Omron Sysmac Studio project ECT 自定义指令功能 20240816 (Sysmac Studio 1.50.0.64013, StandardProject)
(* 指令扩充 *)

# Controller new_Controller_0: NX102-1100 version 1.47
Units and slaves: 节点1 : CIFX RE/ECS (E001)
Task PrimaryTask (priority 4, period or condition 4000): program0

TYPE 机器人状态反馈1 : UNION
    motionstate1 : BYTE;
    state1 : ARRAY[0..7] OF BOOL;
END_UNION END_TYPE
TYPE 机器人状态反馈2 : UNION
    motionstate2 : BYTE;
    state2 : ARRAY[0..7] OF BOOL;
END_UNION END_TYPE
TYPE 机器人状态反馈3 : UNION
    motionstate3 : BYTE;
END_UNION END_TYPE
TYPE 机器人状态反馈4 : UNION
    motionstate4 : BYTE;
END_UNION END_TYPE

VAR_GLOBAL
    M0 : BOOL;  (* published *)
    M1 : BOOL;  (* published *)
    M2 : BOOL;  (* published *)
    M3 : BOOL;  (* published *)
    RobotCMD : UINT;
    RobotCMDLength : BYTE;
    RobotCMDState : BYTE;
    Robot_Header : ARRAY[0..5] OF BYTE;
    Robot_CMDHeader : ARRAY[0..9] OF BYTE;
    Robot_CMDPayload : ARRAY[0..119] OF BYTE;
    Robot_CyclicData : ARRAY[0..118] OF BYTE;
    Robot_Fooder : BYTE;
    M100 : BOOL;  (* published *)
    M101 : BOOL;  (* published *)
    M102 : BOOL;  (* published *)
    M103 : BOOL;  (* published *)
    M200 : BOOL;  (* published *)
    M201 : BOOL;  (* published *)
    M202 : BOOL;  (* published *)
    M203 : BOOL;  (* published *)
    M300 : BOOL;  (* published *)
    M301 : BOOL;  (* published *)
    M302 : BOOL;  (* network output *)
    M303 : BOOL;  (* network output *)
    M304 : BOOL;  (* network output *)
    M305 : BOOL;  (* network output *)
    M306 : BOOL;  (* network output *)
    EnableState : BOOL;
    R218L : BYTE;  (* network input *)
    R205 : REAL;  (* network input *)
    R207 : REAL;  (* network input *)
    R209 : REAL;  (* network input *)
    R211 : REAL;  (* network input *)
    R213 : REAL;  (* network input *)
    R215 : REAL;  (* network input *)
    R252 : UINT;  (* network output *)
    R218 : UINT;  (* network output *)
    R160 : REAL;  (* network output *)
    R105L : BYTE;  (* network input *)
    R162 : REAL;  (* network output *)
    R164 : REAL;  (* network output *)
    R166 : REAL;  (* network output *)
    R168 : REAL;  (* network output *)
    R170 : REAL;  (* network output *)
    R152 : UINT;  (* network output *)
    R352 : UINT;  (* network output *)
    R325L : BYTE;  (* network input *)
    R317 : REAL;  (* network input *)
    R319 : REAL;  (* network input *)
    R305 : REAL;  (* network input *)
    R307 : REAL;  (* network input *)
    R309 : REAL;  (* network input *)
    R311 : REAL;  (* network input *)
    R312 : REAL;  (* network input *)
    R313 : REAL;  (* network input *)
    R315 : REAL;  (* network input *)
    R12 : UINT;  (* published *)
    M400 : BOOL;  (* published *)
    R425L : BYTE;  (* published *)
    R417 : REAL;  (* published *)
    R419 : REAL;  (* published *)
    R405 : REAL;  (* published *)
    R407 : REAL;  (* published *)
    R409 : REAL;  (* published *)
    R411 : REAL;  (* published *)
    R413 : REAL;  (* published *)
    R415 : REAL;  (* published *)
    M401 : BOOL;  (* published *)
    M402 : BOOL;  (* published *)
    M404 : BOOL;  (* published *)
    M405 : BOOL;  (* published *)
    M406 : BOOL;  (* published *)
    M403 : BOOL;  (* published *)
    R452 : UINT;  (* published *)
    M500 : BOOL;  (* published *)
    R525L : BYTE;  (* published *)
    R525H : BYTE;  (* published *)
    R517 : REAL;  (* published *)
    R519 : REAL;  (* published *)
    R505 : REAL;  (* published *)
    R507 : REAL;  (* published *)
    R509 : REAL;  (* published *)
    R511 : REAL;  (* published *)
    R513 : REAL;  (* published *)
    R515 : REAL;  (* published *)
    M501 : BOOL;  (* published *)
    M502 : BOOL;  (* published *)
    M503 : BOOL;  (* published *)
    M504 : BOOL;  (* published *)
    M505 : BOOL;  (* published *)
    M506 : BOOL;  (* published *)
    R552 : UINT;  (* published *)
    B0 : BOOL;  (* LINK; published *)
    PLC_Header : ARRAY[0..5] OF BYTE;
    PLC_CMDHeader : ARRAY[0..9] OF BYTE;
    PLC_CMDPayload : ARRAY[0..238] OF BYTE;
    TOOLDATA_X : REAL;  (* published *)
    TOOLDATA_Y : REAL;  (* published *)
    TOOLDATA_Z : REAL;  (* published *)
    TOOLDATA_RX : REAL;  (* published *)
    TOOLDATA_RY : REAL;  (* published *)
    TOOLDATA_RZ : REAL;  (* published *)
    ROBOT_J1 : REAL;  (* published *)
    ROBOT_J2 : REAL;  (* published *)
    ROBOT_J3 : REAL;  (* published *)
    ROBOT_J4 : REAL;  (* published *)
    ROBOT_J5 : REAL;  (* published *)
    ROBOT_J6 : REAL;  (* published *)
    ROBOT_TOOLNO : BYTE;  (* published *)
    ROBOT_FRAMENO : BYTE;  (* published *)
    B1 : BOOL;  (* 已使能; published *)
    B2 : BOOL;  (* 运动完成; published *)
    B3 : BOOL;  (* 自动模式; published *)
    B4 : BOOL;  (* 手动模式; published *)
    B5 : BOOL;  (* 本地模式; published *)
    B6 : BOOL;  (* 远程模式; published *)
    B7 : BOOL;  (* 停止; published *)
    B8 : BOOL;  (* 运行; published *)
    B9 : BOOL;  (* 暂停; published *)
    B10 : BOOL;  (* 拖动; published *)
    B11 : BOOL;  (* 机器人报错; published *)
    Joint_Move : BOOL;  (* published *)
    Cartesian_Move : BOOL;  (* published *)
    ECT_OUT : ARRAY[0..255] OF BYTE;  (* network output *)
    ECT_IN : ARRAY[0..255] OF BYTE;  (* network input *)
    RobotCMDErrorcode : BYTE;
    R218H : BYTE;  (* published *)
    R217L : BOOL;  (* published *)
    R217H : BOOL;  (* published *)
    R172L : BOOL;  (* published *)
    R172H : BOOL;  (* published *)
    R173L : BOOL;  (* published *)
    M600 : BOOL;  (* published *)
    Out0 : BYTE;  (* at ECAT://node#1/Outputs0_1 Byte Out (0)_2000_01; network output *)
    Out1 : BYTE;  (* at ECAT://node#1/Outputs0_1 Byte Out (1)_2000_02; network output *)
    Out2 : BYTE;  (* at ECAT://node#1/Outputs0_1 Byte Out (2)_2000_03; network output *)
    Out3 : BYTE;  (* at ECAT://node#1/Outputs0_1 Byte Out (3)_2000_04; network output *)
    Out4 : BYTE;  (* at ECAT://node#1/Outputs0_1 Byte Out (4)_2000_05; network output *)
    Out5 : BYTE;  (* at ECAT://node#1/Outputs0_1 Byte Out (5)_2000_06; network output *)
    Out6 : BYTE;  (* at ECAT://node#1/Outputs0_1 Byte Out (6)_2000_07; network output *)
    Out7 : BYTE;  (* at ECAT://node#1/Outputs0_1 Byte Out (7)_2000_08; network output *)
    Out8 : BYTE;  (* at ECAT://node#1/Outputs0_1 Byte Out (8)_2000_09; network output *)
    Out9 : BYTE;  (* at ECAT://node#1/Outputs0_1 Byte Out (9)_2000_0A; network output *)
    Out10 : BYTE;  (* at ECAT://node#1/Outputs0_1 Byte Out (10)_2000_0B; network output *)
    Out11 : BYTE;  (* at ECAT://node#1/Outputs0_1 Byte Out (11)_2000_0C; network output *)
    Out12 : BYTE;  (* at ECAT://node#1/Outputs0_1 Byte Out (12)_2000_0D; network output *)
    Out13 : BYTE;  (* at ECAT://node#1/Outputs0_1 Byte Out (13)_2000_0E; network output *)
    Out14 : BYTE;  (* at ECAT://node#1/Outputs0_1 Byte Out (14)_2000_0F; network output *)
    Out15 : BYTE;  (* at ECAT://node#1/Outputs0_1 Byte Out (15)_2000_10; network output *)
    Out16 : BYTE;  (* at ECAT://node#1/Outputs0_1 Byte Out (16)_2000_11; network output *)
    Out17 : BYTE;  (* at ECAT://node#1/Outputs0_1 Byte Out (17)_2000_12; network output *)
    Out18 : BYTE;  (* at ECAT://node#1/Outputs0_1 Byte Out (18)_2000_13; network output *)
    Out19 : BYTE;  (* at ECAT://node#1/Outputs0_1 Byte Out (19)_2000_14; network output *)
    Out20 : BYTE;  (* at ECAT://node#1/Outputs0_1 Byte Out (20)_2000_15; network output *)
    Out21 : BYTE;  (* at ECAT://node#1/Outputs0_1 Byte Out (21)_2000_16; network output *)
    Out22 : BYTE;  (* at ECAT://node#1/Outputs0_1 Byte Out (22)_2000_17; network output *)
    Out23 : BYTE;  (* at ECAT://node#1/Outputs0_1 Byte Out (23)_2000_18; network output *)
    Out24 : BYTE;  (* at ECAT://node#1/Outputs0_1 Byte Out (24)_2000_19; network output *)
    Out25 : BYTE;  (* at ECAT://node#1/Outputs0_1 Byte Out (25)_2000_1A; network output *)
    Out26 : BYTE;  (* at ECAT://node#1/Outputs0_1 Byte Out (26)_2000_1B; network output *)
    Out27 : BYTE;  (* at ECAT://node#1/Outputs0_1 Byte Out (27)_2000_1C; network output *)
    Out28 : BYTE;  (* at ECAT://node#1/Outputs0_1 Byte Out (28)_2000_1D; network output *)
    Out29 : BYTE;  (* at ECAT://node#1/Outputs0_1 Byte Out (29)_2000_1E; network output *)
    Out30 : BYTE;  (* at ECAT://node#1/Outputs0_1 Byte Out (30)_2000_1F; network output *)
    Out31 : BYTE;  (* at ECAT://node#1/Outputs0_1 Byte Out (31)_2000_20; network output *)
    Out32 : BYTE;  (* at ECAT://node#1/Outputs0_1 Byte Out (32)_2000_21; network output *)
    Out33 : BYTE;  (* at ECAT://node#1/Outputs0_1 Byte Out (33)_2000_22; network output *)
    Out34 : BYTE;  (* at ECAT://node#1/Outputs0_1 Byte Out (34)_2000_23; network output *)
    Out35 : BYTE;  (* at ECAT://node#1/Outputs0_1 Byte Out (35)_2000_24; network output *)
    Out36 : BYTE;  (* at ECAT://node#1/Outputs0_1 Byte Out (36)_2000_25; network output *)
    Out37 : BYTE;  (* at ECAT://node#1/Outputs0_1 Byte Out (37)_2000_26; network output *)
    Out38 : BYTE;  (* at ECAT://node#1/Outputs0_1 Byte Out (38)_2000_27; network output *)
    Out39 : BYTE;  (* at ECAT://node#1/Outputs0_1 Byte Out (39)_2000_28; network output *)
    Out40 : BYTE;  (* at ECAT://node#1/Outputs0_1 Byte Out (40)_2000_29; network output *)
    Out41 : BYTE;  (* at ECAT://node#1/Outputs0_1 Byte Out (41)_2000_2A; network output *)
    Out42 : BYTE;  (* at ECAT://node#1/Outputs0_1 Byte Out (42)_2000_2B; network output *)
    Out43 : BYTE;  (* at ECAT://node#1/Outputs0_1 Byte Out (43)_2000_2C; network output *)
    Out44 : BYTE;  (* at ECAT://node#1/Outputs0_1 Byte Out (44)_2000_2D; network output *)
    Out45 : BYTE;  (* at ECAT://node#1/Outputs0_1 Byte Out (45)_2000_2E; network output *)
    Out46 : BYTE;  (* at ECAT://node#1/Outputs0_1 Byte Out (46)_2000_2F; network output *)
    Out47 : BYTE;  (* at ECAT://node#1/Outputs0_1 Byte Out (47)_2000_30; network output *)
    Out48 : BYTE;  (* at ECAT://node#1/Outputs0_1 Byte Out (48)_2000_31; network output *)
    Out49 : BYTE;  (* at ECAT://node#1/Outputs0_1 Byte Out (49)_2000_32; network output *)
    Out50 : BYTE;  (* at ECAT://node#1/Outputs0_1 Byte Out (50)_2000_33; network output *)
    Out51 : BYTE;  (* at ECAT://node#1/Outputs0_1 Byte Out (51)_2000_34; network output *)
    Out52 : BYTE;  (* at ECAT://node#1/Outputs0_1 Byte Out (52)_2000_35; network output *)
    Out53 : BYTE;  (* at ECAT://node#1/Outputs0_1 Byte Out (53)_2000_36; network output *)
    Out54 : BYTE;  (* at ECAT://node#1/Outputs0_1 Byte Out (54)_2000_37; network output *)
    Out55 : BYTE;  (* at ECAT://node#1/Outputs0_1 Byte Out (55)_2000_38; network output *)
    Out56 : BYTE;  (* at ECAT://node#1/Outputs0_1 Byte Out (56)_2000_39; network output *)
    Out57 : BYTE;  (* at ECAT://node#1/Outputs0_1 Byte Out (57)_2000_3A; network output *)
    Out58 : BYTE;  (* at ECAT://node#1/Outputs0_1 Byte Out (58)_2000_3B; network output *)
    Out59 : BYTE;  (* at ECAT://node#1/Outputs0_1 Byte Out (59)_2000_3C; network output *)
    Out60 : BYTE;  (* at ECAT://node#1/Outputs0_1 Byte Out (60)_2000_3D; network output *)
    Out61 : BYTE;  (* at ECAT://node#1/Outputs0_1 Byte Out (61)_2000_3E; network output *)
    Out62 : BYTE;  (* at ECAT://node#1/Outputs0_1 Byte Out (62)_2000_3F; network output *)
    Out63 : BYTE;  (* at ECAT://node#1/Outputs0_1 Byte Out (63)_2000_40; network output *)
    Out64 : BYTE;  (* at ECAT://node#1/Outputs0_1 Byte Out (64)_2000_41; network output *)
    Out65 : BYTE;  (* at ECAT://node#1/Outputs0_1 Byte Out (65)_2000_42; network output *)
    Out66 : BYTE;  (* at ECAT://node#1/Outputs0_1 Byte Out (66)_2000_43; network output *)
    Out67 : BYTE;  (* at ECAT://node#1/Outputs0_1 Byte Out (67)_2000_44; network output *)
    Out68 : BYTE;  (* at ECAT://node#1/Outputs0_1 Byte Out (68)_2000_45; network output *)
    Out69 : BYTE;  (* at ECAT://node#1/Outputs0_1 Byte Out (69)_2000_46; network output *)
    Out70 : BYTE;  (* at ECAT://node#1/Outputs0_1 Byte Out (70)_2000_47; network output *)
    Out71 : BYTE;  (* at ECAT://node#1/Outputs0_1 Byte Out (71)_2000_48; network output *)
    Out72 : BYTE;  (* at ECAT://node#1/Outputs0_1 Byte Out (72)_2000_49; network output *)
    Out73 : BYTE;  (* at ECAT://node#1/Outputs0_1 Byte Out (73)_2000_4A; network output *)
    Out74 : BYTE;  (* at ECAT://node#1/Outputs0_1 Byte Out (74)_2000_4B; network output *)
    Out75 : BYTE;  (* at ECAT://node#1/Outputs0_1 Byte Out (75)_2000_4C; network output *)
    Out76 : BYTE;  (* at ECAT://node#1/Outputs0_1 Byte Out (76)_2000_4D; network output *)
    Out77 : BYTE;  (* at ECAT://node#1/Outputs0_1 Byte Out (77)_2000_4E; network output *)
    Out78 : BYTE;  (* at ECAT://node#1/Outputs0_1 Byte Out (78)_2000_4F; network output *)
    Out79 : BYTE;  (* at ECAT://node#1/Outputs0_1 Byte Out (79)_2000_50; network output *)
    Out80 : BYTE;  (* at ECAT://node#1/Outputs0_1 Byte Out (80)_2000_51; network output *)
    Out81 : BYTE;  (* at ECAT://node#1/Outputs0_1 Byte Out (81)_2000_52; network output *)
    Out82 : BYTE;  (* at ECAT://node#1/Outputs0_1 Byte Out (82)_2000_53; network output *)
    Out83 : BYTE;  (* at ECAT://node#1/Outputs0_1 Byte Out (83)_2000_54; network output *)
    Out84 : BYTE;  (* at ECAT://node#1/Outputs0_1 Byte Out (84)_2000_55; network output *)
    Out85 : BYTE;  (* at ECAT://node#1/Outputs0_1 Byte Out (85)_2000_56; network output *)
    Out86 : BYTE;  (* at ECAT://node#1/Outputs0_1 Byte Out (86)_2000_57; network output *)
    Out87 : BYTE;  (* at ECAT://node#1/Outputs0_1 Byte Out (87)_2000_58; network output *)
    Out88 : BYTE;  (* at ECAT://node#1/Outputs0_1 Byte Out (88)_2000_59; network output *)
    Out89 : BYTE;  (* at ECAT://node#1/Outputs0_1 Byte Out (89)_2000_5A; network output *)
    Out90 : BYTE;  (* at ECAT://node#1/Outputs0_1 Byte Out (90)_2000_5B; network output *)
    Out91 : BYTE;  (* at ECAT://node#1/Outputs0_1 Byte Out (91)_2000_5C; network output *)
    Out92 : BYTE;  (* at ECAT://node#1/Outputs0_1 Byte Out (92)_2000_5D; network output *)
    Out93 : BYTE;  (* at ECAT://node#1/Outputs0_1 Byte Out (93)_2000_5E; network output *)
    Out94 : BYTE;  (* at ECAT://node#1/Outputs0_1 Byte Out (94)_2000_5F; network output *)
    Out95 : BYTE;  (* at ECAT://node#1/Outputs0_1 Byte Out (95)_2000_60; network output *)
    Out96 : BYTE;  (* at ECAT://node#1/Outputs0_1 Byte Out (96)_2000_61; network output *)
    Out97 : BYTE;  (* at ECAT://node#1/Outputs0_1 Byte Out (97)_2000_62; network output *)
    Out98 : BYTE;  (* at ECAT://node#1/Outputs0_1 Byte Out (98)_2000_63; network output *)
    Out99 : BYTE;  (* at ECAT://node#1/Outputs0_1 Byte Out (99)_2000_64; network output *)
    Out100 : BYTE;  (* at ECAT://node#1/Outputs0_1 Byte Out (100)_2000_65; network output *)
    Out101 : BYTE;  (* at ECAT://node#1/Outputs0_1 Byte Out (101)_2000_66; network output *)
    Out102 : BYTE;  (* at ECAT://node#1/Outputs0_1 Byte Out (102)_2000_67; network output *)
    Out103 : BYTE;  (* at ECAT://node#1/Outputs0_1 Byte Out (103)_2000_68; network output *)
    Out104 : BYTE;  (* at ECAT://node#1/Outputs0_1 Byte Out (104)_2000_69; network output *)
    Out105 : BYTE;  (* at ECAT://node#1/Outputs0_1 Byte Out (105)_2000_6A; network output *)
    Out106 : BYTE;  (* at ECAT://node#1/Outputs0_1 Byte Out (106)_2000_6B; network output *)
    Out107 : BYTE;  (* at ECAT://node#1/Outputs0_1 Byte Out (107)_2000_6C; network output *)
    Out108 : BYTE;  (* at ECAT://node#1/Outputs0_1 Byte Out (108)_2000_6D; network output *)
    Out109 : BYTE;  (* at ECAT://node#1/Outputs0_1 Byte Out (109)_2000_6E; network output *)
    Out110 : BYTE;  (* at ECAT://node#1/Outputs0_1 Byte Out (110)_2000_6F; network output *)
    Out111 : BYTE;  (* at ECAT://node#1/Outputs0_1 Byte Out (111)_2000_70; network output *)
    Out112 : BYTE;  (* at ECAT://node#1/Outputs0_1 Byte Out (112)_2000_71; network output *)
    Out113 : BYTE;  (* at ECAT://node#1/Outputs0_1 Byte Out (113)_2000_72; network output *)
    Out114 : BYTE;  (* at ECAT://node#1/Outputs0_1 Byte Out (114)_2000_73; network output *)
    Out115 : BYTE;  (* at ECAT://node#1/Outputs0_1 Byte Out (115)_2000_74; network output *)
    Out116 : BYTE;  (* at ECAT://node#1/Outputs0_1 Byte Out (116)_2000_75; network output *)
    Out117 : BYTE;  (* at ECAT://node#1/Outputs0_1 Byte Out (117)_2000_76; network output *)
    Out118 : BYTE;  (* at ECAT://node#1/Outputs0_1 Byte Out (118)_2000_77; network output *)
    Out119 : BYTE;  (* at ECAT://node#1/Outputs0_1 Byte Out (119)_2000_78; network output *)
    Out120 : BYTE;  (* at ECAT://node#1/Outputs0_1 Byte Out (120)_2000_79; network output *)
    Out121 : BYTE;  (* at ECAT://node#1/Outputs0_1 Byte Out (121)_2000_7A; network output *)
    Out122 : BYTE;  (* at ECAT://node#1/Outputs0_1 Byte Out (122)_2000_7B; network output *)
    Out123 : BYTE;  (* at ECAT://node#1/Outputs0_1 Byte Out (123)_2000_7C; network output *)
    Out124 : BYTE;  (* at ECAT://node#1/Outputs0_1 Byte Out (124)_2000_7D; network output *)
    Out125 : BYTE;  (* at ECAT://node#1/Outputs0_1 Byte Out (125)_2000_7E; network output *)
    Out126 : BYTE;  (* at ECAT://node#1/Outputs0_1 Byte Out (126)_2000_7F; network output *)
    Out127 : BYTE;  (* at ECAT://node#1/Outputs0_1 Byte Out (127)_2000_80; network output *)
    Out128 : BYTE;  (* at ECAT://node#1/Outputs0_1 Byte Out (128)_2000_81; network output *)
    Out129 : BYTE;  (* at ECAT://node#1/Outputs0_1 Byte Out (129)_2000_82; network output *)
    Out130 : BYTE;  (* at ECAT://node#1/Outputs0_1 Byte Out (130)_2000_83; network output *)
    Out131 : BYTE;  (* at ECAT://node#1/Outputs0_1 Byte Out (131)_2000_84; network output *)
    Out132 : BYTE;  (* at ECAT://node#1/Outputs0_1 Byte Out (132)_2000_85; network output *)
    Out133 : BYTE;  (* at ECAT://node#1/Outputs0_1 Byte Out (133)_2000_86; network output *)
    Out134 : BYTE;  (* at ECAT://node#1/Outputs0_1 Byte Out (134)_2000_87; network output *)
    Out135 : BYTE;  (* at ECAT://node#1/Outputs0_1 Byte Out (135)_2000_88; network output *)
    Out136 : BYTE;  (* at ECAT://node#1/Outputs0_1 Byte Out (136)_2000_89; network output *)
    Out137 : BYTE;  (* at ECAT://node#1/Outputs0_1 Byte Out (137)_2000_8A; network output *)
    Out138 : BYTE;  (* at ECAT://node#1/Outputs0_1 Byte Out (138)_2000_8B; network output *)
    Out139 : BYTE;  (* at ECAT://node#1/Outputs0_1 Byte Out (139)_2000_8C; network output *)
    Out140 : BYTE;  (* at ECAT://node#1/Outputs0_1 Byte Out (140)_2000_8D; network output *)
    Out141 : BYTE;  (* at ECAT://node#1/Outputs0_1 Byte Out (141)_2000_8E; network output *)
    Out142 : BYTE;  (* at ECAT://node#1/Outputs0_1 Byte Out (142)_2000_8F; network output *)
    Out143 : BYTE;  (* at ECAT://node#1/Outputs0_1 Byte Out (143)_2000_90; network output *)
    Out144 : BYTE;  (* at ECAT://node#1/Outputs0_1 Byte Out (144)_2000_91; network output *)
    Out145 : BYTE;  (* at ECAT://node#1/Outputs0_1 Byte Out (145)_2000_92; network output *)
    Out146 : BYTE;  (* at ECAT://node#1/Outputs0_1 Byte Out (146)_2000_93; network output *)
    Out147 : BYTE;  (* at ECAT://node#1/Outputs0_1 Byte Out (147)_2000_94; network output *)
    Out148 : BYTE;  (* at ECAT://node#1/Outputs0_1 Byte Out (148)_2000_95; network output *)
    Out149 : BYTE;  (* at ECAT://node#1/Outputs0_1 Byte Out (149)_2000_96; network output *)
    Out150 : BYTE;  (* at ECAT://node#1/Outputs0_1 Byte Out (150)_2000_97; network output *)
    Out151 : BYTE;  (* at ECAT://node#1/Outputs0_1 Byte Out (151)_2000_98; network output *)
    Out152 : BYTE;  (* at ECAT://node#1/Outputs0_1 Byte Out (152)_2000_99; network output *)
    Out153 : BYTE;  (* at ECAT://node#1/Outputs0_1 Byte Out (153)_2000_9A; network output *)
    Out154 : BYTE;  (* at ECAT://node#1/Outputs0_1 Byte Out (154)_2000_9B; network output *)
    Out155 : BYTE;  (* at ECAT://node#1/Outputs0_1 Byte Out (155)_2000_9C; network output *)
    Out156 : BYTE;  (* at ECAT://node#1/Outputs0_1 Byte Out (156)_2000_9D; network output *)
    Out157 : BYTE;  (* at ECAT://node#1/Outputs0_1 Byte Out (157)_2000_9E; network output *)
    Out158 : BYTE;  (* at ECAT://node#1/Outputs0_1 Byte Out (158)_2000_9F; network output *)
    Out159 : BYTE;  (* at ECAT://node#1/Outputs0_1 Byte Out (159)_2000_A0; network output *)
    Out160 : BYTE;  (* at ECAT://node#1/Outputs0_1 Byte Out (160)_2000_A1; network output *)
    Out161 : BYTE;  (* at ECAT://node#1/Outputs0_1 Byte Out (161)_2000_A2; network output *)
    Out162 : BYTE;  (* at ECAT://node#1/Outputs0_1 Byte Out (162)_2000_A3; network output *)
    Out163 : BYTE;  (* at ECAT://node#1/Outputs0_1 Byte Out (163)_2000_A4; network output *)
    Out164 : BYTE;  (* at ECAT://node#1/Outputs0_1 Byte Out (164)_2000_A5; network output *)
    Out165 : BYTE;  (* at ECAT://node#1/Outputs0_1 Byte Out (165)_2000_A6; network output *)
    Out166 : BYTE;  (* at ECAT://node#1/Outputs0_1 Byte Out (166)_2000_A7; network output *)
    Out167 : BYTE;  (* at ECAT://node#1/Outputs0_1 Byte Out (167)_2000_A8; network output *)
    Out168 : BYTE;  (* at ECAT://node#1/Outputs0_1 Byte Out (168)_2000_A9; network output *)
    Out169 : BYTE;  (* at ECAT://node#1/Outputs0_1 Byte Out (169)_2000_AA; network output *)
    Out170 : BYTE;  (* at ECAT://node#1/Outputs0_1 Byte Out (170)_2000_AB; network output *)
    Out171 : BYTE;  (* at ECAT://node#1/Outputs0_1 Byte Out (171)_2000_AC; network output *)
    Out172 : BYTE;  (* at ECAT://node#1/Outputs0_1 Byte Out (172)_2000_AD; network output *)
    Out173 : BYTE;  (* at ECAT://node#1/Outputs0_1 Byte Out (173)_2000_AE; network output *)
    Out174 : BYTE;  (* at ECAT://node#1/Outputs0_1 Byte Out (174)_2000_AF; network output *)
    Out175 : BYTE;  (* at ECAT://node#1/Outputs0_1 Byte Out (175)_2000_B0; network output *)
    Out176 : BYTE;  (* at ECAT://node#1/Outputs0_1 Byte Out (176)_2000_B1; network output *)
    Out177 : BYTE;  (* at ECAT://node#1/Outputs0_1 Byte Out (177)_2000_B2; network output *)
    Out178 : BYTE;  (* at ECAT://node#1/Outputs0_1 Byte Out (178)_2000_B3; network output *)
    Out179 : BYTE;  (* at ECAT://node#1/Outputs0_1 Byte Out (179)_2000_B4; network output *)
    Out180 : BYTE;  (* at ECAT://node#1/Outputs0_1 Byte Out (180)_2000_B5; network output *)
    Out181 : BYTE;  (* at ECAT://node#1/Outputs0_1 Byte Out (181)_2000_B6; network output *)
    Out182 : BYTE;  (* at ECAT://node#1/Outputs0_1 Byte Out (182)_2000_B7; network output *)
    Out183 : BYTE;  (* at ECAT://node#1/Outputs0_1 Byte Out (183)_2000_B8; network output *)
    Out184 : BYTE;  (* at ECAT://node#1/Outputs0_1 Byte Out (184)_2000_B9; network output *)
    Out185 : BYTE;  (* at ECAT://node#1/Outputs0_1 Byte Out (185)_2000_BA; network output *)
    Out186 : BYTE;  (* at ECAT://node#1/Outputs0_1 Byte Out (186)_2000_BB; network output *)
    Out187 : BYTE;  (* at ECAT://node#1/Outputs0_1 Byte Out (187)_2000_BC; network output *)
    Out188 : BYTE;  (* at ECAT://node#1/Outputs0_1 Byte Out (188)_2000_BD; network output *)
    Out189 : BYTE;  (* at ECAT://node#1/Outputs0_1 Byte Out (189)_2000_BE; network output *)
    Out190 : BYTE;  (* at ECAT://node#1/Outputs0_1 Byte Out (190)_2000_BF; network output *)
    Out191 : BYTE;  (* at ECAT://node#1/Outputs0_1 Byte Out (191)_2000_C0; network output *)
    Out192 : BYTE;  (* at ECAT://node#1/Outputs0_1 Byte Out (192)_2000_C1; network output *)
    Out193 : BYTE;  (* at ECAT://node#1/Outputs0_1 Byte Out (193)_2000_C2; network output *)
    Out194 : BYTE;  (* at ECAT://node#1/Outputs0_1 Byte Out (194)_2000_C3; network output *)
    Out195 : BYTE;  (* at ECAT://node#1/Outputs0_1 Byte Out (195)_2000_C4; network output *)
    Out196 : BYTE;  (* at ECAT://node#1/Outputs0_1 Byte Out (196)_2000_C5; network output *)
    Out197 : BYTE;  (* at ECAT://node#1/Outputs0_1 Byte Out (197)_2000_C6; network output *)
    Out198 : BYTE;  (* at ECAT://node#1/Outputs0_1 Byte Out (198)_2000_C7; network output *)
    Out199 : BYTE;  (* at ECAT://node#1/Outputs0_1 Byte Out (199)_2000_C8; network output *)
    Out200 : BYTE;  (* at ECAT://node#1/Outputs1_1 Byte Out (200)_2001_01; network output *)
    Out201 : BYTE;  (* at ECAT://node#1/Outputs1_1 Byte Out (201)_2001_02; network output *)
    Out202 : BYTE;  (* at ECAT://node#1/Outputs1_1 Byte Out (202)_2001_03; network output *)
    Out203 : BYTE;  (* at ECAT://node#1/Outputs1_1 Byte Out (203)_2001_04; network output *)
    Out204 : BYTE;  (* at ECAT://node#1/Outputs1_1 Byte Out (204)_2001_05; network output *)
    Out205 : BYTE;  (* at ECAT://node#1/Outputs1_1 Byte Out (205)_2001_06; network output *)
    Out206 : BYTE;  (* at ECAT://node#1/Outputs1_1 Byte Out (206)_2001_07; network output *)
    Out207 : BYTE;  (* at ECAT://node#1/Outputs1_1 Byte Out (207)_2001_08; network output *)
    Out208 : BYTE;  (* at ECAT://node#1/Outputs1_1 Byte Out (208)_2001_09; network output *)
    Out209 : BYTE;  (* at ECAT://node#1/Outputs1_1 Byte Out (209)_2001_0A; network output *)
    Out210 : BYTE;  (* at ECAT://node#1/Outputs1_1 Byte Out (210)_2001_0B; network output *)
    Out211 : BYTE;  (* at ECAT://node#1/Outputs1_1 Byte Out (211)_2001_0C; network output *)
    Out212 : BYTE;  (* at ECAT://node#1/Outputs1_1 Byte Out (212)_2001_0D; network output *)
    Out213 : BYTE;  (* at ECAT://node#1/Outputs1_1 Byte Out (213)_2001_0E; network output *)
    Out214 : BYTE;  (* at ECAT://node#1/Outputs1_1 Byte Out (214)_2001_0F; network output *)
    Out215 : BYTE;  (* at ECAT://node#1/Outputs1_1 Byte Out (215)_2001_10; network output *)
    Out216 : BYTE;  (* at ECAT://node#1/Outputs1_1 Byte Out (216)_2001_11; network output *)
    Out217 : BYTE;  (* at ECAT://node#1/Outputs1_1 Byte Out (217)_2001_12; network output *)
    Out218 : BYTE;  (* at ECAT://node#1/Outputs1_1 Byte Out (218)_2001_13; network output *)
    Out219 : BYTE;  (* at ECAT://node#1/Outputs1_1 Byte Out (219)_2001_14; network output *)
    Out220 : BYTE;  (* at ECAT://node#1/Outputs1_1 Byte Out (220)_2001_15; network output *)
    Out221 : BYTE;  (* at ECAT://node#1/Outputs1_1 Byte Out (221)_2001_16; network output *)
    Out222 : BYTE;  (* at ECAT://node#1/Outputs1_1 Byte Out (222)_2001_17; network output *)
    Out223 : BYTE;  (* at ECAT://node#1/Outputs1_1 Byte Out (223)_2001_18; network output *)
    Out224 : BYTE;  (* at ECAT://node#1/Outputs1_1 Byte Out (224)_2001_19; network output *)
    Out225 : BYTE;  (* at ECAT://node#1/Outputs1_1 Byte Out (225)_2001_1A; network output *)
    Out226 : BYTE;  (* at ECAT://node#1/Outputs1_1 Byte Out (226)_2001_1B; network output *)
    Out227 : BYTE;  (* at ECAT://node#1/Outputs1_1 Byte Out (227)_2001_1C; network output *)
    Out228 : BYTE;  (* at ECAT://node#1/Outputs1_1 Byte Out (228)_2001_1D; network output *)
    Out229 : BYTE;  (* at ECAT://node#1/Outputs1_1 Byte Out (229)_2001_1E; network output *)
    Out230 : BYTE;  (* at ECAT://node#1/Outputs1_1 Byte Out (230)_2001_1F; network output *)
    Out231 : BYTE;  (* at ECAT://node#1/Outputs1_1 Byte Out (231)_2001_20; network output *)
    Out232 : BYTE;  (* at ECAT://node#1/Outputs1_1 Byte Out (232)_2001_21; network output *)
    Out233 : BYTE;  (* at ECAT://node#1/Outputs1_1 Byte Out (233)_2001_22; network output *)
    Out234 : BYTE;  (* at ECAT://node#1/Outputs1_1 Byte Out (234)_2001_23; network output *)
    Out235 : BYTE;  (* at ECAT://node#1/Outputs1_1 Byte Out (235)_2001_24; network output *)
    Out236 : BYTE;  (* at ECAT://node#1/Outputs1_1 Byte Out (236)_2001_25; network output *)
    Out237 : BYTE;  (* at ECAT://node#1/Outputs1_1 Byte Out (237)_2001_26; network output *)
    Out238 : BYTE;  (* at ECAT://node#1/Outputs1_1 Byte Out (238)_2001_27; network output *)
    Out239 : BYTE;  (* at ECAT://node#1/Outputs1_1 Byte Out (239)_2001_28; network output *)
    Out240 : BYTE;  (* at ECAT://node#1/Outputs1_1 Byte Out (240)_2001_29; network output *)
    Out241 : BYTE;  (* at ECAT://node#1/Outputs1_1 Byte Out (241)_2001_2A; network output *)
    Out242 : BYTE;  (* at ECAT://node#1/Outputs1_1 Byte Out (242)_2001_2B; network output *)
    Out243 : BYTE;  (* at ECAT://node#1/Outputs1_1 Byte Out (243)_2001_2C; network output *)
    Out244 : BYTE;  (* at ECAT://node#1/Outputs1_1 Byte Out (244)_2001_2D; network output *)
    Out245 : BYTE;  (* at ECAT://node#1/Outputs1_1 Byte Out (245)_2001_2E; network output *)
    Out246 : BYTE;  (* at ECAT://node#1/Outputs1_1 Byte Out (246)_2001_2F; network output *)
    Out247 : BYTE;  (* at ECAT://node#1/Outputs1_1 Byte Out (247)_2001_30; network output *)
    Out248 : BYTE;  (* at ECAT://node#1/Outputs1_1 Byte Out (248)_2001_31; network output *)
    Out249 : BYTE;  (* at ECAT://node#1/Outputs1_1 Byte Out (249)_2001_32; network output *)
    Out250 : BYTE;  (* at ECAT://node#1/Outputs1_1 Byte Out (250)_2001_33; network output *)
    Out251 : BYTE;  (* at ECAT://node#1/Outputs1_1 Byte Out (251)_2001_34; network output *)
    Out252 : BYTE;  (* at ECAT://node#1/Outputs1_1 Byte Out (252)_2001_35; network output *)
    Out253 : BYTE;  (* at ECAT://node#1/Outputs1_1 Byte Out (253)_2001_36; network output *)
    Out254 : BYTE;  (* at ECAT://node#1/Outputs1_1 Byte Out (254)_2001_37; network output *)
    Out255 : BYTE;  (* at ECAT://node#1/Outputs1_1 Byte Out (255)_2001_38; network output *)
    IN0 : BYTE;  (* at ECAT://node#1/Inputs0_1 Byte In (0)_3000_01; network input *)
    IN1 : BYTE;  (* at ECAT://node#1/Inputs0_1 Byte In (1)_3000_02; network input *)
    IN2 : BYTE;  (* at ECAT://node#1/Inputs0_1 Byte In (2)_3000_03; network input *)
    IN3 : BYTE;  (* at ECAT://node#1/Inputs0_1 Byte In (3)_3000_04; network input *)
    IN4 : BYTE;  (* at ECAT://node#1/Inputs0_1 Byte In (4)_3000_05; network input *)
    IN5 : BYTE;  (* at ECAT://node#1/Inputs0_1 Byte In (5)_3000_06; network input *)
    IN6 : BYTE;  (* at ECAT://node#1/Inputs0_1 Byte In (6)_3000_07; network input *)
    IN7 : BYTE;  (* at ECAT://node#1/Inputs0_1 Byte In (7)_3000_08; network input *)
    IN8 : BYTE;  (* at ECAT://node#1/Inputs0_1 Byte In (8)_3000_09; network input *)
    IN9 : BYTE;  (* at ECAT://node#1/Inputs0_1 Byte In (9)_3000_0A; network input *)
    IN10 : BYTE;  (* at ECAT://node#1/Inputs0_1 Byte In (10)_3000_0B; network input *)
    IN11 : BYTE;  (* at ECAT://node#1/Inputs0_1 Byte In (11)_3000_0C; network input *)
    IN12 : BYTE;  (* at ECAT://node#1/Inputs0_1 Byte In (12)_3000_0D; network input *)
    IN13 : BYTE;  (* at ECAT://node#1/Inputs0_1 Byte In (13)_3000_0E; network input *)
    IN14 : BYTE;  (* at ECAT://node#1/Inputs0_1 Byte In (14)_3000_0F; network input *)
    IN15 : BYTE;  (* at ECAT://node#1/Inputs0_1 Byte In (15)_3000_10; network input *)
    IN16 : BYTE;  (* at ECAT://node#1/Inputs0_1 Byte In (16)_3000_11; network input *)
    IN17 : BYTE;  (* at ECAT://node#1/Inputs0_1 Byte In (17)_3000_12; network input *)
    IN18 : BYTE;  (* at ECAT://node#1/Inputs0_1 Byte In (18)_3000_13; network input *)
    IN19 : BYTE;  (* at ECAT://node#1/Inputs0_1 Byte In (19)_3000_14; network input *)
    IN20 : BYTE;  (* at ECAT://node#1/Inputs0_1 Byte In (20)_3000_15; network input *)
    IN21 : BYTE;  (* at ECAT://node#1/Inputs0_1 Byte In (21)_3000_16; network input *)
    IN22 : BYTE;  (* at ECAT://node#1/Inputs0_1 Byte In (22)_3000_17; network input *)
    IN23 : BYTE;  (* at ECAT://node#1/Inputs0_1 Byte In (23)_3000_18; network input *)
    IN24 : BYTE;  (* at ECAT://node#1/Inputs0_1 Byte In (24)_3000_19; network input *)
    IN25 : BYTE;  (* at ECAT://node#1/Inputs0_1 Byte In (25)_3000_1A; network input *)
    IN26 : BYTE;  (* at ECAT://node#1/Inputs0_1 Byte In (26)_3000_1B; network input *)
    IN27 : BYTE;  (* at ECAT://node#1/Inputs0_1 Byte In (27)_3000_1C; network input *)
    IN28 : BYTE;  (* at ECAT://node#1/Inputs0_1 Byte In (28)_3000_1D; network input *)
    IN29 : BYTE;  (* at ECAT://node#1/Inputs0_1 Byte In (29)_3000_1E; network input *)
    IN30 : BYTE;  (* at ECAT://node#1/Inputs0_1 Byte In (30)_3000_1F; network input *)
    IN31 : BYTE;  (* at ECAT://node#1/Inputs0_1 Byte In (31)_3000_20; network input *)
    IN32 : BYTE;  (* at ECAT://node#1/Inputs0_1 Byte In (32)_3000_21; network input *)
    IN33 : BYTE;  (* at ECAT://node#1/Inputs0_1 Byte In (33)_3000_22; network input *)
    IN34 : BYTE;  (* at ECAT://node#1/Inputs0_1 Byte In (34)_3000_23; network input *)
    IN35 : BYTE;  (* at ECAT://node#1/Inputs0_1 Byte In (35)_3000_24; network input *)
    IN36 : BYTE;  (* at ECAT://node#1/Inputs0_1 Byte In (36)_3000_25; network input *)
    IN37 : BYTE;  (* at ECAT://node#1/Inputs0_1 Byte In (37)_3000_26; network input *)
    IN38 : BYTE;  (* at ECAT://node#1/Inputs0_1 Byte In (38)_3000_27; network input *)
    IN39 : BYTE;  (* at ECAT://node#1/Inputs0_1 Byte In (39)_3000_28; network input *)
    IN40 : BYTE;  (* at ECAT://node#1/Inputs0_1 Byte In (40)_3000_29; network input *)
    IN41 : BYTE;  (* at ECAT://node#1/Inputs0_1 Byte In (41)_3000_2A; network input *)
    IN42 : BYTE;  (* at ECAT://node#1/Inputs0_1 Byte In (42)_3000_2B; network input *)
    IN43 : BYTE;  (* at ECAT://node#1/Inputs0_1 Byte In (43)_3000_2C; network input *)
    IN44 : BYTE;  (* at ECAT://node#1/Inputs0_1 Byte In (44)_3000_2D; network input *)
    IN45 : BYTE;  (* at ECAT://node#1/Inputs0_1 Byte In (45)_3000_2E; network input *)
    IN46 : BYTE;  (* at ECAT://node#1/Inputs0_1 Byte In (46)_3000_2F; network input *)
    IN47 : BYTE;  (* at ECAT://node#1/Inputs0_1 Byte In (47)_3000_30; network input *)
    IN48 : BYTE;  (* at ECAT://node#1/Inputs0_1 Byte In (48)_3000_31; network input *)
    IN49 : BYTE;  (* at ECAT://node#1/Inputs0_1 Byte In (49)_3000_32; network input *)
    IN50 : BYTE;  (* at ECAT://node#1/Inputs0_1 Byte In (50)_3000_33; network input *)
    IN51 : BYTE;  (* at ECAT://node#1/Inputs0_1 Byte In (51)_3000_34; network input *)
    IN52 : BYTE;  (* at ECAT://node#1/Inputs0_1 Byte In (52)_3000_35; network input *)
    IN53 : BYTE;  (* at ECAT://node#1/Inputs0_1 Byte In (53)_3000_36; network input *)
    IN54 : BYTE;  (* at ECAT://node#1/Inputs0_1 Byte In (54)_3000_37; network input *)
    IN55 : BYTE;  (* at ECAT://node#1/Inputs0_1 Byte In (55)_3000_38; network input *)
    IN56 : BYTE;  (* at ECAT://node#1/Inputs0_1 Byte In (56)_3000_39; network input *)
    IN57 : BYTE;  (* at ECAT://node#1/Inputs0_1 Byte In (57)_3000_3A; network input *)
    IN58 : BYTE;  (* at ECAT://node#1/Inputs0_1 Byte In (58)_3000_3B; network input *)
    IN59 : BYTE;  (* at ECAT://node#1/Inputs0_1 Byte In (59)_3000_3C; network input *)
    IN60 : BYTE;  (* at ECAT://node#1/Inputs0_1 Byte In (60)_3000_3D; network input *)
    IN61 : BYTE;  (* at ECAT://node#1/Inputs0_1 Byte In (61)_3000_3E; network input *)
    IN62 : BYTE;  (* at ECAT://node#1/Inputs0_1 Byte In (62)_3000_3F; network input *)
    IN63 : BYTE;  (* at ECAT://node#1/Inputs0_1 Byte In (63)_3000_40; network input *)
    IN64 : BYTE;  (* at ECAT://node#1/Inputs0_1 Byte In (64)_3000_41; network input *)
    IN65 : BYTE;  (* at ECAT://node#1/Inputs0_1 Byte In (65)_3000_42; network input *)
    IN66 : BYTE;  (* at ECAT://node#1/Inputs0_1 Byte In (66)_3000_43; network input *)
    IN67 : BYTE;  (* at ECAT://node#1/Inputs0_1 Byte In (67)_3000_44; network input *)
    IN68 : BYTE;  (* at ECAT://node#1/Inputs0_1 Byte In (68)_3000_45; network input *)
    IN69 : BYTE;  (* at ECAT://node#1/Inputs0_1 Byte In (69)_3000_46; network input *)
    IN70 : BYTE;  (* at ECAT://node#1/Inputs0_1 Byte In (70)_3000_47; network input *)
    IN71 : BYTE;  (* at ECAT://node#1/Inputs0_1 Byte In (71)_3000_48; network input *)
    IN72 : BYTE;  (* at ECAT://node#1/Inputs0_1 Byte In (72)_3000_49; network input *)
    IN73 : BYTE;  (* at ECAT://node#1/Inputs0_1 Byte In (73)_3000_4A; network input *)
    IN74 : BYTE;  (* at ECAT://node#1/Inputs0_1 Byte In (74)_3000_4B; network input *)
    IN75 : BYTE;  (* at ECAT://node#1/Inputs0_1 Byte In (75)_3000_4C; network input *)
    IN76 : BYTE;  (* at ECAT://node#1/Inputs0_1 Byte In (76)_3000_4D; network input *)
    IN77 : BYTE;  (* at ECAT://node#1/Inputs0_1 Byte In (77)_3000_4E; network input *)
    IN78 : BYTE;  (* at ECAT://node#1/Inputs0_1 Byte In (78)_3000_4F; network input *)
    IN79 : BYTE;  (* at ECAT://node#1/Inputs0_1 Byte In (79)_3000_50; network input *)
    IN80 : BYTE;  (* at ECAT://node#1/Inputs0_1 Byte In (80)_3000_51; network input *)
    IN81 : BYTE;  (* at ECAT://node#1/Inputs0_1 Byte In (81)_3000_52; network input *)
    IN82 : BYTE;  (* at ECAT://node#1/Inputs0_1 Byte In (82)_3000_53; network input *)
    IN83 : BYTE;  (* at ECAT://node#1/Inputs0_1 Byte In (83)_3000_54; network input *)
    IN84 : BYTE;  (* at ECAT://node#1/Inputs0_1 Byte In (84)_3000_55; network input *)
    IN85 : BYTE;  (* at ECAT://node#1/Inputs0_1 Byte In (85)_3000_56; network input *)
    IN86 : BYTE;  (* at ECAT://node#1/Inputs0_1 Byte In (86)_3000_57; network input *)
    IN87 : BYTE;  (* at ECAT://node#1/Inputs0_1 Byte In (87)_3000_58; network input *)
    IN88 : BYTE;  (* at ECAT://node#1/Inputs0_1 Byte In (88)_3000_59; network input *)
    IN89 : BYTE;  (* at ECAT://node#1/Inputs0_1 Byte In (89)_3000_5A; network input *)
    IN90 : BYTE;  (* at ECAT://node#1/Inputs0_1 Byte In (90)_3000_5B; network input *)
    IN91 : BYTE;  (* at ECAT://node#1/Inputs0_1 Byte In (91)_3000_5C; network input *)
    IN92 : BYTE;  (* at ECAT://node#1/Inputs0_1 Byte In (92)_3000_5D; network input *)
    IN93 : BYTE;  (* at ECAT://node#1/Inputs0_1 Byte In (93)_3000_5E; network input *)
    IN94 : BYTE;  (* at ECAT://node#1/Inputs0_1 Byte In (94)_3000_5F; network input *)
    IN95 : BYTE;  (* at ECAT://node#1/Inputs0_1 Byte In (95)_3000_60; network input *)
    IN96 : BYTE;  (* at ECAT://node#1/Inputs0_1 Byte In (96)_3000_61; network input *)
    IN97 : BYTE;  (* at ECAT://node#1/Inputs0_1 Byte In (97)_3000_62; network input *)
    IN98 : BYTE;  (* at ECAT://node#1/Inputs0_1 Byte In (98)_3000_63; network input *)
    IN99 : BYTE;  (* at ECAT://node#1/Inputs0_1 Byte In (99)_3000_64; network input *)
    IN100 : BYTE;  (* at ECAT://node#1/Inputs0_1 Byte In (100)_3000_65; network input *)
    IN101 : BYTE;  (* at ECAT://node#1/Inputs0_1 Byte In (101)_3000_66; network input *)
    IN102 : BYTE;  (* at ECAT://node#1/Inputs0_1 Byte In (102)_3000_67; network input *)
    IN103 : BYTE;  (* at ECAT://node#1/Inputs0_1 Byte In (103)_3000_68; network input *)
    IN104 : BYTE;  (* at ECAT://node#1/Inputs0_1 Byte In (104)_3000_69; network input *)
    IN105 : BYTE;  (* at ECAT://node#1/Inputs0_1 Byte In (105)_3000_6A; network input *)
    IN106 : BYTE;  (* at ECAT://node#1/Inputs0_1 Byte In (106)_3000_6B; network input *)
    IN107 : BYTE;  (* at ECAT://node#1/Inputs0_1 Byte In (107)_3000_6C; network input *)
    IN108 : BYTE;  (* at ECAT://node#1/Inputs0_1 Byte In (108)_3000_6D; network input *)
    IN109 : BYTE;  (* at ECAT://node#1/Inputs0_1 Byte In (109)_3000_6E; network input *)
    IN110 : BYTE;  (* at ECAT://node#1/Inputs0_1 Byte In (110)_3000_6F; network input *)
    IN111 : BYTE;  (* at ECAT://node#1/Inputs0_1 Byte In (111)_3000_70; network input *)
    IN112 : BYTE;  (* at ECAT://node#1/Inputs0_1 Byte In (112)_3000_71; network input *)
    IN113 : BYTE;  (* at ECAT://node#1/Inputs0_1 Byte In (113)_3000_72; network input *)
    IN114 : BYTE;  (* at ECAT://node#1/Inputs0_1 Byte In (114)_3000_73; network input *)
    IN115 : BYTE;  (* at ECAT://node#1/Inputs0_1 Byte In (115)_3000_74; network input *)
    IN116 : BYTE;  (* at ECAT://node#1/Inputs0_1 Byte In (116)_3000_75; network input *)
    IN117 : BYTE;  (* at ECAT://node#1/Inputs0_1 Byte In (117)_3000_76; network input *)
    IN118 : BYTE;  (* at ECAT://node#1/Inputs0_1 Byte In (118)_3000_77; network input *)
    IN119 : BYTE;  (* at ECAT://node#1/Inputs0_1 Byte In (119)_3000_78; network input *)
    IN120 : BYTE;  (* at ECAT://node#1/Inputs0_1 Byte In (120)_3000_79; network input *)
    IN121 : BYTE;  (* at ECAT://node#1/Inputs0_1 Byte In (121)_3000_7A; network input *)
    IN122 : BYTE;  (* at ECAT://node#1/Inputs0_1 Byte In (122)_3000_7B; network input *)
    IN123 : BYTE;  (* at ECAT://node#1/Inputs0_1 Byte In (123)_3000_7C; network input *)
    IN124 : BYTE;  (* at ECAT://node#1/Inputs0_1 Byte In (124)_3000_7D; network input *)
    IN125 : BYTE;  (* at ECAT://node#1/Inputs0_1 Byte In (125)_3000_7E; network input *)
    IN126 : BYTE;  (* at ECAT://node#1/Inputs0_1 Byte In (126)_3000_7F; network input *)
    IN127 : BYTE;  (* at ECAT://node#1/Inputs0_1 Byte In (127)_3000_80; network input *)
    IN128 : BYTE;  (* at ECAT://node#1/Inputs0_1 Byte In (128)_3000_81; network input *)
    IN129 : BYTE;  (* at ECAT://node#1/Inputs0_1 Byte In (129)_3000_82; network input *)
    IN130 : BYTE;  (* at ECAT://node#1/Inputs0_1 Byte In (130)_3000_83; network input *)
    IN131 : BYTE;  (* at ECAT://node#1/Inputs0_1 Byte In (131)_3000_84; network input *)
    IN132 : BYTE;  (* at ECAT://node#1/Inputs0_1 Byte In (132)_3000_85; network input *)
    IN133 : BYTE;  (* at ECAT://node#1/Inputs0_1 Byte In (133)_3000_86; network input *)
    IN134 : BYTE;  (* at ECAT://node#1/Inputs0_1 Byte In (134)_3000_87; network input *)
    IN135 : BYTE;  (* at ECAT://node#1/Inputs0_1 Byte In (135)_3000_88; network input *)
    IN136 : BYTE;  (* at ECAT://node#1/Inputs0_1 Byte In (136)_3000_89; network input *)
    IN137 : BYTE;  (* at ECAT://node#1/Inputs0_1 Byte In (137)_3000_8A; network input *)
    IN138 : BYTE;  (* at ECAT://node#1/Inputs0_1 Byte In (138)_3000_8B; network input *)
    IN139 : BYTE;  (* at ECAT://node#1/Inputs0_1 Byte In (139)_3000_8C; network input *)
    IN140 : BYTE;  (* at ECAT://node#1/Inputs0_1 Byte In (140)_3000_8D; network input *)
    IN141 : BYTE;  (* at ECAT://node#1/Inputs0_1 Byte In (141)_3000_8E; network input *)
    IN142 : BYTE;  (* at ECAT://node#1/Inputs0_1 Byte In (142)_3000_8F; network input *)
    IN143 : BYTE;  (* at ECAT://node#1/Inputs0_1 Byte In (143)_3000_90; network input *)
    IN144 : BYTE;  (* at ECAT://node#1/Inputs0_1 Byte In (144)_3000_91; network input *)
    IN145 : BYTE;  (* at ECAT://node#1/Inputs0_1 Byte In (145)_3000_92; network input *)
    IN146 : BYTE;  (* at ECAT://node#1/Inputs0_1 Byte In (146)_3000_93; network input *)
    IN147 : BYTE;  (* at ECAT://node#1/Inputs0_1 Byte In (147)_3000_94; network input *)
    IN148 : BYTE;  (* at ECAT://node#1/Inputs0_1 Byte In (148)_3000_95; network input *)
    IN149 : BYTE;  (* at ECAT://node#1/Inputs0_1 Byte In (149)_3000_96; network input *)
    IN150 : BYTE;  (* at ECAT://node#1/Inputs0_1 Byte In (150)_3000_97; network input *)
    IN151 : BYTE;  (* at ECAT://node#1/Inputs0_1 Byte In (151)_3000_98; network input *)
    IN152 : BYTE;  (* at ECAT://node#1/Inputs0_1 Byte In (152)_3000_99; network input *)
    IN153 : BYTE;  (* at ECAT://node#1/Inputs0_1 Byte In (153)_3000_9A; network input *)
    IN154 : BYTE;  (* at ECAT://node#1/Inputs0_1 Byte In (154)_3000_9B; network input *)
    IN155 : BYTE;  (* at ECAT://node#1/Inputs0_1 Byte In (155)_3000_9C; network input *)
    IN156 : BYTE;  (* at ECAT://node#1/Inputs0_1 Byte In (156)_3000_9D; network input *)
    IN157 : BYTE;  (* at ECAT://node#1/Inputs0_1 Byte In (157)_3000_9E; network input *)
    IN158 : BYTE;  (* at ECAT://node#1/Inputs0_1 Byte In (158)_3000_9F; network input *)
    IN159 : BYTE;  (* at ECAT://node#1/Inputs0_1 Byte In (159)_3000_A0; network input *)
    IN160 : BYTE;  (* at ECAT://node#1/Inputs0_1 Byte In (160)_3000_A1; network input *)
    IN161 : BYTE;  (* at ECAT://node#1/Inputs0_1 Byte In (161)_3000_A2; network input *)
    IN162 : BYTE;  (* at ECAT://node#1/Inputs0_1 Byte In (162)_3000_A3; network input *)
    IN163 : BYTE;  (* at ECAT://node#1/Inputs0_1 Byte In (163)_3000_A4; network input *)
    IN164 : BYTE;  (* at ECAT://node#1/Inputs0_1 Byte In (164)_3000_A5; network input *)
    IN165 : BYTE;  (* at ECAT://node#1/Inputs0_1 Byte In (165)_3000_A6; network input *)
    IN166 : BYTE;  (* at ECAT://node#1/Inputs0_1 Byte In (166)_3000_A7; network input *)
    IN167 : BYTE;  (* at ECAT://node#1/Inputs0_1 Byte In (167)_3000_A8; network input *)
    IN168 : BYTE;  (* at ECAT://node#1/Inputs0_1 Byte In (168)_3000_A9; network input *)
    IN169 : BYTE;  (* at ECAT://node#1/Inputs0_1 Byte In (169)_3000_AA; network input *)
    IN170 : BYTE;  (* at ECAT://node#1/Inputs0_1 Byte In (170)_3000_AB; network input *)
    IN171 : BYTE;  (* at ECAT://node#1/Inputs0_1 Byte In (171)_3000_AC; network input *)
    IN172 : BYTE;  (* at ECAT://node#1/Inputs0_1 Byte In (172)_3000_AD; network input *)
    IN173 : BYTE;  (* at ECAT://node#1/Inputs0_1 Byte In (173)_3000_AE; network input *)
    IN174 : BYTE;  (* at ECAT://node#1/Inputs0_1 Byte In (174)_3000_AF; network input *)
    IN175 : BYTE;  (* at ECAT://node#1/Inputs0_1 Byte In (175)_3000_B0; network input *)
    IN176 : BYTE;  (* at ECAT://node#1/Inputs0_1 Byte In (176)_3000_B1; network input *)
    IN177 : BYTE;  (* at ECAT://node#1/Inputs0_1 Byte In (177)_3000_B2; network input *)
    IN178 : BYTE;  (* at ECAT://node#1/Inputs0_1 Byte In (178)_3000_B3; network input *)
    IN179 : BYTE;  (* at ECAT://node#1/Inputs0_1 Byte In (179)_3000_B4; network input *)
    IN180 : BYTE;  (* at ECAT://node#1/Inputs0_1 Byte In (180)_3000_B5; network input *)
    IN181 : BYTE;  (* at ECAT://node#1/Inputs0_1 Byte In (181)_3000_B6; network input *)
    IN182 : BYTE;  (* at ECAT://node#1/Inputs0_1 Byte In (182)_3000_B7; network input *)
    IN183 : BYTE;  (* at ECAT://node#1/Inputs0_1 Byte In (183)_3000_B8; network input *)
    IN184 : BYTE;  (* at ECAT://node#1/Inputs0_1 Byte In (184)_3000_B9; network input *)
    IN185 : BYTE;  (* at ECAT://node#1/Inputs0_1 Byte In (185)_3000_BA; network input *)
    IN186 : BYTE;  (* at ECAT://node#1/Inputs0_1 Byte In (186)_3000_BB; network input *)
    IN187 : BYTE;  (* at ECAT://node#1/Inputs0_1 Byte In (187)_3000_BC; network input *)
    IN188 : BYTE;  (* at ECAT://node#1/Inputs0_1 Byte In (188)_3000_BD; network input *)
    IN189 : BYTE;  (* at ECAT://node#1/Inputs0_1 Byte In (189)_3000_BE; network input *)
    IN190 : BYTE;  (* at ECAT://node#1/Inputs0_1 Byte In (190)_3000_BF; network input *)
    IN191 : BYTE;  (* at ECAT://node#1/Inputs0_1 Byte In (191)_3000_C0; network input *)
    IN192 : BYTE;  (* at ECAT://node#1/Inputs0_1 Byte In (192)_3000_C1; network input *)
    IN193 : BYTE;  (* at ECAT://node#1/Inputs0_1 Byte In (193)_3000_C2; network input *)
    IN194 : BYTE;  (* at ECAT://node#1/Inputs0_1 Byte In (194)_3000_C3; network input *)
    IN195 : BYTE;  (* at ECAT://node#1/Inputs0_1 Byte In (195)_3000_C4; network input *)
    IN196 : BYTE;  (* at ECAT://node#1/Inputs0_1 Byte In (196)_3000_C5; network input *)
    IN197 : BYTE;  (* at ECAT://node#1/Inputs0_1 Byte In (197)_3000_C6; network input *)
    IN198 : BYTE;  (* at ECAT://node#1/Inputs0_1 Byte In (198)_3000_C7; network input *)
    IN199 : BYTE;  (* at ECAT://node#1/Inputs0_1 Byte In (199)_3000_C8; network input *)
    IN200 : BYTE;  (* at ECAT://node#1/Inputs1_1 Byte In (200)_3001_01; network input *)
    IN201 : BYTE;  (* at ECAT://node#1/Inputs1_1 Byte In (201)_3001_02; network input *)
    IN202 : BYTE;  (* at ECAT://node#1/Inputs1_1 Byte In (202)_3001_03; network input *)
    IN203 : BYTE;  (* at ECAT://node#1/Inputs1_1 Byte In (203)_3001_04; network input *)
    IN204 : BYTE;  (* at ECAT://node#1/Inputs1_1 Byte In (204)_3001_05; network input *)
    IN205 : BYTE;  (* at ECAT://node#1/Inputs1_1 Byte In (205)_3001_06; network input *)
    IN206 : BYTE;  (* at ECAT://node#1/Inputs1_1 Byte In (206)_3001_07; network input *)
    IN207 : BYTE;  (* at ECAT://node#1/Inputs1_1 Byte In (207)_3001_08; network input *)
    IN208 : BYTE;  (* at ECAT://node#1/Inputs1_1 Byte In (208)_3001_09; network input *)
    IN209 : BYTE;  (* at ECAT://node#1/Inputs1_1 Byte In (209)_3001_0A; network input *)
    IN210 : BYTE;  (* at ECAT://node#1/Inputs1_1 Byte In (210)_3001_0B; network input *)
    IN211 : BYTE;  (* at ECAT://node#1/Inputs1_1 Byte In (211)_3001_0C; network input *)
    IN212 : BYTE;  (* at ECAT://node#1/Inputs1_1 Byte In (212)_3001_0D; network input *)
    IN213 : BYTE;  (* at ECAT://node#1/Inputs1_1 Byte In (213)_3001_0E; network input *)
    IN214 : BYTE;  (* at ECAT://node#1/Inputs1_1 Byte In (214)_3001_0F; network input *)
    IN215 : BYTE;  (* at ECAT://node#1/Inputs1_1 Byte In (215)_3001_10; network input *)
    IN216 : BYTE;  (* at ECAT://node#1/Inputs1_1 Byte In (216)_3001_11; network input *)
    IN217 : BYTE;  (* at ECAT://node#1/Inputs1_1 Byte In (217)_3001_12; network input *)
    IN218 : BYTE;  (* at ECAT://node#1/Inputs1_1 Byte In (218)_3001_13; network input *)
    IN219 : BYTE;  (* at ECAT://node#1/Inputs1_1 Byte In (219)_3001_14; network input *)
    IN220 : BYTE;  (* at ECAT://node#1/Inputs1_1 Byte In (220)_3001_15; network input *)
    IN221 : BYTE;  (* at ECAT://node#1/Inputs1_1 Byte In (221)_3001_16; network input *)
    IN222 : BYTE;  (* at ECAT://node#1/Inputs1_1 Byte In (222)_3001_17; network input *)
    IN223 : BYTE;  (* at ECAT://node#1/Inputs1_1 Byte In (223)_3001_18; network input *)
    IN224 : BYTE;  (* at ECAT://node#1/Inputs1_1 Byte In (224)_3001_19; network input *)
    IN225 : BYTE;  (* at ECAT://node#1/Inputs1_1 Byte In (225)_3001_1A; network input *)
    IN226 : BYTE;  (* at ECAT://node#1/Inputs1_1 Byte In (226)_3001_1B; network input *)
    IN227 : BYTE;  (* at ECAT://node#1/Inputs1_1 Byte In (227)_3001_1C; network input *)
    IN228 : BYTE;  (* at ECAT://node#1/Inputs1_1 Byte In (228)_3001_1D; network input *)
    IN229 : BYTE;  (* at ECAT://node#1/Inputs1_1 Byte In (229)_3001_1E; network input *)
    IN230 : BYTE;  (* at ECAT://node#1/Inputs1_1 Byte In (230)_3001_1F; network input *)
    IN231 : BYTE;  (* at ECAT://node#1/Inputs1_1 Byte In (231)_3001_20; network input *)
    IN232 : BYTE;  (* at ECAT://node#1/Inputs1_1 Byte In (232)_3001_21; network input *)
    IN233 : BYTE;  (* at ECAT://node#1/Inputs1_1 Byte In (233)_3001_22; network input *)
    IN234 : BYTE;  (* at ECAT://node#1/Inputs1_1 Byte In (234)_3001_23; network input *)
    IN235 : BYTE;  (* at ECAT://node#1/Inputs1_1 Byte In (235)_3001_24; network input *)
    IN236 : BYTE;  (* at ECAT://node#1/Inputs1_1 Byte In (236)_3001_25; network input *)
    IN237 : BYTE;  (* at ECAT://node#1/Inputs1_1 Byte In (237)_3001_26; network input *)
    IN238 : BYTE;  (* at ECAT://node#1/Inputs1_1 Byte In (238)_3001_27; network input *)
    IN239 : BYTE;  (* at ECAT://node#1/Inputs1_1 Byte In (239)_3001_28; network input *)
    IN240 : BYTE;  (* at ECAT://node#1/Inputs1_1 Byte In (240)_3001_29; network input *)
    IN241 : BYTE;  (* at ECAT://node#1/Inputs1_1 Byte In (241)_3001_2A; network input *)
    IN242 : BYTE;  (* at ECAT://node#1/Inputs1_1 Byte In (242)_3001_2B; network input *)
    IN243 : BYTE;  (* at ECAT://node#1/Inputs1_1 Byte In (243)_3001_2C; network input *)
    IN244 : BYTE;  (* at ECAT://node#1/Inputs1_1 Byte In (244)_3001_2D; network input *)
    IN245 : BYTE;  (* at ECAT://node#1/Inputs1_1 Byte In (245)_3001_2E; network input *)
    IN246 : BYTE;  (* at ECAT://node#1/Inputs1_1 Byte In (246)_3001_2F; network input *)
    IN247 : BYTE;  (* at ECAT://node#1/Inputs1_1 Byte In (247)_3001_30; network input *)
    IN248 : BYTE;  (* at ECAT://node#1/Inputs1_1 Byte In (248)_3001_31; network input *)
    IN249 : BYTE;  (* at ECAT://node#1/Inputs1_1 Byte In (249)_3001_32; network input *)
    IN250 : BYTE;  (* at ECAT://node#1/Inputs1_1 Byte In (250)_3001_33; network input *)
    IN251 : BYTE;  (* at ECAT://node#1/Inputs1_1 Byte In (251)_3001_34; network input *)
    IN252 : BYTE;  (* at ECAT://node#1/Inputs1_1 Byte In (252)_3001_35; network input *)
    IN253 : BYTE;  (* at ECAT://node#1/Inputs1_1 Byte In (253)_3001_36; network input *)
    IN254 : BYTE;  (* at ECAT://node#1/Inputs1_1 Byte In (254)_3001_37; network input *)
    IN255 : BYTE;  (* at ECAT://node#1/Inputs1_1 Byte In (255)_3001_38; network input *)
    R652 : UINT;  (* published *)
    M601 : BOOL;  (* published *)
    M602 : BOOL;  (* published *)
    M604 : BOOL;  (* published *)
    M603 : BOOL;  (* published *)
    M700 : BOOL;  (* published *)
    M800 : BOOL;  (* published *)
    M900 : BOOL;  (* published *)
    M1000 : BOOL;  (* published *)
    M1100 : BOOL;  (* published *)
    M1200 : BOOL;  (* published *)
    M1300 : BOOL;  (* published *)
    M1400 : BOOL;  (* published *)
    M1500 : BOOL;  (* published *)
    M1600 : BOOL;  (* published *)
    M1700 : BOOL;  (* published *)
    M1800 : BOOL;  (* published *)
    M1900 : BOOL;  (* published *)
    M2000 : BOOL;  (* published *)
    M2100 : BOOL;  (* published *)
    M2200 : BOOL;  (* published *)
    M2300 : BOOL;  (* published *)
    M2401 : BOOL;  (* published *)
    M2402 : BOOL;  (* published *)
    M2403 : BOOL;  (* published *)
    M2404 : BOOL;  (* published *)
    M2405 : BOOL;  (* published *)
    M2406 : BOOL;  (* published *)
    M2407 : BOOL;  (* published *)
    M2408 : BOOL;  (* published *)
    M2400 : BOOL;  (* published *)
    R652_Copy : UINT;  (* published *)
    M701 : BOOL;  (* published *)
    M702 : BOOL;  (* published *)
    M703 : BOOL;  (* published *)
    M704 : BOOL;  (* published *)
    M705 : BOOL;  (* published *)
    R752 : UINT;  (* published *)
    R805L : BYTE;  (* published *)
    R805H : BYTE;  (* published *)
    M801 : BOOL;  (* published *)
    M802 : BOOL;  (* published *)
    M804 : BOOL;  (* published *)
    M803 : BOOL;  (* published *)
    M805 : BOOL;  (* published *)
    M806 : BOOL;  (* published *)
    M807 : BOOL;  (* published *)
    M808 : BOOL;  (* published *)
    R852 : UINT;  (* published *)
    R905 : UINT;  (* published *)
    M901 : BOOL;  (* published *)
    M902 : BOOL;  (* published *)
    M904 : BOOL;  (* published *)
    M903 : BOOL;  (* published *)
    R952 : UINT;  (* published *)
    M1001 : BOOL;  (* published *)
    M1002 : BOOL;  (* published *)
    M1004 : BOOL;  (* published *)
    M1003 : BOOL;  (* published *)
    R1052 : UINT;  (* published *)
    M1101 : BOOL;  (* published *)
    M1102 : BOOL;  (* published *)
    M1104 : BOOL;  (* published *)
    M1105 : BOOL;  (* published *)
    M1103 : BOOL;  (* published *)
    R1152 : UINT;  (* published *)
    R1205 : REAL;  (* published *)
    R1207 : REAL;  (* published *)
    R1209 : REAL;  (* published *)
    R1211 : REAL;  (* published *)
    R1213 : REAL;  (* published *)
    R1215 : REAL;  (* published *)
    M1201 : BOOL;  (* published *)
    M1202 : BOOL;  (* published *)
    M1204 : BOOL;  (* published *)
    M1203 : BOOL;  (* published *)
    R1252 : UINT;  (* published *)
    R1305 : REAL;  (* published *)
    R1307 : REAL;  (* published *)
    R1309 : REAL;  (* published *)
    R1311 : REAL;  (* published *)
    R1313 : REAL;  (* published *)
    R1315 : REAL;  (* published *)
    R1317 : DINT;  (* published *)
    R1319L : BYTE;  (* published *)
    M1301 : BOOL;  (* published *)
    M1302 : BOOL;  (* published *)
    M1304 : BOOL;  (* published *)
    M1303 : BOOL;  (* published *)
    R1352 : UINT;  (* published *)
    R1417L : BYTE;  (* published *)
    R1405 : REAL;  (* published *)
    R1407 : REAL;  (* published *)
    R1409 : REAL;  (* published *)
    R1411 : REAL;  (* published *)
    R1413 : REAL;  (* published *)
    R1415 : REAL;  (* published *)
    R1417H : BYTE;  (* published *)
    M1401 : BOOL;  (* published *)
    M1402 : BOOL;  (* published *)
    M1403 : BOOL;  (* published *)
    M1404 : BOOL;  (* published *)
    M1405 : BOOL;  (* published *)
    M1406 : BOOL;  (* published *)
    R1452 : UINT;  (* published *)
    M1501 : BOOL;  (* published *)
    M1502 : BOOL;  (* published *)
    M1504 : BOOL;  (* published *)
    M1503 : BOOL;  (* published *)
    R1552 : UINT;  (* published *)
    R1565 : REAL;  (* published *)
    R1505L : BYTE;  (* published *)
    R1567L : BYTE;  (* published *)
    R1555 : REAL;  (* published *)
    R1557 : REAL;  (* published *)
    R1559 : REAL;  (* published *)
    R1561 : REAL;  (* published *)
    R1563 : REAL;  (* published *)
    M1601 : BOOL;  (* published *)
    M1602 : BOOL;  (* published *)
    M1604 : BOOL;  (* published *)
    M1605 : BOOL;  (* published *)
    M1606 : BOOL;  (* published *)
    M1603 : BOOL;  (* published *)
    R1613L : BYTE;  (* published *)
    R1652 : UINT;  (* published *)
    R1705L : BYTE;  (* published *)
    M1701 : BOOL;  (* published *)
    M1702 : BOOL;  (* published *)
    M1704 : BOOL;  (* published *)
    M1703 : BOOL;  (* published *)
    R1752 : UINT;  (* published *)
    R1763L : BYTE;  (* published *)
    R1755 : REAL;  (* published *)
    R1757 : REAL;  (* published *)
    R1759 : REAL;  (* published *)
    R1761 : REAL;  (* published *)
    M1801 : BOOL;  (* published *)
    M1802 : BOOL;  (* published *)
    M1804 : BOOL;  (* published *)
    M1803 : BOOL;  (* published *)
    R1852 : UINT;  (* published *)
    R1805 : REAL;  (* published *)
    R1807 : REAL;  (* published *)
    M1901 : BOOL;  (* published *)
    M1902 : BOOL;  (* published *)
    M1903 : BOOL;  (* published *)
    R1952 : UINT;  (* published *)
    R1955 : REAL;  (* published *)
    R1957 : REAL;  (* published *)
    R2005 : REAL;  (* published *)
    R2007 : REAL;  (* published *)
    M2001 : BOOL;  (* published *)
    M2002 : BOOL;  (* published *)
    M2004 : BOOL;  (* published *)
    M2003 : BOOL;  (* published *)
    R2052 : UINT;  (* published *)
    M2101 : BOOL;  (* published *)
    M2102 : BOOL;  (* published *)
    M2104 : BOOL;  (* published *)
    M2103 : BOOL;  (* published *)
    R2152 : UINT;  (* published *)
    R2155 : REAL;  (* published *)
    R2157 : REAL;  (* published *)
END_VAR
VAR_GLOBAL RETAIN
    R2205 : REAL;  (* published *)
    R2207 : REAL;  (* published *)
    R2209 : REAL;  (* published *)
    R2211 : REAL;  (* published *)
    R2213 : REAL;  (* published *)
    R2215 : REAL;  (* published *)
    R2217 : REAL;  (* published *)
    R2219 : REAL;  (* published *)
    R2221 : REAL;  (* published *)
    R2223 : REAL;  (* published *)
    R2225 : REAL;  (* published *)
    R2227 : REAL;  (* published *)
END_VAR
VAR_GLOBAL
    M2201 : BOOL;  (* published *)
    M2202 : BOOL;  (* published *)
    M2204 : BOOL;  (* published *)
    M2203 : BOOL;  (* published *)
    R2257 : UINT;  (* published *)
    M2301 : BOOL;  (* published *)
    M2302 : BOOL;  (* published *)
    M2304 : BOOL;  (* published *)
    M2303 : BOOL;  (* published *)
    R2357 : REAL;  (* published *)
    R2355 : REAL;  (* published *)
    R2359 : REAL;  (* published *)
    R2361 : REAL;  (* published *)
    R2363 : REAL;  (* published *)
    R2365 : REAL;  (* published *)
    R2367 : REAL;  (* published *)
    R2369 : REAL;  (* published *)
    R2371 : REAL;  (* published *)
    R2373 : REAL;  (* published *)
    R2375 : REAL;  (* published *)
    R2377 : REAL;  (* published *)
    R2457 : UINT;  (* published *)
    R2405 : REAL;  (* published *)
    R2407 : REAL;  (* published *)
    R2409 : REAL;  (* published *)
    R2411L : BYTE;  (* published *)
    R2411H : BYTE;  (* published *)
    R2412L : BYTE;  (* published *)
    R1605 : REAL;  (* published *)
    R1607 : REAL;  (* published *)
    R1609 : REAL;  (* published *)
    R1611 : REAL;  (* published *)
    R855 : REAL;  (* published *)
    R857 : REAL;  (* published *)
    R859 : REAL;  (* published *)
    R861 : REAL;  (* published *)
    R863 : REAL;  (* published *)
    R865 : REAL;  (* published *)
    R867 : REAL;  (* published *)
    R869 : REAL;  (* published *)
    R871 : REAL;  (* published *)
    R873 : REAL;  (* published *)
    R875 : REAL;  (* published *)
    R877 : REAL;  (* published *)
    R879L : BYTE;  (* published *)
    R879H : BYTE;  (* published *)
    R880L : BYTE;  (* published *)
    R880H : BYTE;  (* published *)
    R881L : BYTE;  (* published *)
    R881H : BYTE;  (* published *)
    R882L : BYTE;  (* published *)
    JointIN : ARRAY[0..5] OF REAL;  (* published *)
    CartestionReturn : ARRAY[0..5] OF REAL;  (* published *)
    CartestionIN : ARRAY[0..5] OF REAL;  (* published *)
    JointReturn : ARRAY[0..5] OF REAL;  (* published *)
END_VAR

PROGRAM program0
VAR
    WriteTool : RC_WriteToolData;
    MCPower : RC_EnableRobot;
    ReadTool : RC_ReadToolData;
    MoveA : RC_MoveAxesAbsolute;
    ReadActPosition : RC_ReadActualPosition;
    W1 : INT;
    Lifesign : ARRAY[0..1] OF BYTE;
    TooNoIN : BYTE;
    ToolData_IN : ARRAY[0..5] OF REAL;
    TooNo_IN : BYTE;
    MoveLine : RC_MoveLinearAbsolute;
    MoveDirect : RC_MoveDirectAbsolute;
    ROBOT_STATE1 : 机器人状态反馈1;
    ROBOT_STATE2 : 机器人状态反馈2;
    ROBOT_STATE3 : 机器人状态反馈3;
    ROBOT_STATE4 : 机器人状态反馈4;
    STEP1 : UINT;
    START : BOOL;
    关节初始位置 : ARRAY[0..5] OF REAL;
    笛卡尔初始位置 : ARRAY[0..5] OF REAL;
    JOint_in : ARRAY[0..5] OF REAL;
    Cartesian_in : ARRAY[0..5] OF REAL;
    调试 : BOOL;
    调试1 : BOOL;
    调试2 : BOOL;
    调试3 : BOOL;
    自动运行 : BOOL;
    STEP2 : UINT;
    START1 : BOOL;
    ROBOT_MotionCount : UDINT;
    Count_Buffer : UDINT;
    count_Done : BOOL;
    GroupReset : RC_GroupReset;
    GroupStop : RC_GroupStop;
    ChangeSpeedOverride : RC_ChangeSpeedOverride;
    GroupContinue : RC_GroupContinue;
    GroupInterrupt : RC_GroupInterrupt;
    WriteFrameData : RC_WriteFrameData;
    ReadFrameData : RC_ReadFrameData;
    WriteLoadData : RC_WriteLoadData;
    ReadLoadData : RC_ReadLoadData;
    WriteRobotRerenceDynamics : RC_WriteRobotReferenceDynamics;
    ReadRobotRerfrenceDynamics : RC_ReadRobotReferenceDynamics;
    WriteRobotLimits : RC_WriteRobotSwLimits;
    ReadRobotLimits : RC_ReadRobotSwLimits;
    WriteRobotDefaultDynamic : RC_WriteRobotDefaultDynamic;
    ReadRobotDefaultDynamic : RC_ReadRobotDefaultDynamic;
    CartesionFromJoint : RC_CartesionFromJoint;
    JointFromCartesion : RC_JointFromCartesion;
    ECTDataTransion : RC_ECTDataTransion;
    M1904 : BOOL;
    GroupJog : RC_GroupJog;
    ABC : _sTimer;
    DFG : _sTimer;
    EDF : _sTimer;
    done : BOOL;
    done1 : BOOL;
    done2 : BOOL;
    test1 : BOOL;
    test2 : BOOL;
    test3 : BOOL;
    test4 : BOOL;
    JKL : _sTimer;
    done3 : BOOL;
    ACB : _sTimer;
    DGF : _sTimer;
    EFD : _sTimer;
    JLK : _sTimer;
    ZXC : _sTimer;
    done4 : BOOL;
    ZCX : _sTimer;
    done5 : BOOL;
    CXZ : _sTimer;
    done6 : BOOL;
    done7 : BOOL;
    XCZ : _sTimer;
    done8 : BOOL;
    CZX : _sTimer;
    done9 : BOOL;
    XCV : _sTimer;
    done10 : BOOL;
END_VAR
VAR_EXTERNAL
    M0 : BOOL;
    M1 : BOOL;
    M2 : BOOL;
    M3 : BOOL;
    M100 : BOOL;
    M101 : BOOL;
    M201 : BOOL;
    M202 : BOOL;
    M203 : BOOL;
    R218L : BYTE;
    R205 : REAL;
    R207 : REAL;
    R209 : REAL;
    R211 : REAL;
    R213 : REAL;
    R215 : REAL;
    R252 : UINT;
    R218 : UINT;
    M102 : BOOL;
    M103 : BOOL;
    R160 : REAL;
    R162 : REAL;
    R164 : REAL;
    R166 : REAL;
    R168 : REAL;
    R170 : REAL;
    R152 : UINT;
    M200 : BOOL;
    R105L : BYTE;
    M300 : BOOL;
    M301 : BOOL;
    M302 : BOOL;
    M303 : BOOL;
    M304 : BOOL;
    M305 : BOOL;
    M306 : BOOL;
    R352 : UINT;
    R317 : REAL;
    R319 : REAL;
    R305 : REAL;
    R307 : REAL;
    R309 : REAL;
    R311 : REAL;
    R312 : REAL;
    R313 : REAL;
    R315 : REAL;
    R325L : BYTE;
    R12 : UINT;
    R425L : BYTE;
    R417 : REAL;
    R419 : REAL;
    R405 : REAL;
    R407 : REAL;
    R409 : REAL;
    R411 : REAL;
    R413 : REAL;
    R415 : REAL;
    M401 : BOOL;
    M402 : BOOL;
    M404 : BOOL;
    M405 : BOOL;
    M406 : BOOL;
    M403 : BOOL;
    R452 : UINT;
    M500 : BOOL;
    M400 : BOOL;
    R525L : BYTE;
    R525H : BYTE;
    R517 : REAL;
    R519 : REAL;
    R505 : REAL;
    R507 : REAL;
    R509 : REAL;
    R511 : REAL;
    R513 : REAL;
    R515 : REAL;
    M501 : BOOL;
    M502 : BOOL;
    M503 : BOOL;
    M504 : BOOL;
    M505 : BOOL;
    M506 : BOOL;
    R552 : UINT;
    Robot_Header : ARRAY[0..5] OF BYTE;
    B0 : BOOL;
    Robot_CMDHeader : ARRAY[0..9] OF BYTE;
    Robot_CMDPayload : ARRAY[0..119] OF BYTE;
    Robot_CyclicData : ARRAY[0..118] OF BYTE;
    ROBOT_J1 : REAL;
    ROBOT_J2 : REAL;
    ROBOT_J3 : REAL;
    ROBOT_J4 : REAL;
    ROBOT_J5 : REAL;
    ROBOT_J6 : REAL;
    TOOLDATA_X : REAL;
    TOOLDATA_Y : REAL;
    TOOLDATA_Z : REAL;
    TOOLDATA_RZ : REAL;
    TOOLDATA_RY : REAL;
    TOOLDATA_RX : REAL;
    ROBOT_TOOLNO : BYTE;
    ROBOT_FRAMENO : BYTE;
    B1 : BOOL;
    B3 : BOOL;
    B4 : BOOL;
    B5 : BOOL;
    B6 : BOOL;
    B2 : BOOL;
    B7 : BOOL;
    B8 : BOOL;
    B9 : BOOL;
    B10 : BOOL;
    B11 : BOOL;
    Joint_Move : BOOL;
    Cartesian_Move : BOOL;
    ECT_OUT : ARRAY[0..255] OF BYTE;
    ECT_IN : ARRAY[0..255] OF BYTE;
    RobotCMD : UINT;
    RobotCMDLength : BYTE;
    RobotCMDState : BYTE;
    RobotCMDErrorcode : BYTE;
    R217L : BOOL;
    R217H : BOOL;
    R172L : BOOL;
    R172H : BOOL;
    R173L : BOOL;
    M600 : BOOL;
    Out0 : BYTE;
    Out1 : BYTE;
    IN6 : BYTE;
    Out255 : BYTE;
    R652 : UINT;
    M601 : BOOL;
    M602 : BOOL;
    M604 : BOOL;
    M603 : BOOL;
    M701 : BOOL;
    M702 : BOOL;
    M704 : BOOL;
    M705 : BOOL;
    M703 : BOOL;
    R752 : UINT;
    M700 : BOOL;
    M800 : BOOL;
    M801 : BOOL;
    M802 : BOOL;
    M803 : BOOL;
    M804 : BOOL;
    M805 : BOOL;
    M806 : BOOL;
    M807 : BOOL;
    M808 : BOOL;
    R852 : UINT;
    R805L : BYTE;
    R805H : BYTE;
    M900 : BOOL;
    M901 : BOOL;
    M902 : BOOL;
    M904 : BOOL;
    M903 : BOOL;
    R952 : UINT;
    R905 : UINT;
    M1000 : BOOL;
    M1001 : BOOL;
    M1002 : BOOL;
    M1004 : BOOL;
    M1003 : BOOL;
    R1052 : UINT;
    M1100 : BOOL;
    M1101 : BOOL;
    M1102 : BOOL;
    M1104 : BOOL;
    M1105 : BOOL;
    M1103 : BOOL;
    R1152 : UINT;
    M1201 : BOOL;
    M1202 : BOOL;
    M1204 : BOOL;
    M1203 : BOOL;
    R1252 : UINT;
    M1200 : BOOL;
    M1300 : BOOL;
    M1301 : BOOL;
    M1302 : BOOL;
    M1304 : BOOL;
    M1303 : BOOL;
    R1352 : UINT;
    M1400 : BOOL;
    R1417L : BYTE;
    R1405 : REAL;
    R1407 : REAL;
    R1409 : REAL;
    R1411 : REAL;
    R1413 : REAL;
    R1415 : REAL;
    M1401 : BOOL;
    M1402 : BOOL;
    M1404 : BOOL;
    M1405 : BOOL;
    M1406 : BOOL;
    M1403 : BOOL;
    R1452 : UINT;
    M1500 : BOOL;
    M1501 : BOOL;
    M1502 : BOOL;
    M1504 : BOOL;
    M1503 : BOOL;
    R1552 : UINT;
    R1555 : REAL;
    R1557 : REAL;
    R1559 : REAL;
    R1561 : REAL;
    R1563 : REAL;
    R1565 : REAL;
    R1505L : BYTE;
    M1600 : BOOL;
    M1601 : BOOL;
    M1602 : BOOL;
    M1604 : BOOL;
    M1605 : BOOL;
    M1606 : BOOL;
    M1603 : BOOL;
    R1652 : UINT;
    R1613L : BYTE;
    R1605 : REAL;
    R1607 : REAL;
    R1609 : REAL;
    R1611 : REAL;
    M1700 : BOOL;
    R1705L : BYTE;
    M1701 : BOOL;
    M1702 : BOOL;
    M1704 : BOOL;
    M1703 : BOOL;
    R1752 : UINT;
    R1763L : BYTE;
    R1755 : REAL;
    R1757 : REAL;
    R1759 : REAL;
    R1761 : REAL;
    M1800 : BOOL;
    R1805 : REAL;
    R1807 : REAL;
    M1801 : BOOL;
    M1802 : BOOL;
    M1804 : BOOL;
    M1803 : BOOL;
    R1852 : UINT;
    M1900 : BOOL;
    M1901 : BOOL;
    M1902 : BOOL;
    M1903 : BOOL;
    R1952 : UINT;
    M2000 : BOOL;
    R2005 : REAL;
    R2007 : REAL;
    M2001 : BOOL;
    M2002 : BOOL;
    M2004 : BOOL;
    M2003 : BOOL;
    R2052 : UINT;
    M2100 : BOOL;
    M2101 : BOOL;
    M2102 : BOOL;
    M2104 : BOOL;
    M2103 : BOOL;
    R2152 : UINT;
    R2155 : REAL;
    R2157 : REAL;
    M2200 : BOOL;
    R2205 : REAL;
    R2207 : REAL;
    R2209 : REAL;
    R2211 : REAL;
    R2213 : REAL;
    R2215 : REAL;
    R2217 : REAL;
    R2219 : REAL;
    R2221 : REAL;
    R2223 : REAL;
    R2225 : REAL;
    R2227 : REAL;
    M2201 : BOOL;
    M2202 : BOOL;
    M2204 : BOOL;
    M2203 : BOOL;
    R2257 : UINT;
    M2300 : BOOL;
    M2301 : BOOL;
    M2302 : BOOL;
    M2304 : BOOL;
    M2303 : BOOL;
    R2357 : REAL;
    R2405 : REAL;
    R2407 : REAL;
    R2409 : REAL;
    R2411L : BYTE;
    R2411H : BYTE;
    R2412L : BYTE;
    M2400 : BOOL;
    M2401 : BOOL;
    M2402 : BOOL;
    M2404 : BOOL;
    M2405 : BOOL;
    M2406 : BOOL;
    M2407 : BOOL;
    M2408 : BOOL;
    M2403 : BOOL;
    R2457 : UINT;
    R2355 : REAL;
    R2359 : REAL;
    R2361 : REAL;
    R2363 : REAL;
    R2365 : REAL;
    R2367 : REAL;
    R2369 : REAL;
    R2371 : REAL;
    R2373 : REAL;
    R2375 : REAL;
    R2377 : REAL;
END_VAR
VAR
    _e1 : R_TRIG;
    _e2 : F_TRIG;
    _e3 : R_TRIG;
    _e4 : R_TRIG;
    _e5 : R_TRIG;
    _e6 : R_TRIG;
    _e7 : R_TRIG;
    _e8 : R_TRIG;
    _e9 : R_TRIG;
    _e10 : R_TRIG;
    _e11 : R_TRIG;
    _e12 : R_TRIG;
    _e13 : R_TRIG;
    _e14 : R_TRIG;
    _e15 : R_TRIG;
    _e16 : R_TRIG;
    _e17 : R_TRIG;
    _e18 : R_TRIG;
    _e19 : R_TRIG;
    _e20 : R_TRIG;
    _e21 : R_TRIG;
    _e22 : R_TRIG;
    _e23 : R_TRIG;
    _e24 : R_TRIG;
    _e25 : R_TRIG;
    _e26 : R_TRIG;
    _e27 : R_TRIG;
    _e28 : F_TRIG;
END_VAR

(* Section Main: ladder, written here as Structured Text *)

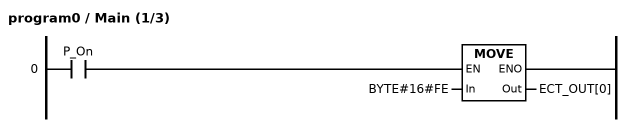
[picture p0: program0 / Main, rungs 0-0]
(* Rung 0 *)
IF P_On THEN ECT_OUT[0] := BYTE#16#FE; END_IF;

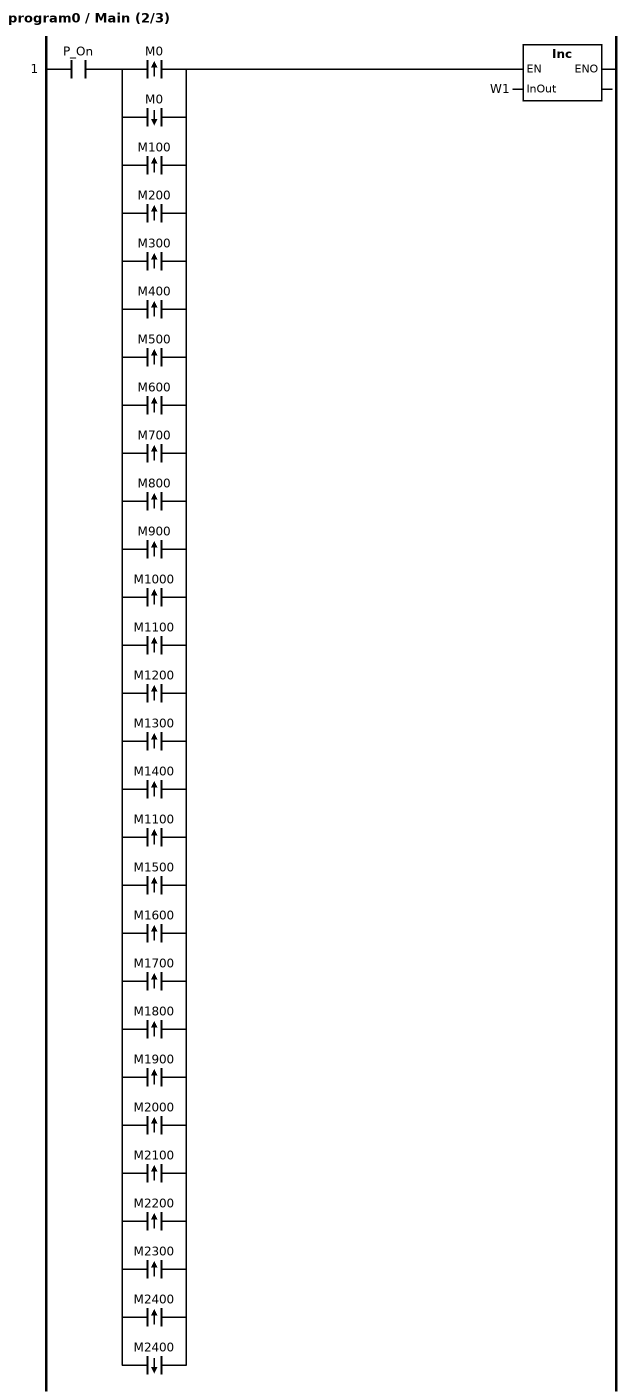
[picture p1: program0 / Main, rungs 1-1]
(* Rung 1 *)
_e1(CLK := M0);
_e2(CLK := M0);
_e3(CLK := M100);
_e4(CLK := M200);
_e5(CLK := M300);
_e6(CLK := M400);
_e7(CLK := M500);
_e8(CLK := M600);
_e9(CLK := M700);
_e10(CLK := M800);
_e11(CLK := M900);
_e12(CLK := M1000);
_e13(CLK := M1100);
_e14(CLK := M1200);
_e15(CLK := M1300);
_e16(CLK := M1400);
_e17(CLK := M1100);
_e18(CLK := M1500);
_e19(CLK := M1600);
_e20(CLK := M1700);
_e21(CLK := M1800);
_e22(CLK := M1900);
_e23(CLK := M2000);
_e24(CLK := M2100);
_e25(CLK := M2200);
_e26(CLK := M2300);
_e27(CLK := M2400);
_e28(CLK := M2400);
IF P_On AND (_e1.Q OR _e2.Q OR _e3.Q OR _e4.Q OR _e5.Q OR _e6.Q OR _e7.Q OR _e8.Q OR _e9.Q OR _e10.Q OR _e11.Q OR _e12.Q OR _e13.Q OR _e14.Q OR _e15.Q OR _e16.Q OR _e17.Q OR _e18.Q OR _e19.Q OR _e20.Q OR _e21.Q OR _e22.Q OR _e23.Q OR _e24.Q OR _e25.Q OR _e26.Q OR _e27.Q OR _e28.Q) THEN
    Inc(InOut := W1);
END_IF;

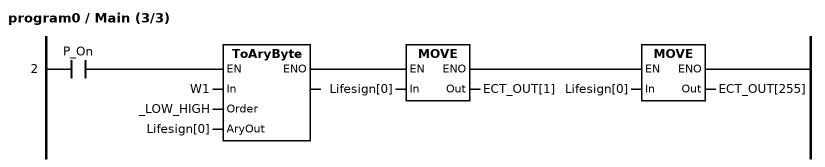
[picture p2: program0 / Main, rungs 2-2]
(* Rung 2 *)
IF P_On THEN
    ToAryByte(In := W1, Order := _LOW_HIGH, AryOut := Lifesign[0]);
    ECT_OUT[1] := Lifesign[0];
    ECT_OUT[255] := Lifesign[0];
END_IF;

(* Section Main1: ladder, written here as Structured Text *)

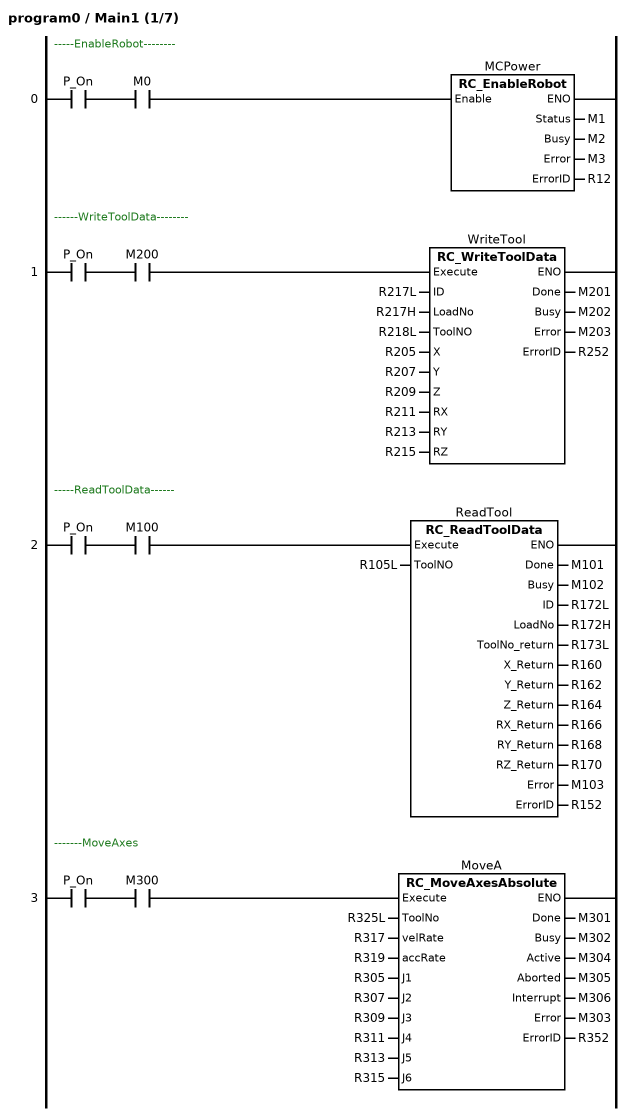
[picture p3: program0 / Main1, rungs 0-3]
(* Rung 0: -----EnableRobot-------- *)
MCPower(Enable := P_On AND M0, Status => M1, Busy => M2, Error => M3, ErrorID => R12);
(* Rung 1: ------WriteToolData-------- *)
WriteTool(Execute := P_On AND M200, ID := R217L, LoadNo := R217H, ToolNO := R218L, X := R205, Y := R207, Z := R209, RX := R211, RY := R213, RZ := R215, Done => M201, Busy => M202, Error => M203, ErrorID => R252);
(* Rung 2: -----ReadToolData------ *)
ReadTool(Execute := P_On AND M100, ToolNO := R105L, Done => M101, Busy => M102, ID => R172L, LoadNo => R172H, ToolNo_return => R173L, X_Return => R160, Y_Return => R162, Z_Return => R164, RX_Return => R166, RY_Return => R168, RZ_Return => R170, Error => M103, ErrorID => R152);
(* Rung 3: -------MoveAxes *)
MoveA(Execute := P_On AND M300, ToolNo := R325L, velRate := R317, accRate := R319, J1 := R305, J2 := R307, J3 := R309, J4 := R311, J5 := R313, J6 := R315, Done => M301, Busy => M302, Active => M304, Aborted => M305, Interrupt => M306, Error => M303, ErrorID => R352);

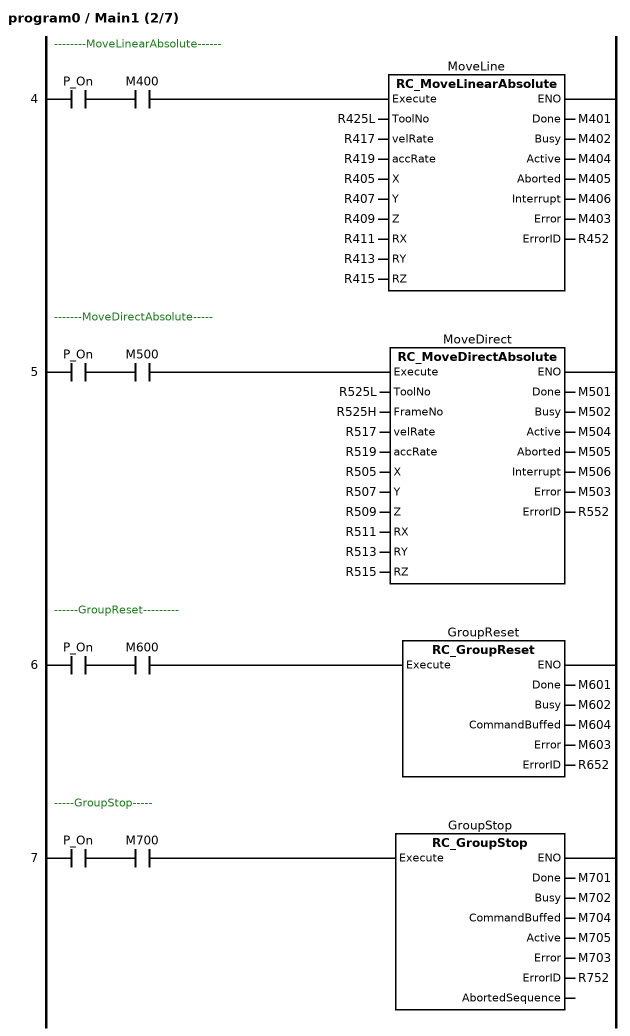
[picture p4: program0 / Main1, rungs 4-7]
(* Rung 4: --------MoveLinearAbsolute------ *)
MoveLine(Execute := P_On AND M400, ToolNo := R425L, velRate := R417, accRate := R419, X := R405, Y := R407, Z := R409, RX := R411, RY := R413, RZ := R415, Done => M401, Busy => M402, Active => M404, Aborted => M405, Interrupt => M406, Error => M403, ErrorID => R452);
(* Rung 5: -------MoveDirectAbsolute----- *)
MoveDirect(Execute := P_On AND M500, ToolNo := R525L, FrameNo := R525H, velRate := R517, accRate := R519, X := R505, Y := R507, Z := R509, RX := R511, RY := R513, RZ := R515, Done => M501, Busy => M502, Active => M504, Aborted => M505, Interrupt => M506, Error => M503, ErrorID => R552);
(* Rung 6: ------GroupReset--------- *)
GroupReset(Execute := P_On AND M600, Done => M601, Busy => M602, CommandBuffed => M604, Error => M603, ErrorID => R652);
(* Rung 7: -----GroupStop----- *)
GroupStop(Execute := P_On AND M700, Done => M701, Busy => M702, CommandBuffed => M704, Active => M705, Error => M703, ErrorID => R752);

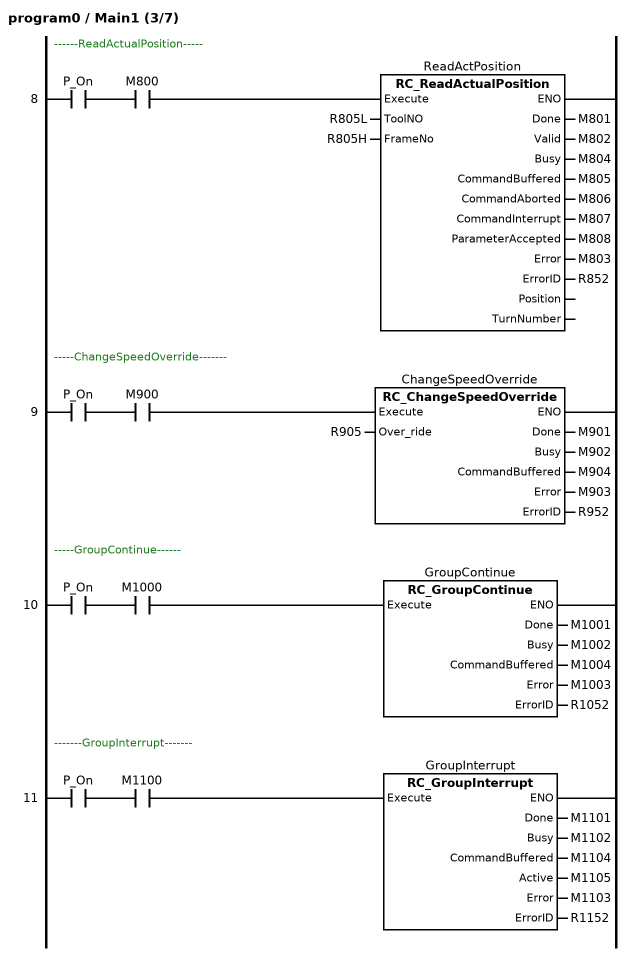
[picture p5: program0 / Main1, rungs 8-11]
(* Rung 8: ------ReadActualPosition----- *)
ReadActPosition(Execute := P_On AND M800, ToolNO := R805L, FrameNo := R805H, Done => M801, Valid => M802, Busy => M804, CommandBuffered => M805, CommandAborted => M806, CommandInterrupt => M807, ParameterAccepted => M808, Error => M803, ErrorID => R852);
(* Rung 9: -----ChangeSpeedOverride------- *)
ChangeSpeedOverride(Execute := P_On AND M900, Over_ride := R905, Done => M901, Busy => M902, CommandBuffered => M904, Error => M903, ErrorID => R952);
(* Rung 10: -----GroupContinue------ *)
GroupContinue(Execute := P_On AND M1000, Done => M1001, Busy => M1002, CommandBuffered => M1004, Error => M1003, ErrorID => R1052);
(* Rung 11: -------GroupInterrupt------- *)
GroupInterrupt(Execute := P_On AND M1100, Done => M1101, Busy => M1102, CommandBuffered => M1104, Active => M1105, Error => M1103, ErrorID => R1152);

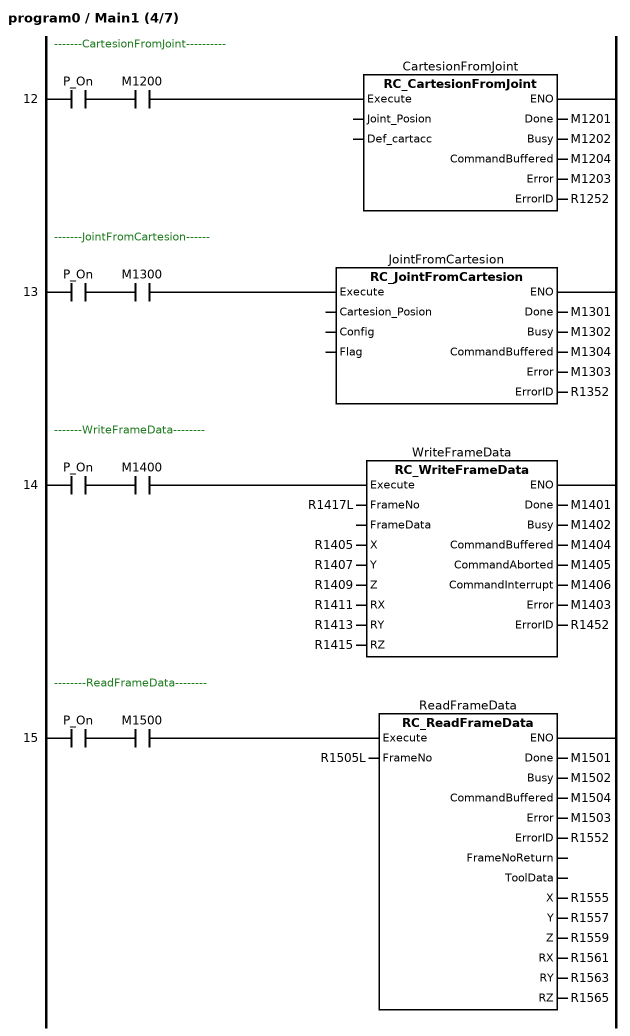
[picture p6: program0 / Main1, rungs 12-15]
(* Rung 12: -------CartesionFromJoint---------- *)
CartesionFromJoint(Execute := P_On AND M1200, Done => M1201, Busy => M1202, CommandBuffered => M1204, Error => M1203, ErrorID => R1252);
(* Rung 13: -------JointFromCartesion------ *)
JointFromCartesion(Execute := P_On AND M1300, Done => M1301, Busy => M1302, CommandBuffered => M1304, Error => M1303, ErrorID => R1352);
(* Rung 14: -------WriteFrameData-------- *)
WriteFrameData(Execute := P_On AND M1400, FrameNo := R1417L, X := R1405, Y := R1407, Z := R1409, RX := R1411, RY := R1413, RZ := R1415, Done => M1401, Busy => M1402, CommandBuffered => M1404, CommandAborted => M1405, CommandInterrupt => M1406, Error => M1403, ErrorID => R1452);
(* Rung 15: --------ReadFrameData-------- *)
ReadFrameData(Execute := P_On AND M1500, FrameNo := R1505L, Done => M1501, Busy => M1502, CommandBuffered => M1504, Error => M1503, ErrorID => R1552, X => R1555, Y => R1557, Z => R1559, RX => R1561, RY => R1563, RZ => R1565);

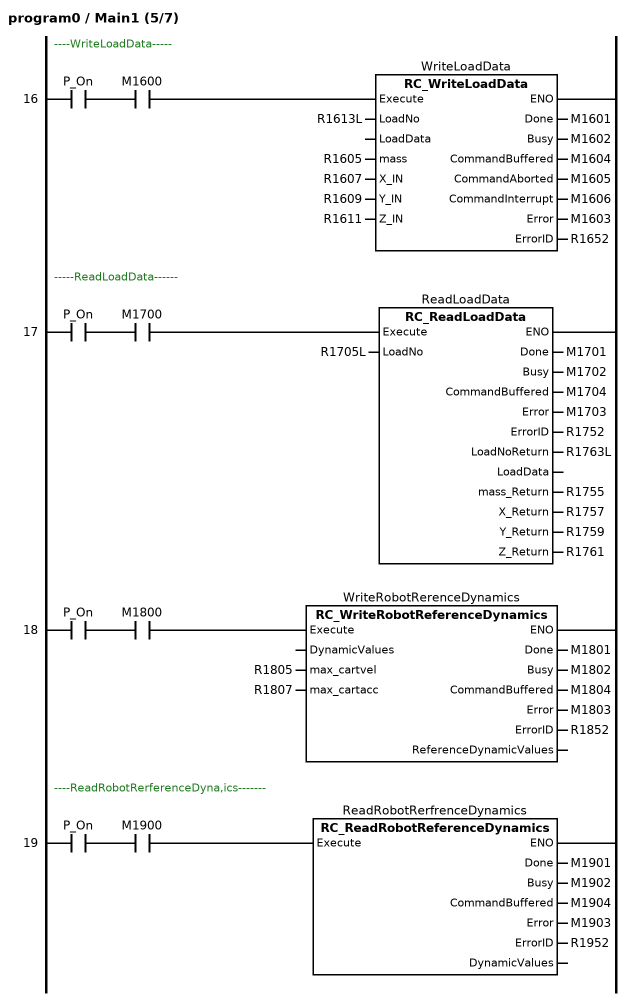
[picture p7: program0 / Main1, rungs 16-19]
(* Rung 16: ----WriteLoadData----- *)
WriteLoadData(Execute := P_On AND M1600, LoadNo := R1613L, mass := R1605, X_IN := R1607, Y_IN := R1609, Z_IN := R1611, Done => M1601, Busy => M1602, CommandBuffered => M1604, CommandAborted => M1605, CommandInterrupt => M1606, Error => M1603, ErrorID => R1652);
(* Rung 17: -----ReadLoadData------ *)
ReadLoadData(Execute := P_On AND M1700, LoadNo := R1705L, Done => M1701, Busy => M1702, CommandBuffered => M1704, Error => M1703, ErrorID => R1752, LoadNoReturn => R1763L, mass_Return => R1755, X_Return => R1757, Y_Return => R1759, Z_Return => R1761);
(* Rung 18 *)
WriteRobotRerenceDynamics(Execute := P_On AND M1800, max_cartvel := R1805, max_cartacc := R1807, Done => M1801, Busy => M1802, CommandBuffered => M1804, Error => M1803, ErrorID => R1852);
(* Rung 19: ----ReadRobotRerferenceDyna,ics------- *)
ReadRobotRerfrenceDynamics(Execute := P_On AND M1900, Done => M1901, Busy => M1902, CommandBuffered => M1904, Error => M1903, ErrorID => R1952);

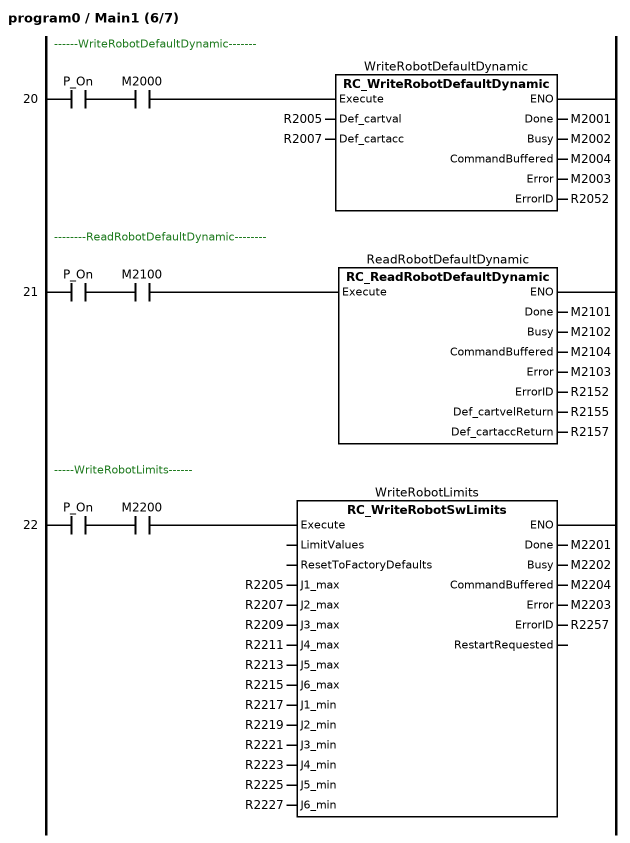
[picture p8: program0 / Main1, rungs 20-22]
(* Rung 20: ------WriteRobotDefaultDynamic------- *)
WriteRobotDefaultDynamic(Execute := P_On AND M2000, Def_cartval := R2005, Def_cartacc := R2007, Done => M2001, Busy => M2002, CommandBuffered => M2004, Error => M2003, ErrorID => R2052);
(* Rung 21: --------ReadRobotDefaultDynamic-------- *)
ReadRobotDefaultDynamic(Execute := P_On AND M2100, Done => M2101, Busy => M2102, CommandBuffered => M2104, Error => M2103, ErrorID => R2152, Def_cartvelReturn => R2155, Def_cartaccReturn => R2157);
(* Rung 22: -----WriteRobotLimits------ *)
WriteRobotLimits(Execute := P_On AND M2200, J1_max := R2205, J2_max := R2207, J3_max := R2209, J4_max := R2211, J5_max := R2213, J6_max := R2215, J1_min := R2217, J2_min := R2219, J3_min := R2221, J4_min := R2223, J5_min := R2225, J6_min := R2227, Done => M2201, Busy => M2202, CommandBuffered => M2204, Error => M2203, ErrorID => R2257);

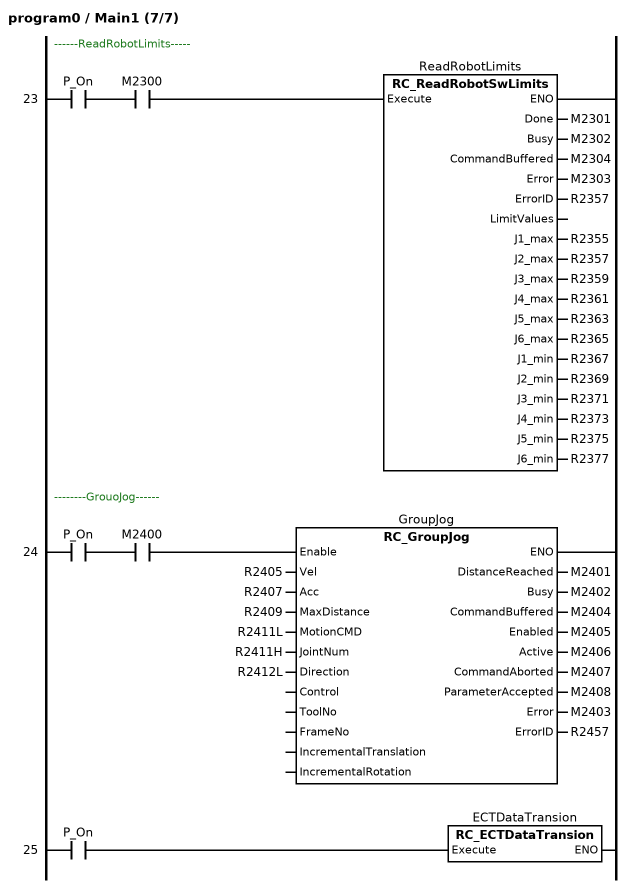
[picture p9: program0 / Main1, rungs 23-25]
(* Rung 23: ------ReadRobotLimits----- *)
ReadRobotLimits(Execute := P_On AND M2300, Done => M2301, Busy => M2302, CommandBuffered => M2304, Error => M2303, ErrorID => R2357, J1_max => R2355, J2_max => R2357, J3_max => R2359, J4_max => R2361, J5_max => R2363, J6_max => R2365, J1_min => R2367, J2_min => R2369, J3_min => R2371, J4_min => R2373, J5_min => R2375, J6_min => R2377);
(* Rung 24: --------GrouoJog------ *)
GroupJog(Enable := P_On AND M2400, Vel := R2405, Acc := R2407, MaxDistance := R2409, MotionCMD := R2411L, JointNum := R2411H, Direction := R2412L, DistanceReached => M2401, Busy => M2402, CommandBuffered => M2404, Enabled => M2405, Active => M2406, CommandAborted => M2407, ParameterAccepted => M2408, Error => M2403, ErrorID => R2457);
(* Rung 25 *)
ECTDataTransion(Execute := P_On);

(* Section cyclicdata: ladder, written here as Structured Text *)

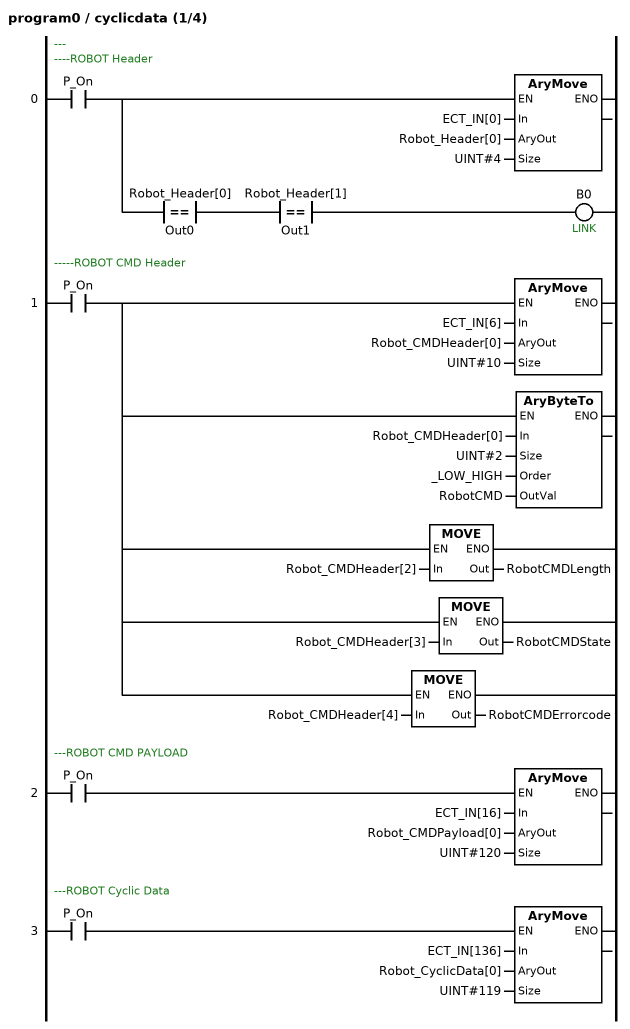
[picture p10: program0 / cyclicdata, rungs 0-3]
(* Rung 0: --- / ----ROBOT Header *)
IF P_On THEN AryMove(In := ECT_IN[0], AryOut := Robot_Header[0], Size := UINT#4); END_IF;
B0 := P_On AND (Robot_Header[0] = Out0) AND (Robot_Header[1] = Out1);
(* Rung 1: -----ROBOT CMD Header *)
IF P_On THEN
    AryMove(In := ECT_IN[6], AryOut := Robot_CMDHeader[0], Size := UINT#10);
    AryByteTo(In := Robot_CMDHeader[0], Size := UINT#2, Order := _LOW_HIGH, OutVal := RobotCMD);
    RobotCMDLength := Robot_CMDHeader[2];
    RobotCMDState := Robot_CMDHeader[3];
    RobotCMDErrorcode := Robot_CMDHeader[4];
END_IF;
(* Rung 2: ---ROBOT CMD PAYLOAD *)
IF P_On THEN AryMove(In := ECT_IN[16], AryOut := Robot_CMDPayload[0], Size := UINT#120); END_IF;
(* Rung 3: ---ROBOT Cyclic Data *)
IF P_On THEN AryMove(In := ECT_IN[136], AryOut := Robot_CyclicData[0], Size := UINT#119); END_IF;

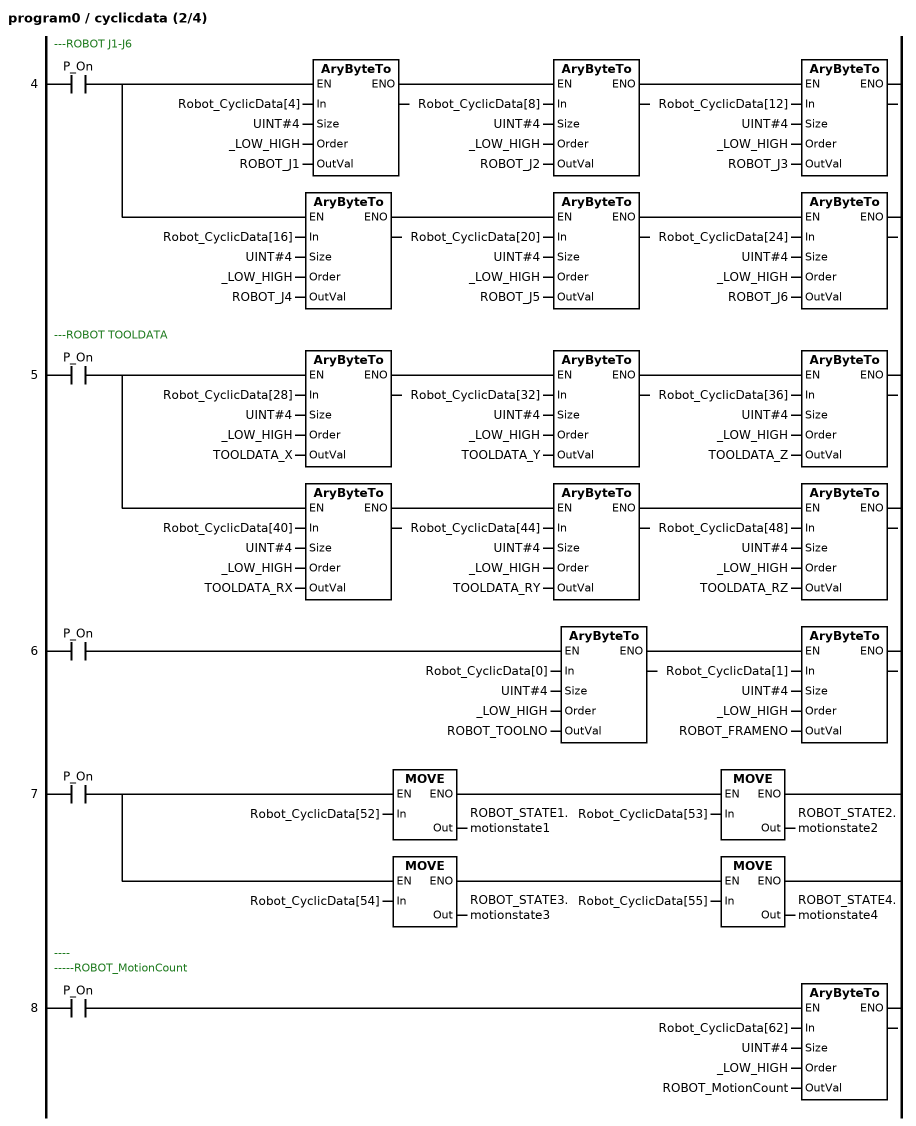
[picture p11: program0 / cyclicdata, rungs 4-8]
(* Rung 4: ---ROBOT J1-J6 *)
IF P_On THEN
    AryByteTo(In := Robot_CyclicData[4], Size := UINT#4, Order := _LOW_HIGH, OutVal := ROBOT_J1);
    AryByteTo(In := Robot_CyclicData[8], Size := UINT#4, Order := _LOW_HIGH, OutVal := ROBOT_J2);
    AryByteTo(In := Robot_CyclicData[12], Size := UINT#4, Order := _LOW_HIGH, OutVal := ROBOT_J3);
    AryByteTo(In := Robot_CyclicData[16], Size := UINT#4, Order := _LOW_HIGH, OutVal := ROBOT_J4);
    AryByteTo(In := Robot_CyclicData[20], Size := UINT#4, Order := _LOW_HIGH, OutVal := ROBOT_J5);
    AryByteTo(In := Robot_CyclicData[24], Size := UINT#4, Order := _LOW_HIGH, OutVal := ROBOT_J6);
END_IF;
(* Rung 5: ---ROBOT TOOLDATA *)
IF P_On THEN
    AryByteTo(In := Robot_CyclicData[28], Size := UINT#4, Order := _LOW_HIGH, OutVal := TOOLDATA_X);
    AryByteTo(In := Robot_CyclicData[32], Size := UINT#4, Order := _LOW_HIGH, OutVal := TOOLDATA_Y);
    AryByteTo(In := Robot_CyclicData[36], Size := UINT#4, Order := _LOW_HIGH, OutVal := TOOLDATA_Z);
    AryByteTo(In := Robot_CyclicData[40], Size := UINT#4, Order := _LOW_HIGH, OutVal := TOOLDATA_RX);
    AryByteTo(In := Robot_CyclicData[44], Size := UINT#4, Order := _LOW_HIGH, OutVal := TOOLDATA_RY);
    AryByteTo(In := Robot_CyclicData[48], Size := UINT#4, Order := _LOW_HIGH, OutVal := TOOLDATA_RZ);
END_IF;
(* Rung 6 *)
IF P_On THEN
    AryByteTo(In := Robot_CyclicData[0], Size := UINT#4, Order := _LOW_HIGH, OutVal := ROBOT_TOOLNO);
    AryByteTo(In := Robot_CyclicData[1], Size := UINT#4, Order := _LOW_HIGH, OutVal := ROBOT_FRAMENO);
END_IF;
(* Rung 7 *)
IF P_On THEN
    ROBOT_STATE1.motionstate1 := Robot_CyclicData[52];
    ROBOT_STATE2.motionstate2 := Robot_CyclicData[53];
    ROBOT_STATE3.motionstate3 := Robot_CyclicData[54];
    ROBOT_STATE4.motionstate4 := Robot_CyclicData[55];
END_IF;
(* Rung 8: ---- / -----ROBOT_MotionCount *)
IF P_On THEN
    AryByteTo(In := Robot_CyclicData[62], Size := UINT#4, Order := _LOW_HIGH, OutVal := ROBOT_MotionCount);
END_IF;

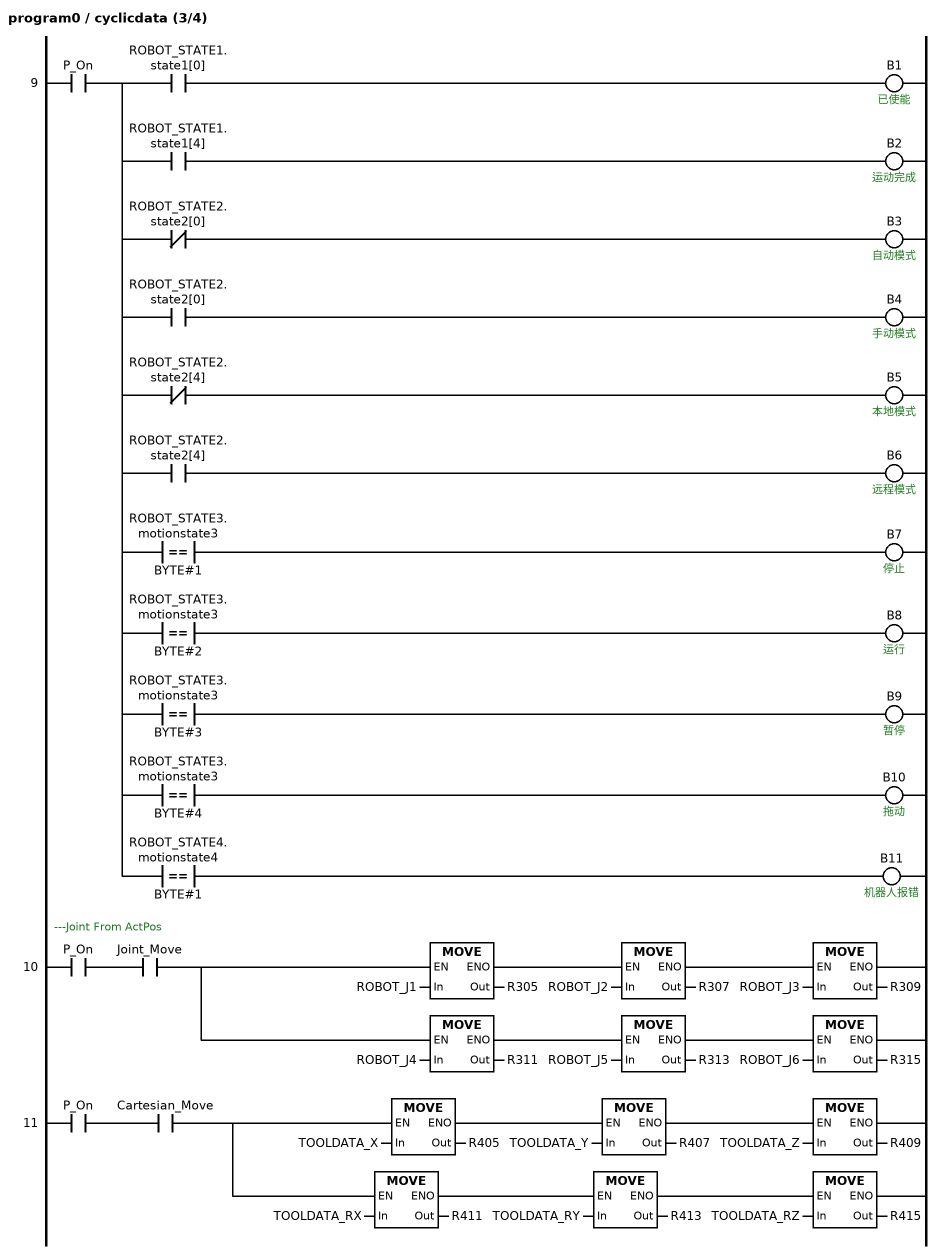
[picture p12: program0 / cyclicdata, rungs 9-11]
(* Rung 9 *)
B1 := P_On AND ROBOT_STATE1.state1[0];
B2 := P_On AND ROBOT_STATE1.state1[4];
B3 := P_On AND NOT ROBOT_STATE2.state2[0];
B4 := P_On AND ROBOT_STATE2.state2[0];
B5 := P_On AND NOT ROBOT_STATE2.state2[4];
B6 := P_On AND ROBOT_STATE2.state2[4];
B7 := P_On AND (ROBOT_STATE3.motionstate3 = BYTE#1);
B8 := P_On AND (ROBOT_STATE3.motionstate3 = BYTE#2);
B9 := P_On AND (ROBOT_STATE3.motionstate3 = BYTE#3);
B10 := P_On AND (ROBOT_STATE3.motionstate3 = BYTE#4);
B11 := P_On AND (ROBOT_STATE4.motionstate4 = BYTE#1);
(* Rung 10: ---Joint From ActPos *)
IF P_On AND Joint_Move THEN
    R305 := ROBOT_J1;
    R307 := ROBOT_J2;
    R309 := ROBOT_J3;
    R311 := ROBOT_J4;
    R313 := ROBOT_J5;
    R315 := ROBOT_J6;
END_IF;
(* Rung 11 *)
IF P_On AND Cartesian_Move THEN
    R405 := TOOLDATA_X;
    R407 := TOOLDATA_Y;
    R409 := TOOLDATA_Z;
    R411 := TOOLDATA_RX;
    R413 := TOOLDATA_RY;
    R415 := TOOLDATA_RZ;
END_IF;

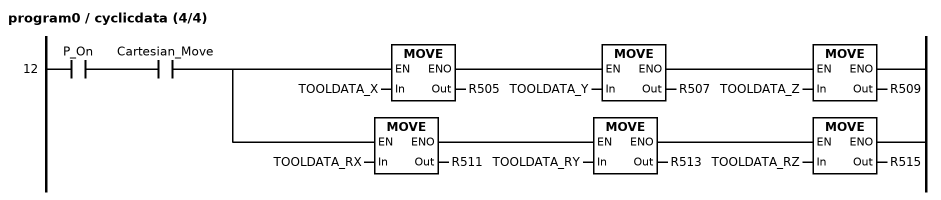
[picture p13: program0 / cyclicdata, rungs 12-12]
(* Rung 12 *)
IF P_On AND Cartesian_Move THEN
    R505 := TOOLDATA_X;
    R507 := TOOLDATA_Y;
    R509 := TOOLDATA_Z;
    R511 := TOOLDATA_RX;
    R513 := TOOLDATA_RY;
    R515 := TOOLDATA_RZ;
END_IF;

(* Section Section0: ladder, written here as Structured Text *)

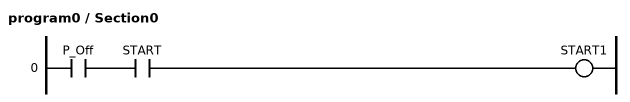
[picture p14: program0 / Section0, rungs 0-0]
(* Rung 0 *)
START1 := P_Off AND START;
END_PROGRAM

FUNCTION_BLOCK RC_EnableRobot
VAR
    CMDLength : BYTE;
    CMDPayLoad : BYTE;
    CMD : UINT;
END_VAR
VAR_INPUT
    Enable : BOOL;
END_VAR
VAR_OUTPUT
    Status : BOOL;
    Busy : BOOL;
    Error : BOOL;
    ErrorID : UINT;
END_VAR
VAR_EXTERNAL
    RobotCMD : UINT;
    RobotCMDLength : BYTE;
    RobotCMDState : BYTE;
    M1 : BOOL;
    M2 : BOOL;
    EnableState : BOOL;
    Robot_CMDHeader : ARRAY[0..9] OF BYTE;
    Robot_Header : ARRAY[0..5] OF BYTE;
    M0 : BOOL;
    Robot_CMDPayload : ARRAY[0..119] OF BYTE;
    PLC_CMDHeader : ARRAY[0..9] OF BYTE;
    PLC_Header : ARRAY[0..5] OF BYTE;
    PLC_CMDPayload : ARRAY[0..238] OF BYTE;
    Robot_CyclicData : ARRAY[0..118] OF BYTE;
    ECT_OUT : ARRAY[0..255] OF BYTE;
    B1 : BOOL;
END_VAR
VAR
    _e1 : R_TRIG;
    _e2 : F_TRIG;
    _e3 : R_TRIG;
    _e4 : F_TRIG;
    _e5 : R_TRIG;
    _e6 : F_TRIG;
    _e7 : R_TRIG;
END_VAR
(* ladder, written here as Structured Text *)

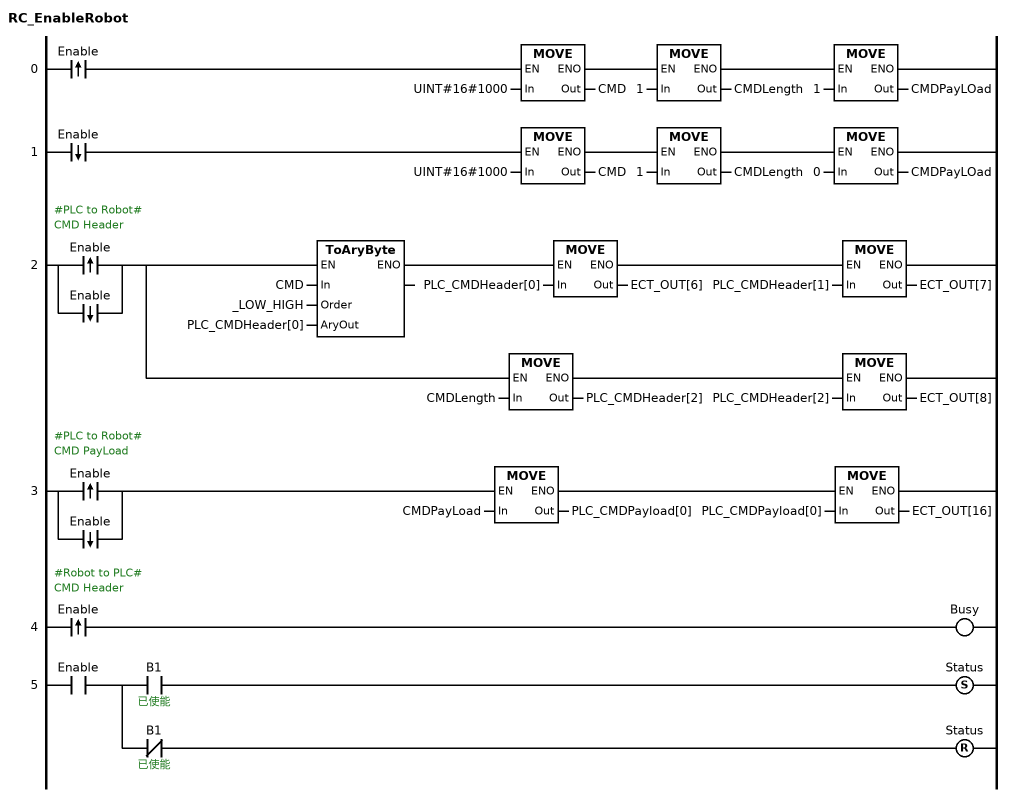
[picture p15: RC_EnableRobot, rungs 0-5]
(* Rung 0 *)
_e1(CLK := Enable);
IF _e1.Q THEN
    CMD := UINT#16#1000;
    CMDLength := 1;
    CMDPayLOad := 1;
END_IF;
(* Rung 1 *)
_e2(CLK := Enable);
IF _e2.Q THEN
    CMD := UINT#16#1000;
    CMDLength := 1;
    CMDPayLOad := 0;
END_IF;
(* Rung 2: #PLC to Robot# / CMD Header *)
_e3(CLK := Enable);
_e4(CLK := Enable);
IF _e3.Q OR _e4.Q THEN
    ToAryByte(In := CMD, Order := _LOW_HIGH, AryOut := PLC_CMDHeader[0]);
    ECT_OUT[6] := PLC_CMDHeader[0];
    ECT_OUT[7] := PLC_CMDHeader[1];
    PLC_CMDHeader[2] := CMDLength;
    ECT_OUT[8] := PLC_CMDHeader[2];
END_IF;
(* Rung 3: #PLC to Robot# / CMD PayLoad *)
_e5(CLK := Enable);
_e6(CLK := Enable);
IF _e5.Q OR _e6.Q THEN
    PLC_CMDPayload[0] := CMDPayLoad;
    ECT_OUT[16] := PLC_CMDPayload[0];
END_IF;
(* Rung 4: #Robot to PLC# / CMD Header *)
_e7(CLK := Enable);
Busy := _e7.Q;
(* Rung 5 *)
IF Enable AND B1 THEN Status := TRUE; END_IF;
IF Enable AND NOT B1 THEN Status := FALSE; END_IF;
END_FUNCTION_BLOCK

FUNCTION_BLOCK RC_WriteToolData
VAR
    CMD : UINT;
    CMDLength : BYTE;
END_VAR
VAR_INPUT
    Execute : BOOL;
    ID : BOOL;
    LoadNo : BOOL;
    ToolNO : BYTE;
    X : REAL;
    Y : REAL;
    Z : REAL;
    RX : REAL;
    RY : REAL;
    RZ : REAL;
END_VAR
VAR_OUTPUT
    Done : BOOL;
    Busy : BOOL;
    Error : BOOL;
    ErrorID : UINT;
END_VAR
VAR_EXTERNAL
    M200 : BOOL;
    Robot_CMDPayload : ARRAY[0..119] OF BYTE;
    RobotCMD : UINT;
    RobotCMDLength : BYTE;
    RobotCMDState : BYTE;
    R205 : REAL;
    R207 : REAL;
    R209 : REAL;
    R211 : REAL;
    R213 : REAL;
    R215 : REAL;
    PLC_CMDHeader : ARRAY[0..9] OF BYTE;
    PLC_Header : ARRAY[0..5] OF BYTE;
    PLC_CMDPayload : ARRAY[0..238] OF BYTE;
    ECT_OUT : ARRAY[0..255] OF BYTE;
END_VAR
VAR
    _e1 : R_TRIG;
END_VAR
(* ladder, written here as Structured Text *)

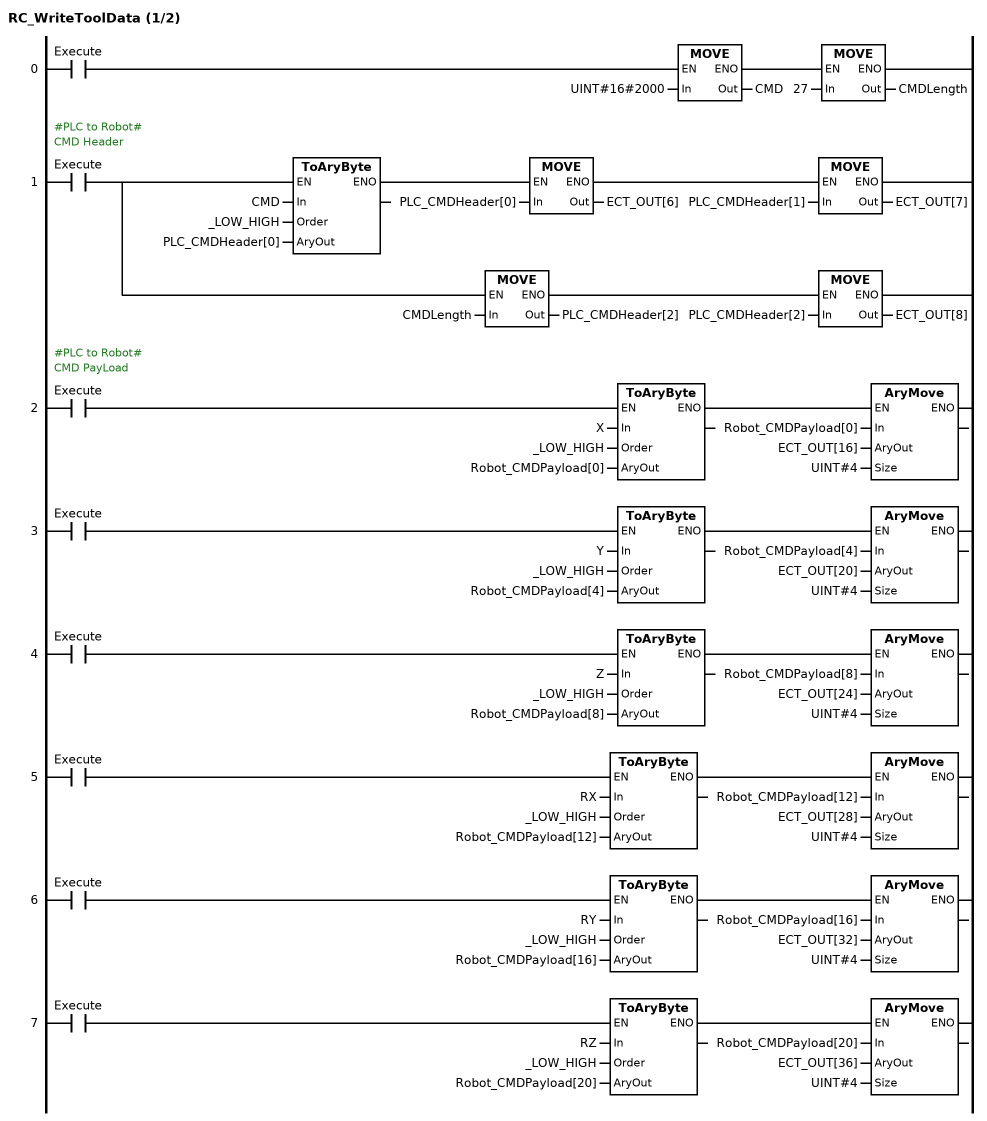
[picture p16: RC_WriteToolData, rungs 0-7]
(* Rung 0 *)
IF Execute THEN
    CMD := UINT#16#2000;
    CMDLength := 27;
END_IF;
(* Rung 1: #PLC to Robot# / CMD Header *)
IF Execute THEN
    ToAryByte(In := CMD, Order := _LOW_HIGH, AryOut := PLC_CMDHeader[0]);
    ECT_OUT[6] := PLC_CMDHeader[0];
    ECT_OUT[7] := PLC_CMDHeader[1];
    PLC_CMDHeader[2] := CMDLength;
    ECT_OUT[8] := PLC_CMDHeader[2];
END_IF;
(* Rung 2: #PLC to Robot# / CMD PayLoad *)
IF Execute THEN
    ToAryByte(In := X, Order := _LOW_HIGH, AryOut := Robot_CMDPayload[0]);
    AryMove(In := Robot_CMDPayload[0], AryOut := ECT_OUT[16], Size := UINT#4);
END_IF;
(* Rung 3 *)
IF Execute THEN
    ToAryByte(In := Y, Order := _LOW_HIGH, AryOut := Robot_CMDPayload[4]);
    AryMove(In := Robot_CMDPayload[4], AryOut := ECT_OUT[20], Size := UINT#4);
END_IF;
(* Rung 4 *)
IF Execute THEN
    ToAryByte(In := Z, Order := _LOW_HIGH, AryOut := Robot_CMDPayload[8]);
    AryMove(In := Robot_CMDPayload[8], AryOut := ECT_OUT[24], Size := UINT#4);
END_IF;
(* Rung 5 *)
IF Execute THEN
    ToAryByte(In := RX, Order := _LOW_HIGH, AryOut := Robot_CMDPayload[12]);
    AryMove(In := Robot_CMDPayload[12], AryOut := ECT_OUT[28], Size := UINT#4);
END_IF;
(* Rung 6 *)
IF Execute THEN
    ToAryByte(In := RY, Order := _LOW_HIGH, AryOut := Robot_CMDPayload[16]);
    AryMove(In := Robot_CMDPayload[16], AryOut := ECT_OUT[32], Size := UINT#4);
END_IF;
(* Rung 7 *)
IF Execute THEN
    ToAryByte(In := RZ, Order := _LOW_HIGH, AryOut := Robot_CMDPayload[20]);
    AryMove(In := Robot_CMDPayload[20], AryOut := ECT_OUT[36], Size := UINT#4);
END_IF;

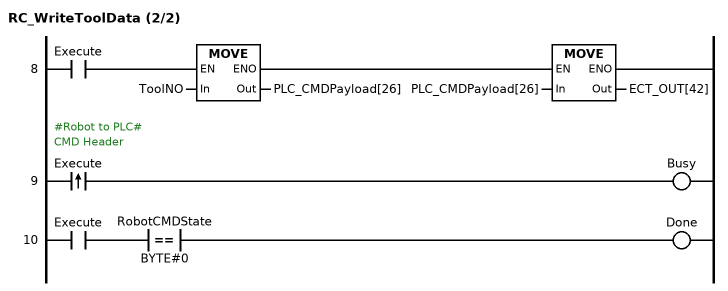
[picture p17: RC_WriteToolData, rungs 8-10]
(* Rung 8 *)
IF Execute THEN
    PLC_CMDPayload[26] := ToolNO;
    ECT_OUT[42] := PLC_CMDPayload[26];
END_IF;
(* Rung 9: #Robot to PLC# / CMD Header *)
_e1(CLK := Execute);
Busy := _e1.Q;
(* Rung 10 *)
Done := Execute AND (RobotCMDState = BYTE#0);
END_FUNCTION_BLOCK

FUNCTION_BLOCK RC_ReadToolData
VAR
    CMD : UINT;
    CMDLength : BYTE;
    CMDPayLoad : BYTE;
END_VAR
VAR_INPUT
    Execute : BOOL;
    ToolNO : BYTE;
END_VAR
VAR_OUTPUT
    Done : BOOL;
    Busy : BOOL;
    ID : BOOL;
    LoadNo : BOOL;
    ToolNo_return : BOOL;
    X_Return : REAL;
    Y_Return : REAL;
    Z_Return : REAL;
    RX_Return : REAL;
    RY_Return : REAL;
    RZ_Return : REAL;
    Error : BOOL;
    ErrorID : UINT;
END_VAR
VAR_EXTERNAL
    Robot_CMDPayload : ARRAY[0..119] OF BYTE;
    RobotCMDLength : BYTE;
    RobotCMDState : BYTE;
    RobotCMD : UINT;
    R160 : REAL;
    R162 : REAL;
    Robot_CyclicData : ARRAY[0..118] OF BYTE;
    Robot_CMDHeader : ARRAY[0..9] OF BYTE;
    PLC_CMDHeader : ARRAY[0..9] OF BYTE;
    PLC_Header : ARRAY[0..5] OF BYTE;
    PLC_CMDPayload : ARRAY[0..238] OF BYTE;
    ECT_OUT : ARRAY[0..255] OF BYTE;
END_VAR
VAR
    _e1 : R_TRIG;
END_VAR
(* ladder, written here as Structured Text *)

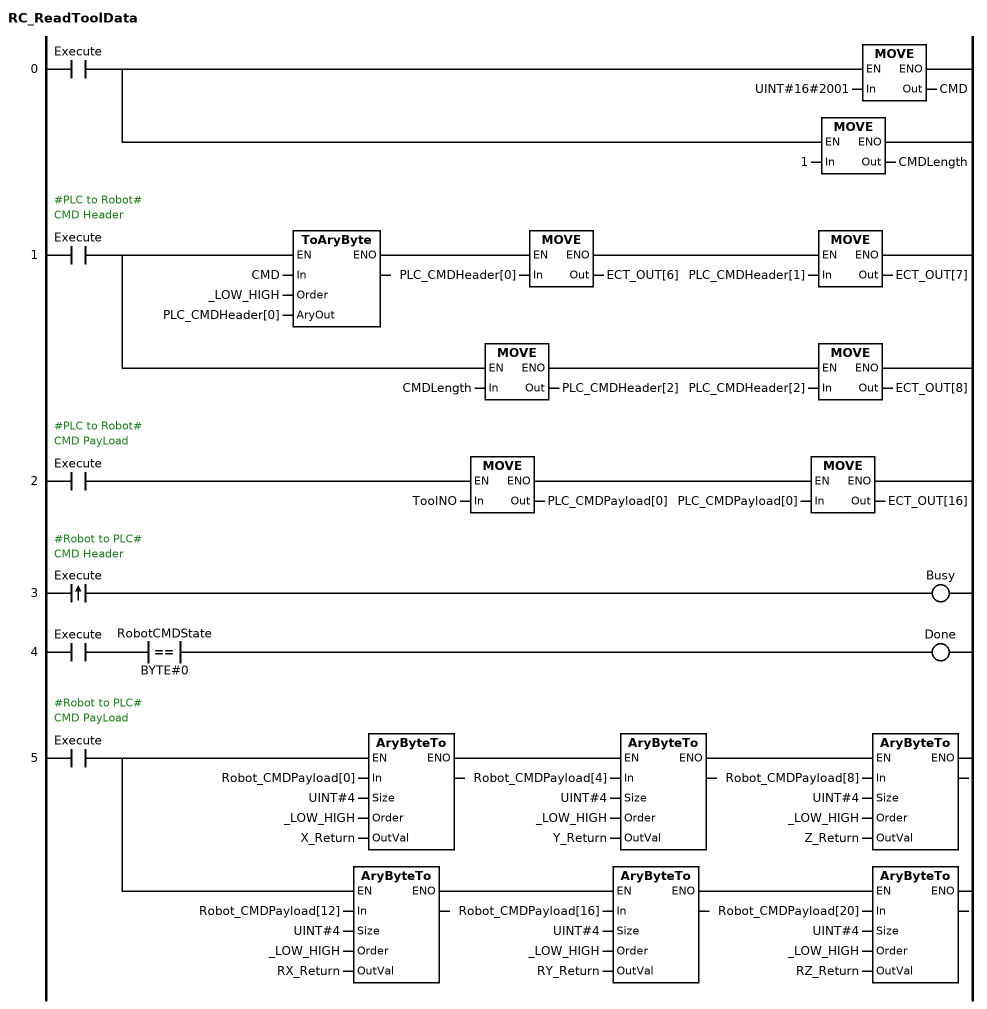
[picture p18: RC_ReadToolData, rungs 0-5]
(* Rung 0 *)
IF Execute THEN
    CMD := UINT#16#2001;
    CMDLength := 1;
END_IF;
(* Rung 1: #PLC to Robot# / CMD Header *)
IF Execute THEN
    ToAryByte(In := CMD, Order := _LOW_HIGH, AryOut := PLC_CMDHeader[0]);
    ECT_OUT[6] := PLC_CMDHeader[0];
    ECT_OUT[7] := PLC_CMDHeader[1];
    PLC_CMDHeader[2] := CMDLength;
    ECT_OUT[8] := PLC_CMDHeader[2];
END_IF;
(* Rung 2: #PLC to Robot# / CMD PayLoad *)
IF Execute THEN
    PLC_CMDPayload[0] := ToolNO;
    ECT_OUT[16] := PLC_CMDPayload[0];
END_IF;
(* Rung 3: #Robot to PLC# / CMD Header *)
_e1(CLK := Execute);
Busy := _e1.Q;
(* Rung 4 *)
Done := Execute AND (RobotCMDState = BYTE#0);
(* Rung 5: #Robot to PLC# / CMD PayLoad *)
IF Execute THEN
    AryByteTo(In := Robot_CMDPayload[0], Size := UINT#4, Order := _LOW_HIGH, OutVal := X_Return);
    AryByteTo(In := Robot_CMDPayload[4], Size := UINT#4, Order := _LOW_HIGH, OutVal := Y_Return);
    AryByteTo(In := Robot_CMDPayload[8], Size := UINT#4, Order := _LOW_HIGH, OutVal := Z_Return);
    AryByteTo(In := Robot_CMDPayload[12], Size := UINT#4, Order := _LOW_HIGH, OutVal := RX_Return);
    AryByteTo(In := Robot_CMDPayload[16], Size := UINT#4, Order := _LOW_HIGH, OutVal := RY_Return);
    AryByteTo(In := Robot_CMDPayload[20], Size := UINT#4, Order := _LOW_HIGH, OutVal := RZ_Return);
END_IF;
END_FUNCTION_BLOCK

FUNCTION_BLOCK RC_MoveAxesAbsolute
VAR
    CMD : UINT;
    CMDLength : BYTE;
    BlendingParameter : ARRAY[0..7] OF BYTE;
    AbortingMode : BYTE;
    BlendingMode : BYTE;
    Cmdid : BYTE;
END_VAR
VAR_INPUT
    Execute : BOOL;
    ToolNo : BYTE;
    velRate : REAL;
    accRate : REAL;
    J1 : REAL;
    J2 : REAL;
    J3 : REAL;
    J4 : REAL;
    J5 : REAL;
    J6 : REAL;
END_VAR
VAR_OUTPUT
    Done : BOOL;
    Busy : BOOL;
    Active : BOOL;
    Aborted : BOOL;
    Interrupt : BOOL;
    Error : BOOL;
    ErrorID : UINT;
END_VAR
VAR_EXTERNAL
    RobotCMDLength : BYTE;
    RobotCMDState : BYTE;
    RobotCMD : UINT;
    Robot_CyclicData : ARRAY[0..118] OF BYTE;
    Robot_CMDHeader : ARRAY[0..9] OF BYTE;
    Robot_CMDPayload : ARRAY[0..119] OF BYTE;
    M300 : BOOL;
    PLC_CMDHeader : ARRAY[0..9] OF BYTE;
    PLC_Header : ARRAY[0..5] OF BYTE;
    PLC_CMDPayload : ARRAY[0..238] OF BYTE;
    B8 : BOOL;
    B2 : BOOL;
    ECT_OUT : ARRAY[0..255] OF BYTE;
END_VAR
VAR
    _e1 : R_TRIG;
    _e2 : R_TRIG;
    _e3 : R_TRIG;
    _e4 : R_TRIG;
    _e5 : R_TRIG;
    _e6 : R_TRIG;
    _e7 : R_TRIG;
    _e8 : R_TRIG;
    _e9 : R_TRIG;
    _e10 : R_TRIG;
    _e11 : R_TRIG;
END_VAR
(* ladder, written here as Structured Text *)

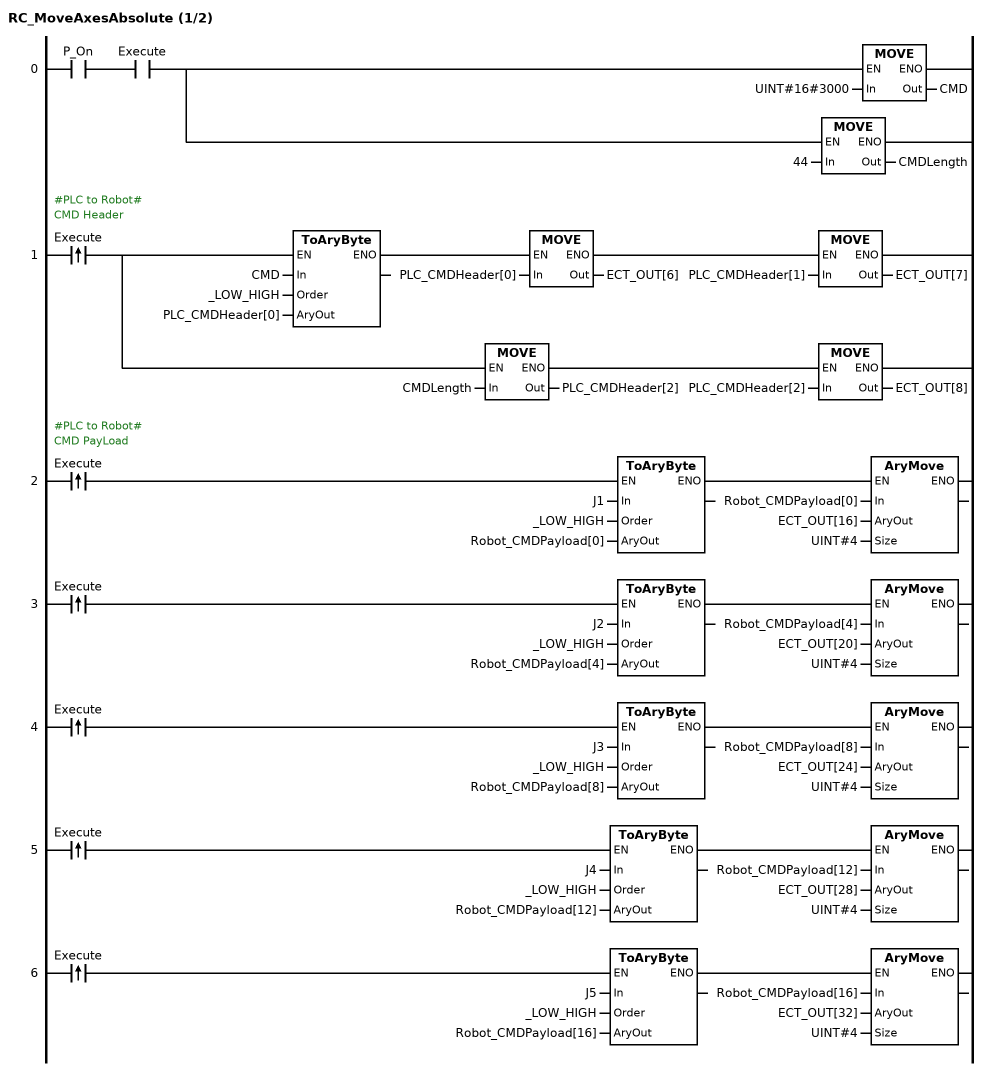
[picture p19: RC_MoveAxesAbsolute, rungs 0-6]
(* Rung 0 *)
IF P_On AND Execute THEN
    CMD := UINT#16#3000;
    CMDLength := 44;
END_IF;
(* Rung 1: #PLC to Robot# / CMD Header *)
_e1(CLK := Execute);
IF _e1.Q THEN
    ToAryByte(In := CMD, Order := _LOW_HIGH, AryOut := PLC_CMDHeader[0]);
    ECT_OUT[6] := PLC_CMDHeader[0];
    ECT_OUT[7] := PLC_CMDHeader[1];
    PLC_CMDHeader[2] := CMDLength;
    ECT_OUT[8] := PLC_CMDHeader[2];
END_IF;
(* Rung 2: #PLC to Robot# / CMD PayLoad *)
_e2(CLK := Execute);
IF _e2.Q THEN
    ToAryByte(In := J1, Order := _LOW_HIGH, AryOut := Robot_CMDPayload[0]);
    AryMove(In := Robot_CMDPayload[0], AryOut := ECT_OUT[16], Size := UINT#4);
END_IF;
(* Rung 3 *)
_e3(CLK := Execute);
IF _e3.Q THEN
    ToAryByte(In := J2, Order := _LOW_HIGH, AryOut := Robot_CMDPayload[4]);
    AryMove(In := Robot_CMDPayload[4], AryOut := ECT_OUT[20], Size := UINT#4);
END_IF;
(* Rung 4 *)
_e4(CLK := Execute);
IF _e4.Q THEN
    ToAryByte(In := J3, Order := _LOW_HIGH, AryOut := Robot_CMDPayload[8]);
    AryMove(In := Robot_CMDPayload[8], AryOut := ECT_OUT[24], Size := UINT#4);
END_IF;
(* Rung 5 *)
_e5(CLK := Execute);
IF _e5.Q THEN
    ToAryByte(In := J4, Order := _LOW_HIGH, AryOut := Robot_CMDPayload[12]);
    AryMove(In := Robot_CMDPayload[12], AryOut := ECT_OUT[28], Size := UINT#4);
END_IF;
(* Rung 6 *)
_e6(CLK := Execute);
IF _e6.Q THEN
    ToAryByte(In := J5, Order := _LOW_HIGH, AryOut := Robot_CMDPayload[16]);
    AryMove(In := Robot_CMDPayload[16], AryOut := ECT_OUT[32], Size := UINT#4);
END_IF;

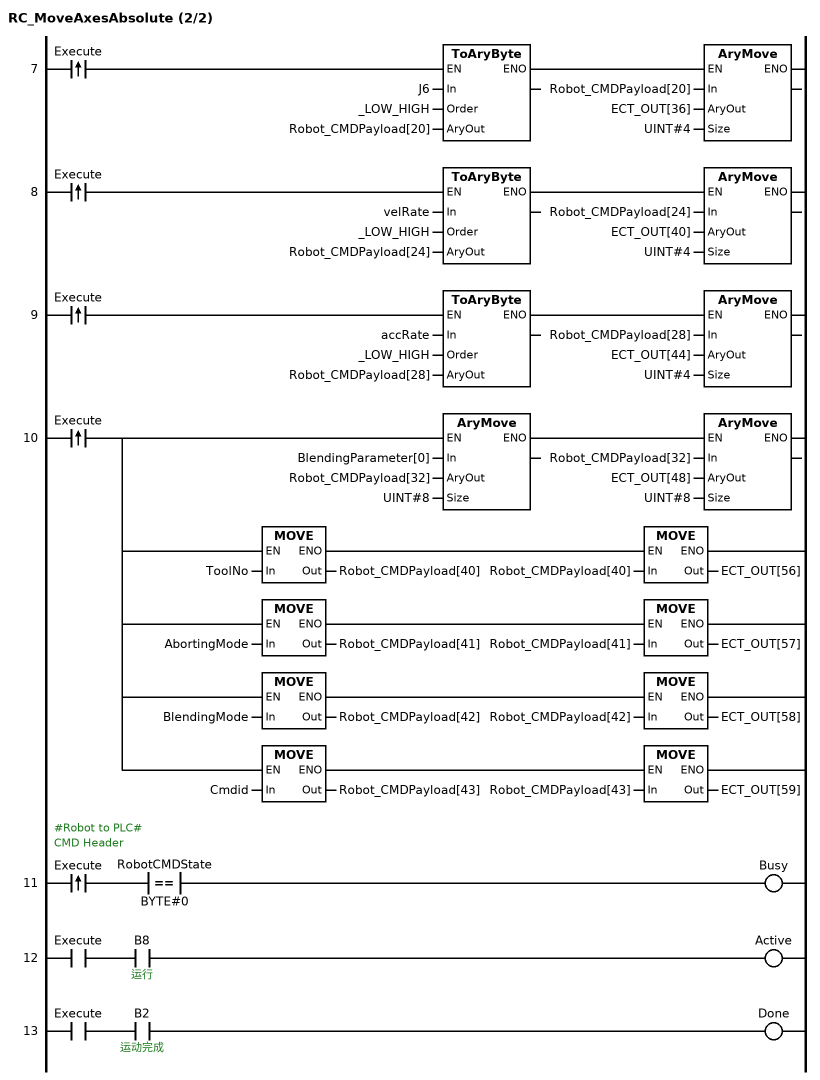
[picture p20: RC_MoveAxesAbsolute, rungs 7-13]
(* Rung 7 *)
_e7(CLK := Execute);
IF _e7.Q THEN
    ToAryByte(In := J6, Order := _LOW_HIGH, AryOut := Robot_CMDPayload[20]);
    AryMove(In := Robot_CMDPayload[20], AryOut := ECT_OUT[36], Size := UINT#4);
END_IF;
(* Rung 8 *)
_e8(CLK := Execute);
IF _e8.Q THEN
    ToAryByte(In := velRate, Order := _LOW_HIGH, AryOut := Robot_CMDPayload[24]);
    AryMove(In := Robot_CMDPayload[24], AryOut := ECT_OUT[40], Size := UINT#4);
END_IF;
(* Rung 9 *)
_e9(CLK := Execute);
IF _e9.Q THEN
    ToAryByte(In := accRate, Order := _LOW_HIGH, AryOut := Robot_CMDPayload[28]);
    AryMove(In := Robot_CMDPayload[28], AryOut := ECT_OUT[44], Size := UINT#4);
END_IF;
(* Rung 10 *)
_e10(CLK := Execute);
IF _e10.Q THEN
    AryMove(In := BlendingParameter[0], AryOut := Robot_CMDPayload[32], Size := UINT#8);
    AryMove(In := Robot_CMDPayload[32], AryOut := ECT_OUT[48], Size := UINT#8);
    Robot_CMDPayload[40] := ToolNo;
    ECT_OUT[56] := Robot_CMDPayload[40];
    Robot_CMDPayload[41] := AbortingMode;
    ECT_OUT[57] := Robot_CMDPayload[41];
    Robot_CMDPayload[42] := BlendingMode;
    ECT_OUT[58] := Robot_CMDPayload[42];
    Robot_CMDPayload[43] := Cmdid;
    ECT_OUT[59] := Robot_CMDPayload[43];
END_IF;
(* Rung 11: #Robot to PLC# / CMD Header *)
_e11(CLK := Execute);
Busy := _e11.Q AND (RobotCMDState = BYTE#0);
(* Rung 12 *)
Active := Execute AND B8;
(* Rung 13 *)
Done := Execute AND B2;
END_FUNCTION_BLOCK

FUNCTION_BLOCK RC_MoveLinearAbsolute
VAR
    CMDLength : BYTE;
    CMD : UINT;
END_VAR
VAR_INPUT
    Execute : BOOL;
    ToolNo : BYTE;
    velRate : REAL;
    accRate : REAL;
    X : REAL;
    Y : REAL;
    Z : REAL;
    RX : REAL;
    RY : REAL;
    RZ : REAL;
END_VAR
VAR_OUTPUT
    Done : BOOL;
    Busy : BOOL;
    Active : BOOL;
    Aborted : BOOL;
    Interrupt : BOOL;
    Error : BOOL;
    ErrorID : UINT;
END_VAR
VAR_EXTERNAL
    RobotCMD : UINT;
    RobotCMDLength : BYTE;
    RobotCMDState : BYTE;
    Robot_CMDPayload : ARRAY[0..119] OF BYTE;
    M200 : BOOL;
    M400 : BOOL;
    PLC_CMDHeader : ARRAY[0..9] OF BYTE;
    PLC_Header : ARRAY[0..5] OF BYTE;
    PLC_CMDPayload : ARRAY[0..238] OF BYTE;
    ECT_OUT : ARRAY[0..255] OF BYTE;
    B8 : BOOL;
    B2 : BOOL;
END_VAR
(* ladder, written here as Structured Text *)

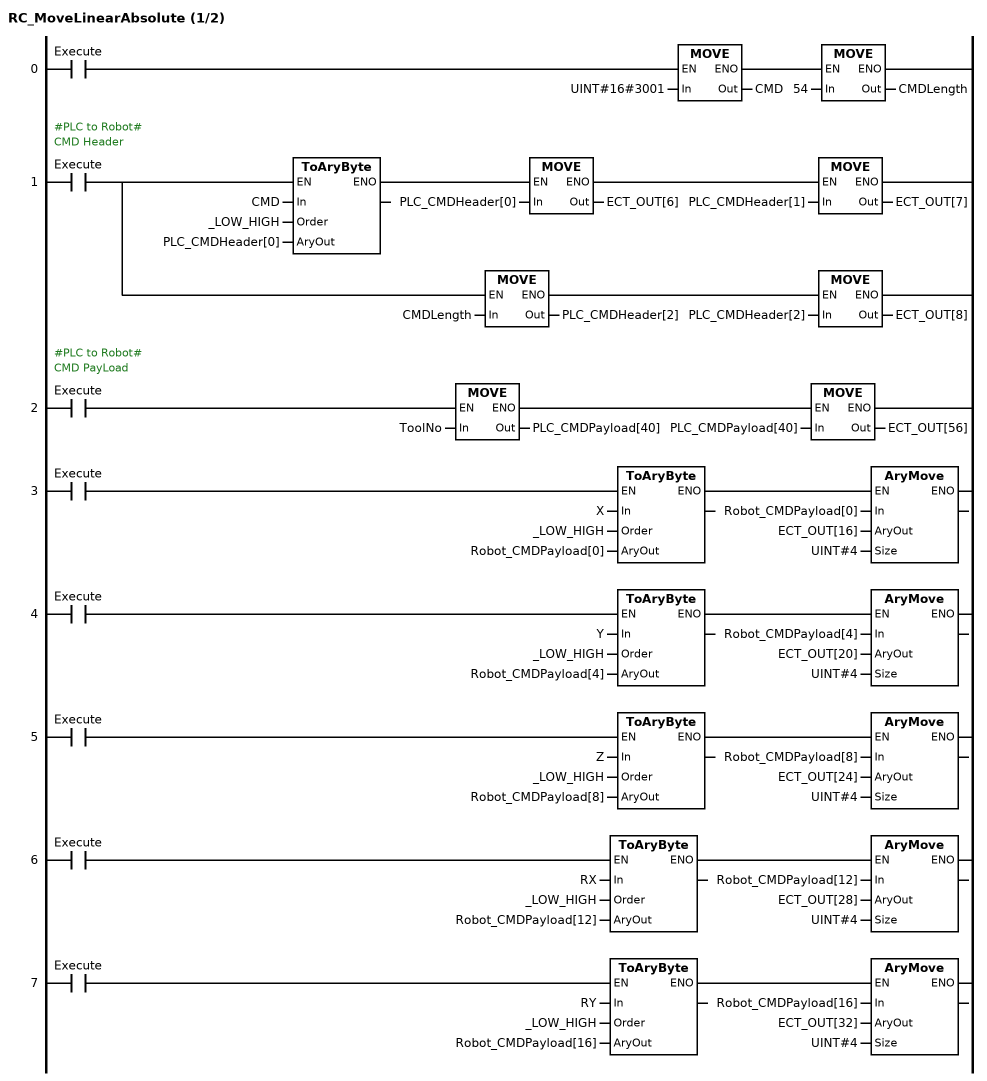
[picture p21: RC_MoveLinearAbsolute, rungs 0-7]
(* Rung 0 *)
IF Execute THEN
    CMD := UINT#16#3001;
    CMDLength := 54;
END_IF;
(* Rung 1: #PLC to Robot# / CMD Header *)
IF Execute THEN
    ToAryByte(In := CMD, Order := _LOW_HIGH, AryOut := PLC_CMDHeader[0]);
    ECT_OUT[6] := PLC_CMDHeader[0];
    ECT_OUT[7] := PLC_CMDHeader[1];
    PLC_CMDHeader[2] := CMDLength;
    ECT_OUT[8] := PLC_CMDHeader[2];
END_IF;
(* Rung 2: #PLC to Robot# / CMD PayLoad *)
IF Execute THEN
    PLC_CMDPayload[40] := ToolNo;
    ECT_OUT[56] := PLC_CMDPayload[40];
END_IF;
(* Rung 3 *)
IF Execute THEN
    ToAryByte(In := X, Order := _LOW_HIGH, AryOut := Robot_CMDPayload[0]);
    AryMove(In := Robot_CMDPayload[0], AryOut := ECT_OUT[16], Size := UINT#4);
END_IF;
(* Rung 4 *)
IF Execute THEN
    ToAryByte(In := Y, Order := _LOW_HIGH, AryOut := Robot_CMDPayload[4]);
    AryMove(In := Robot_CMDPayload[4], AryOut := ECT_OUT[20], Size := UINT#4);
END_IF;
(* Rung 5 *)
IF Execute THEN
    ToAryByte(In := Z, Order := _LOW_HIGH, AryOut := Robot_CMDPayload[8]);
    AryMove(In := Robot_CMDPayload[8], AryOut := ECT_OUT[24], Size := UINT#4);
END_IF;
(* Rung 6 *)
IF Execute THEN
    ToAryByte(In := RX, Order := _LOW_HIGH, AryOut := Robot_CMDPayload[12]);
    AryMove(In := Robot_CMDPayload[12], AryOut := ECT_OUT[28], Size := UINT#4);
END_IF;
(* Rung 7 *)
IF Execute THEN
    ToAryByte(In := RY, Order := _LOW_HIGH, AryOut := Robot_CMDPayload[16]);
    AryMove(In := Robot_CMDPayload[16], AryOut := ECT_OUT[32], Size := UINT#4);
END_IF;

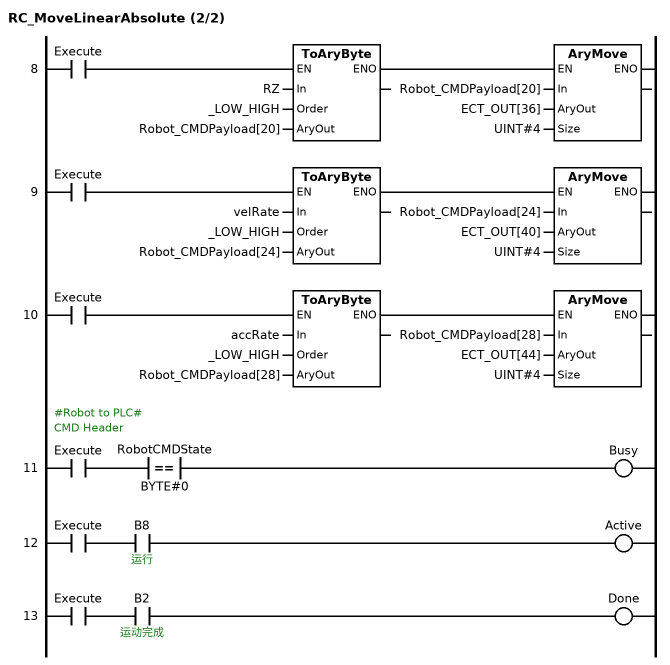
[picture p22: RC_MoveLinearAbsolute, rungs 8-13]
(* Rung 8 *)
IF Execute THEN
    ToAryByte(In := RZ, Order := _LOW_HIGH, AryOut := Robot_CMDPayload[20]);
    AryMove(In := Robot_CMDPayload[20], AryOut := ECT_OUT[36], Size := UINT#4);
END_IF;
(* Rung 9 *)
IF Execute THEN
    ToAryByte(In := velRate, Order := _LOW_HIGH, AryOut := Robot_CMDPayload[24]);
    AryMove(In := Robot_CMDPayload[24], AryOut := ECT_OUT[40], Size := UINT#4);
END_IF;
(* Rung 10 *)
IF Execute THEN
    ToAryByte(In := accRate, Order := _LOW_HIGH, AryOut := Robot_CMDPayload[28]);
    AryMove(In := Robot_CMDPayload[28], AryOut := ECT_OUT[44], Size := UINT#4);
END_IF;
(* Rung 11: #Robot to PLC# / CMD Header *)
Busy := Execute AND (RobotCMDState = BYTE#0);
(* Rung 12 *)
Active := Execute AND B8;
(* Rung 13 *)
Done := Execute AND B2;
END_FUNCTION_BLOCK

FUNCTION_BLOCK RC_MoveDirectAbsolute
VAR
    CMD : UINT;
    CMDLength : BYTE;
END_VAR
VAR_INPUT
    Execute : BOOL;
    ToolNo : BYTE;
    FrameNo : BYTE;
    velRate : REAL;
    accRate : REAL;
    X : REAL;
    Y : REAL;
    Z : REAL;
    RX : REAL;
    RY : REAL;
    RZ : REAL;
END_VAR
VAR_OUTPUT
    Done : BOOL;
    Busy : BOOL;
    Active : BOOL;
    Aborted : BOOL;
    Interrupt : BOOL;
    Error : BOOL;
    ErrorID : UINT;
END_VAR
VAR_EXTERNAL
    RobotCMD : UINT;
    RobotCMDLength : BYTE;
    RobotCMDState : BYTE;
    Robot_CMDPayload : ARRAY[0..119] OF BYTE;
    PLC_CMDHeader : ARRAY[0..9] OF BYTE;
    PLC_Header : ARRAY[0..5] OF BYTE;
    PLC_CMDPayload : ARRAY[0..238] OF BYTE;
    ECT_OUT : ARRAY[0..255] OF BYTE;
    B8 : BOOL;
    B2 : BOOL;
END_VAR
(* ladder, written here as Structured Text *)

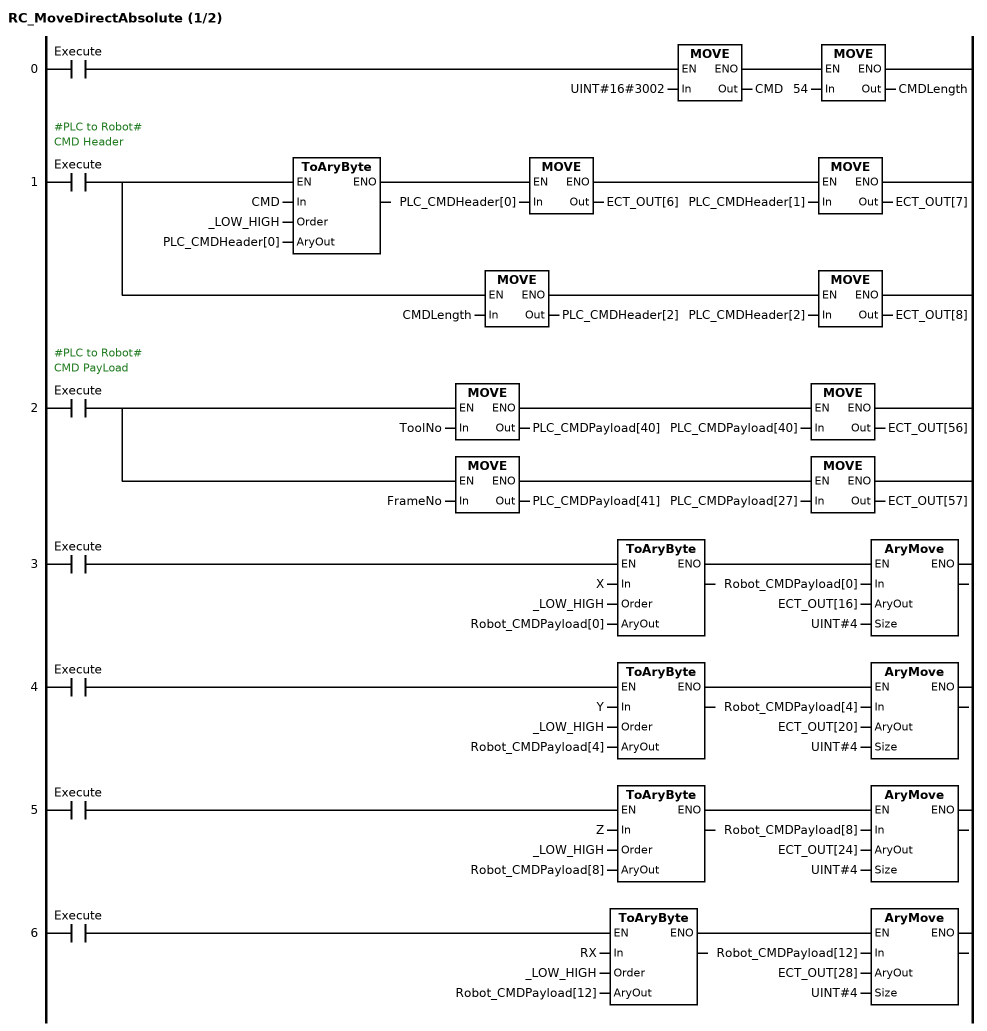
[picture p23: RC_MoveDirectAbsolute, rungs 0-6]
(* Rung 0 *)
IF Execute THEN
    CMD := UINT#16#3002;
    CMDLength := 54;
END_IF;
(* Rung 1: #PLC to Robot# / CMD Header *)
IF Execute THEN
    ToAryByte(In := CMD, Order := _LOW_HIGH, AryOut := PLC_CMDHeader[0]);
    ECT_OUT[6] := PLC_CMDHeader[0];
    ECT_OUT[7] := PLC_CMDHeader[1];
    PLC_CMDHeader[2] := CMDLength;
    ECT_OUT[8] := PLC_CMDHeader[2];
END_IF;
(* Rung 2: #PLC to Robot# / CMD PayLoad *)
IF Execute THEN
    PLC_CMDPayload[40] := ToolNo;
    ECT_OUT[56] := PLC_CMDPayload[40];
    PLC_CMDPayload[41] := FrameNo;
    ECT_OUT[57] := PLC_CMDPayload[27];
END_IF;
(* Rung 3 *)
IF Execute THEN
    ToAryByte(In := X, Order := _LOW_HIGH, AryOut := Robot_CMDPayload[0]);
    AryMove(In := Robot_CMDPayload[0], AryOut := ECT_OUT[16], Size := UINT#4);
END_IF;
(* Rung 4 *)
IF Execute THEN
    ToAryByte(In := Y, Order := _LOW_HIGH, AryOut := Robot_CMDPayload[4]);
    AryMove(In := Robot_CMDPayload[4], AryOut := ECT_OUT[20], Size := UINT#4);
END_IF;
(* Rung 5 *)
IF Execute THEN
    ToAryByte(In := Z, Order := _LOW_HIGH, AryOut := Robot_CMDPayload[8]);
    AryMove(In := Robot_CMDPayload[8], AryOut := ECT_OUT[24], Size := UINT#4);
END_IF;
(* Rung 6 *)
IF Execute THEN
    ToAryByte(In := RX, Order := _LOW_HIGH, AryOut := Robot_CMDPayload[12]);
    AryMove(In := Robot_CMDPayload[12], AryOut := ECT_OUT[28], Size := UINT#4);
END_IF;

(* Rung 7 *)
IF Execute THEN
    ToAryByte(In := RY, Order := _LOW_HIGH, AryOut := Robot_CMDPayload[16]);
    AryMove(In := Robot_CMDPayload[16], AryOut := ECT_OUT[32], Size := UINT#4);
END_IF;
(* Rung 8 *)
IF Execute THEN
    ToAryByte(In := RZ, Order := _LOW_HIGH, AryOut := Robot_CMDPayload[20]);
    AryMove(In := Robot_CMDPayload[20], AryOut := ECT_OUT[36], Size := UINT#4);
END_IF;
(* Rung 9 *)
IF Execute THEN
    ToAryByte(In := velRate, Order := _LOW_HIGH, AryOut := Robot_CMDPayload[24]);
    AryMove(In := Robot_CMDPayload[24], AryOut := ECT_OUT[40], Size := UINT#4);
END_IF;
(* Rung 10 *)
IF Execute THEN
    ToAryByte(In := accRate, Order := _LOW_HIGH, AryOut := Robot_CMDPayload[28]);
    AryMove(In := Robot_CMDPayload[28], AryOut := ECT_OUT[44], Size := UINT#4);
END_IF;
(* Rung 11: #Robot to PLC# / CMD Header *)
Busy := Execute AND (RobotCMDState = BYTE#0);
(* Rung 12 *)
Active := Execute AND B8;
(* Rung 13 *)
Done := Execute AND B2;
END_FUNCTION_BLOCK

FUNCTION_BLOCK RC_GroupReset
VAR
    CMD : UINT;
    CMDLength : BYTE;
END_VAR
VAR_INPUT
    Execute : BOOL;
END_VAR
VAR_OUTPUT
    Done : BOOL;
    Busy : BOOL;
    CommandBuffed : BOOL;
    Error : BOOL;
    ErrorID : UINT;
END_VAR
VAR_EXTERNAL
    PLC_CMDHeader : ARRAY[0..9] OF BYTE;
    ECT_OUT : ARRAY[0..255] OF BYTE;
    PLC_Header : ARRAY[0..5] OF BYTE;
    RobotCMDState : BYTE;
END_VAR
VAR
    _e1 : R_TRIG;
END_VAR
(* ladder, written here as Structured Text *)

(* Rung 0 *)
IF Execute THEN
    CMD := UINT#16#1001;
    CMDLength := 0;
END_IF;
(* Rung 1: #PLC to Robot# / CMD Header *)
IF Execute THEN
    ToAryByte(In := CMD, Order := _LOW_HIGH, AryOut := PLC_CMDHeader[0]);
    ECT_OUT[6] := PLC_CMDHeader[0];
    ECT_OUT[7] := PLC_CMDHeader[1];
    PLC_CMDHeader[2] := CMDLength;
    ECT_OUT[8] := PLC_CMDHeader[2];
END_IF;
(* Rung 2: #Robot to PLC# / CMD Header *)
_e1(CLK := Execute AND (RobotCMDState = BYTE#0));
Busy := _e1.Q;
Done := Execute AND (RobotCMDState = BYTE#0);
END_FUNCTION_BLOCK

FUNCTION_BLOCK RC_GroupStop
VAR
    CMD : UINT;
    CMDLength : BYTE;
END_VAR
VAR_INPUT
    Execute : BOOL;
END_VAR
VAR_OUTPUT
    Done : BOOL;
    Busy : BOOL;
    CommandBuffed : BOOL;
    Active : BOOL;
    Error : BOOL;
    ErrorID : UINT;
    AbortedSequence : UINT;
END_VAR
VAR_EXTERNAL
    PLC_CMDHeader : ARRAY[0..9] OF BYTE;
    ECT_OUT : ARRAY[0..255] OF BYTE;
    PLC_Header : ARRAY[0..5] OF BYTE;
    RobotCMDState : BYTE;
END_VAR
VAR
    _e1 : R_TRIG;
END_VAR
(* ladder, written here as Structured Text *)

(* Rung 0 *)
IF Execute THEN
    CMD := UINT#16#1002;
    CMDLength := 0;
END_IF;
(* Rung 1: #PLC to Robot# / CMD Header *)
IF Execute THEN
    ToAryByte(In := CMD, Order := _LOW_HIGH, AryOut := PLC_CMDHeader[0]);
    ECT_OUT[6] := PLC_CMDHeader[0];
    ECT_OUT[7] := PLC_CMDHeader[1];
    PLC_CMDHeader[2] := CMDLength;
    ECT_OUT[8] := PLC_CMDHeader[2];
END_IF;
(* Rung 2: #Robot to PLC# / CMD Header *)
_e1(CLK := Execute AND (RobotCMDState = BYTE#0));
Busy := _e1.Q;
Done := Execute AND (RobotCMDState = BYTE#0);
END_FUNCTION_BLOCK

FUNCTION_BLOCK RC_ReadActualPosition
VAR
    CMD : UINT;
    CMDLength : BYTE;
    CMD_Return : UINT;
    CMDLength_Return : BYTE;
    RobotConfig : BYTE;
    ToolNoReturn : BYTE;
    FrameNoReturn : BYTE;
END_VAR
VAR_INPUT
    Execute : BOOL;
    ToolNO : BYTE;
    FrameNo : BYTE;
END_VAR
VAR_OUTPUT
    Done : BOOL;
    Valid : BOOL;
    Busy : BOOL;
    CommandBuffered : BOOL;
    CommandAborted : BOOL;
    CommandInterrupt : BOOL;
    ParameterAccepted : BOOL;
    Error : BOOL;
    ErrorID : UINT;
    Position : ARRAY[0..11] OF Real;
    TurnNumber : ARRAY[0..3] OF BYTE;
END_VAR
VAR_EXTERNAL
    PLC_CMDHeader : ARRAY[0..9] OF BYTE;
    ECT_OUT : ARRAY[0..255] OF BYTE;
    PLC_Header : ARRAY[0..5] OF BYTE;
    PLC_CMDPayload : ARRAY[0..238] OF BYTE;
    RobotCMDState : BYTE;
    Robot_CMDPayload : ARRAY[0..119] OF BYTE;
    R881L : BYTE;
    R881H : BYTE;
    R879L : BYTE;
    R879H : BYTE;
    R880L : BYTE;
    R880H : BYTE;
    R882L : BYTE;
    R855 : REAL;
    R857 : REAL;
    R859 : REAL;
    R861 : REAL;
    R863 : REAL;
    R865 : REAL;
    R867 : REAL;
    R869 : REAL;
    R871 : REAL;
    R873 : REAL;
    R875 : REAL;
    R877 : REAL;
END_VAR
(* ladder, written here as Structured Text *)

(* Rung 0 *)
IF Execute THEN
    CMD := UINT#16#1003;
    CMDLength := 2;
END_IF;
(* Rung 1: #PLC to Robot# / CMD Header *)
IF Execute THEN
    ToAryByte(In := CMD, Order := _LOW_HIGH, AryOut := PLC_CMDHeader[0]);
    ECT_OUT[6] := PLC_CMDHeader[0];
    ECT_OUT[7] := PLC_CMDHeader[1];
    PLC_CMDHeader[2] := CMDLength;
    ECT_OUT[8] := PLC_CMDHeader[2];
END_IF;
(* Rung 2: #PLC to Robot# / CMD PayLoad *)
IF Execute THEN
    PLC_CMDPayload[0] := ToolNO;
    ECT_OUT[16] := PLC_CMDPayload[0];
    PLC_CMDPayload[1] := FrameNo;
    ECT_OUT[17] := PLC_CMDPayload[1];
END_IF;
(* Rung 3: #Robot to PLC# / CMD Header *)
Busy := Execute AND (RobotCMDState = BYTE#1);
(* Rung 4 *)
Done := Execute AND (RobotCMDState = BYTE#0);

(* Rung 5: #Robot to PLC# / CMD PayLoad *)
IF Execute THEN
    AryByteTo(In := Robot_CMDPayload[0], Size := UINT#4, Order := _LOW_HIGH, OutVal := Position[0]);
    R855 := Position[0];
    AryByteTo(In := Robot_CMDPayload[4], Size := UINT#4, Order := _LOW_HIGH, OutVal := Position[1]);
    R857 := Position[1];
    AryByteTo(In := Robot_CMDPayload[8], Size := UINT#4, Order := _LOW_HIGH, OutVal := Position[2]);
    R859 := Position[2];
    AryByteTo(In := Robot_CMDPayload[12], Size := UINT#4, Order := _LOW_HIGH, OutVal := Position[3]);
    R861 := Position[3];
    AryByteTo(In := Robot_CMDPayload[16], Size := UINT#4, Order := _LOW_HIGH, OutVal := Position[4]);
    R863 := Position[4];
    AryByteTo(In := Robot_CMDPayload[20], Size := UINT#4, Order := _LOW_HIGH, OutVal := Position[5]);
    R865 := Position[5];
    AryByteTo(In := Robot_CMDPayload[24], Size := UINT#4, Order := _LOW_HIGH, OutVal := Position[6]);
    R867 := Position[6];
    AryByteTo(In := Robot_CMDPayload[28], Size := UINT#4, Order := _LOW_HIGH, OutVal := Position[7]);
    R869 := Position[7];
    AryByteTo(In := Robot_CMDPayload[32], Size := UINT#4, Order := _LOW_HIGH, OutVal := Position[8]);
    R871 := Position[8];
    AryByteTo(In := Robot_CMDPayload[36], Size := UINT#4, Order := _LOW_HIGH, OutVal := Position[9]);
    R873 := Position[9];
    AryByteTo(In := Robot_CMDPayload[40], Size := UINT#4, Order := _LOW_HIGH, OutVal := Position[10]);
    R875 := Position[10];
    AryByteTo(In := Robot_CMDPayload[44], Size := UINT#4, Order := _LOW_HIGH, OutVal := Position[11]);
    R877 := Position[11];
    TurnNumber[0] := Robot_CMDPayload[48];
    TurnNumber[1] := Robot_CMDPayload[49];
    R879L := TurnNumber[0];
    R879H := TurnNumber[1];
    TurnNumber[2] := Robot_CMDPayload[50];
    TurnNumber[3] := Robot_CMDPayload[51];
    R880L := TurnNumber[2];
    R880H := TurnNumber[3];
    RobotConfig := Robot_CMDPayload[52];
    R881L := RobotConfig;
    ToolNoReturn := Robot_CMDPayload[53];
    R881H := ToolNoReturn;
    FrameNoReturn := Robot_CMDPayload[54];
    R882L := FrameNoReturn;
END_IF;
END_FUNCTION_BLOCK

FUNCTION_BLOCK RC_ChangeSpeedOverride
VAR
    CMD : UINT;
    CMDLength : BYTE;
END_VAR
VAR_INPUT
    Execute : BOOL;
    Over_ride : UINT;
END_VAR
VAR_OUTPUT
    Done : BOOL;
    Busy : BOOL;
    CommandBuffered : BOOL;
    Error : BOOL;
    ErrorID : UINT;
END_VAR
VAR_EXTERNAL
    PLC_CMDHeader : ARRAY[0..9] OF BYTE;
    ECT_OUT : ARRAY[0..255] OF BYTE;
    PLC_Header : ARRAY[0..5] OF BYTE;
    RobotCMDState : BYTE;
    PLC_CMDPayload : ARRAY[0..238] OF BYTE;
END_VAR
VAR
    _e1 : R_TRIG;
END_VAR
(* ladder, written here as Structured Text *)

(* Rung 0 *)
IF Execute THEN
    CMD := UINT#16#1004;
    CMDLength := 2;
END_IF;
(* Rung 1: #PLC to Robot# / CMD Header *)
IF Execute THEN
    ToAryByte(In := CMD, Order := _LOW_HIGH, AryOut := PLC_CMDHeader[0]);
    ECT_OUT[6] := PLC_CMDHeader[0];
    ECT_OUT[7] := PLC_CMDHeader[1];
    PLC_CMDHeader[2] := CMDLength;
    ECT_OUT[8] := PLC_CMDHeader[2];
END_IF;
(* Rung 2: #PLC to Robot# / CMD PayLoad *)
IF Execute THEN
    ToAryByte(In := Over_ride, Order := _LOW_HIGH, AryOut := PLC_CMDPayload[0]);
    ECT_OUT[16] := PLC_CMDPayload[0];
    ECT_OUT[17] := PLC_CMDPayload[1];
END_IF;
(* Rung 3: #Robot to PLC# / CMD Header *)
_e1(CLK := Execute AND (RobotCMDState = BYTE#0));
Busy := _e1.Q;
Done := Execute AND (RobotCMDState = BYTE#0);
END_FUNCTION_BLOCK

FUNCTION_BLOCK RC_GroupContinue
VAR
    CMD : UINT;
    CMDLength : BYTE;
END_VAR
VAR_INPUT
    Execute : BOOL;
END_VAR
VAR_OUTPUT
    Done : BOOL;
    Busy : BOOL;
    CommandBuffered : BOOL;
    Error : BOOL;
    ErrorID : UINT;
END_VAR
VAR_EXTERNAL
    PLC_CMDHeader : ARRAY[0..9] OF BYTE;
    ECT_OUT : ARRAY[0..255] OF BYTE;
    PLC_Header : ARRAY[0..5] OF BYTE;
    RobotCMDState : BYTE;
END_VAR
VAR
    _e1 : R_TRIG;
END_VAR
(* ladder, written here as Structured Text *)

(* Rung 0 *)
IF Execute THEN
    CMD := UINT#16#1005;
    CMDLength := 0;
END_IF;
(* Rung 1: #PLC to Robot# / CMD Header *)
IF Execute THEN
    ToAryByte(In := CMD, Order := _LOW_HIGH, AryOut := PLC_CMDHeader[0]);
    ECT_OUT[6] := PLC_CMDHeader[0];
    ECT_OUT[7] := PLC_CMDHeader[1];
    PLC_CMDHeader[2] := CMDLength;
    ECT_OUT[8] := PLC_CMDHeader[2];
END_IF;
(* Rung 2: #Robot to PLC# / CMD Header *)
_e1(CLK := Execute AND (RobotCMDState = BYTE#0));
Busy := _e1.Q;
Done := Execute AND (RobotCMDState = BYTE#0);
END_FUNCTION_BLOCK

FUNCTION_BLOCK RC_GroupInterrupt
VAR
    CMD : UINT;
    CMDLength : BYTE;
END_VAR
VAR_INPUT
    Execute : BOOL;
END_VAR
VAR_OUTPUT
    Done : BOOL;
    Busy : BOOL;
    CommandBuffered : BOOL;
    Active : BOOL;
    Error : BOOL;
    ErrorID : UINT;
END_VAR
VAR_EXTERNAL
    PLC_CMDHeader : ARRAY[0..9] OF BYTE;
    ECT_OUT : ARRAY[0..255] OF BYTE;
    RobotCMDState : BYTE;
END_VAR
VAR
    _e1 : R_TRIG;
END_VAR
(* ladder, written here as Structured Text *)

(* Rung 0 *)
IF Execute THEN
    CMD := UINT#16#1006;
    CMDLength := 0;
END_IF;
(* Rung 1: #PLC to Robot# / CMD Header *)
IF Execute THEN
    ToAryByte(In := CMD, Order := _LOW_HIGH, AryOut := PLC_CMDHeader[0]);
    ECT_OUT[6] := PLC_CMDHeader[0];
    ECT_OUT[7] := PLC_CMDHeader[1];
    PLC_CMDHeader[2] := CMDLength;
    ECT_OUT[8] := PLC_CMDHeader[2];
END_IF;
(* Rung 2: #Robot to PLC# / CMD Header *)
_e1(CLK := Execute AND (RobotCMDState = BYTE#0));
Busy := _e1.Q;
Done := Execute AND (RobotCMDState = BYTE#0);
END_FUNCTION_BLOCK

FUNCTION_BLOCK RC_CartesionFromJoint
VAR
    CMD : UINT;
    CMDLength : BYTE;
    J1 : REAL;
    J2 : REAL;
    J3 : REAL;
    J4 : REAL;
    J5 : REAL;
    J6 : REAL;
    X_Return : REAL;
    Y_Return : REAL;
    Z_Return : REAL;
    RX_Return : REAL;
    RY_Return : REAL;
    RZ_Return : REAL;
END_VAR
VAR_INPUT
    Execute : BOOL;
    Joint_Posion : ARRAY[0..5] OF REAL;
    Def_cartacc : REAL;
END_VAR
VAR_OUTPUT
    Done : BOOL;
    Busy : BOOL;
    CommandBuffered : BOOL;
    Error : BOOL;
    ErrorID : UINT;
END_VAR
VAR_EXTERNAL
    PLC_CMDHeader : ARRAY[0..9] OF BYTE;
    ECT_OUT : ARRAY[0..255] OF BYTE;
    PLC_CMDPayload : ARRAY[0..238] OF BYTE;
    RobotCMDState : BYTE;
    Robot_CMDPayload : ARRAY[0..119] OF BYTE;
    CartestionReturn : ARRAY[0..5] OF REAL;
    CartestionIN : ARRAY[0..5] OF REAL;
    R1317 : DINT;
    R1319L : BYTE;
    JointIN : ARRAY[0..5] OF REAL;
END_VAR
VAR
    _e1 : R_TRIG;
END_VAR
(* ladder, written here as Structured Text *)

(* Rung 0 *)
IF Execute THEN
    CMD := UINT#16#1007;
    CMDLength := 24;
END_IF;
(* Rung 1: #PLC to Robot# / CMD Header *)
IF Execute THEN
    ToAryByte(In := CMD, Order := _LOW_HIGH, AryOut := PLC_CMDHeader[0]);
    ECT_OUT[6] := PLC_CMDHeader[0];
    ECT_OUT[7] := PLC_CMDHeader[1];
    PLC_CMDHeader[2] := CMDLength;
    ECT_OUT[8] := PLC_CMDHeader[2];
END_IF;
(* Rung 2: #PLC to Robot# / CMD PayLoad *)
IF Execute THEN
    ToAryByte(In := JointIN[0], Order := _LOW_HIGH, AryOut := PLC_CMDPayload[0]);
    AryMove(In := PLC_CMDPayload[0], AryOut := ECT_OUT[16], Size := UINT#4);
    ToAryByte(In := JointIN[1], Order := _LOW_HIGH, AryOut := PLC_CMDPayload[4]);
    AryMove(In := PLC_CMDPayload[4], AryOut := ECT_OUT[20], Size := UINT#4);
    ToAryByte(In := JointIN[2], Order := _LOW_HIGH, AryOut := PLC_CMDPayload[8]);
    AryMove(In := PLC_CMDPayload[8], AryOut := ECT_OUT[24], Size := UINT#4);
    ToAryByte(In := JointIN[3], Order := _LOW_HIGH, AryOut := PLC_CMDPayload[12]);
    AryMove(In := PLC_CMDPayload[12], AryOut := ECT_OUT[28], Size := UINT#4);
    ToAryByte(In := JointIN[4], Order := _LOW_HIGH, AryOut := PLC_CMDPayload[16]);
    AryMove(In := PLC_CMDPayload[16], AryOut := ECT_OUT[32], Size := UINT#4);
    ToAryByte(In := JointIN[5], Order := _LOW_HIGH, AryOut := PLC_CMDPayload[20]);
    AryMove(In := PLC_CMDPayload[20], AryOut := ECT_OUT[36], Size := UINT#4);
END_IF;
(* Rung 3: #Robot to PLC# / CMD Header *)
_e1(CLK := Execute AND (RobotCMDState = BYTE#0));
Busy := _e1.Q;
Done := Execute AND (RobotCMDState = BYTE#0);

(* Rung 4: #Robot to PLC# / CMD PayLoad *)
IF Execute THEN
    AryByteTo(In := Robot_CMDPayload[0], Size := UINT#4, Order := _LOW_HIGH, OutVal := CartestionReturn[0]);
    AryByteTo(In := Robot_CMDPayload[4], Size := UINT#4, Order := _LOW_HIGH, OutVal := CartestionReturn[1]);
    AryByteTo(In := Robot_CMDPayload[8], Size := UINT#4, Order := _LOW_HIGH, OutVal := CartestionReturn[2]);
    AryByteTo(In := Robot_CMDPayload[12], Size := UINT#4, Order := _LOW_HIGH, OutVal := CartestionReturn[3]);
    AryByteTo(In := Robot_CMDPayload[16], Size := UINT#4, Order := _LOW_HIGH, OutVal := CartestionReturn[4]);
    AryByteTo(In := Robot_CMDPayload[20], Size := UINT#4, Order := _LOW_HIGH, OutVal := CartestionReturn[5]);
END_IF;
END_FUNCTION_BLOCK

FUNCTION_BLOCK RC_JointFromCartesion
VAR
    CMD : UINT;
    CMDLength : BYTE;
    X : REAL;
    Y : REAL;
    Z : REAL;
    RX : REAL;
    RY : REAL;
    RZ : REAL;
    J1_Return : REAL;
    J2_Return : REAL;
    J3_Return : REAL;
    J4_Return : REAL;
    J5_Return : REAL;
    J6_Return : REAL;
    Config1 : DINT;
END_VAR
VAR_INPUT
    Execute : BOOL;
    Cartesion_Posion : ARRAY[0..5] OF REAL;
    Config : INT;
    Flag : BYTE;
END_VAR
VAR_OUTPUT
    Done : BOOL;
    Busy : BOOL;
    CommandBuffered : BOOL;
    Error : BOOL;
    ErrorID : UINT;
END_VAR
VAR_EXTERNAL
    PLC_CMDHeader : ARRAY[0..9] OF BYTE;
    ECT_OUT : ARRAY[0..255] OF BYTE;
    PLC_CMDPayload : ARRAY[0..238] OF BYTE;
    RobotCMDState : BYTE;
    Robot_CMDPayload : ARRAY[0..119] OF BYTE;
    R1317 : DINT;
    R1319L : BYTE;
    CartestionIN : ARRAY[0..5] OF REAL;
    JointReturn : ARRAY[0..5] OF REAL;
END_VAR
VAR
    _e1 : R_TRIG;
END_VAR
(* ladder, written here as Structured Text *)

(* Rung 0 *)
IF Execute THEN
    CMD := UINT#16#1008;
    CMDLength := 29;
END_IF;
(* Rung 1: #PLC to Robot# / CMD Header *)
IF Execute THEN
    ToAryByte(In := CMD, Order := _LOW_HIGH, AryOut := PLC_CMDHeader[0]);
    ECT_OUT[6] := PLC_CMDHeader[0];
    ECT_OUT[7] := PLC_CMDHeader[1];
    PLC_CMDHeader[2] := CMDLength;
    ECT_OUT[8] := PLC_CMDHeader[2];
END_IF;
(* Rung 2: #PLC to Robot# / CMD PayLoad *)
IF Execute THEN
    ToAryByte(In := CartestionIN[0], Order := _LOW_HIGH, AryOut := PLC_CMDPayload[0]);
    AryMove(In := PLC_CMDPayload[0], AryOut := ECT_OUT[16], Size := UINT#4);
    ToAryByte(In := CartestionIN[1], Order := _LOW_HIGH, AryOut := PLC_CMDPayload[4]);
    AryMove(In := PLC_CMDPayload[4], AryOut := ECT_OUT[20], Size := UINT#4);
    ToAryByte(In := CartestionIN[2], Order := _LOW_HIGH, AryOut := PLC_CMDPayload[8]);
    AryMove(In := PLC_CMDPayload[8], AryOut := ECT_OUT[24], Size := UINT#4);
    ToAryByte(In := CartestionIN[3], Order := _LOW_HIGH, AryOut := PLC_CMDPayload[12]);
    AryMove(In := PLC_CMDPayload[12], AryOut := ECT_OUT[28], Size := UINT#4);
    ToAryByte(In := CartestionIN[4], Order := _LOW_HIGH, AryOut := PLC_CMDPayload[16]);
    AryMove(In := PLC_CMDPayload[16], AryOut := ECT_OUT[32], Size := UINT#4);
    ToAryByte(In := CartestionIN[5], Order := _LOW_HIGH, AryOut := PLC_CMDPayload[20]);
    AryMove(In := PLC_CMDPayload[20], AryOut := ECT_OUT[36], Size := UINT#4);
    ToAryByte(In := R1317, Order := _LOW_HIGH, AryOut := PLC_CMDPayload[24]);
    AryMove(In := PLC_CMDPayload[24], AryOut := ECT_OUT[40], Size := UINT#4);
    PLC_CMDPayload[28] := R1319L;
    ECT_OUT[44] := PLC_CMDPayload[28];
END_IF;

(* Rung 3: #Robot to PLC# / CMD Header *)
_e1(CLK := Execute AND (RobotCMDState = BYTE#0));
Busy := _e1.Q;
Done := Execute AND (RobotCMDState = BYTE#0);
(* Rung 4: #Robot to PLC# / CMD PayLoad *)
IF Execute THEN
    AryByteTo(In := Robot_CMDPayload[0], Size := UINT#4, Order := _LOW_HIGH, OutVal := JointReturn[0]);
    AryByteTo(In := Robot_CMDPayload[4], Size := UINT#4, Order := _LOW_HIGH, OutVal := JointReturn[1]);
    AryByteTo(In := Robot_CMDPayload[8], Size := UINT#4, Order := _LOW_HIGH, OutVal := JointReturn[2]);
    AryByteTo(In := Robot_CMDPayload[12], Size := UINT#4, Order := _LOW_HIGH, OutVal := JointReturn[3]);
    AryByteTo(In := Robot_CMDPayload[16], Size := UINT#4, Order := _LOW_HIGH, OutVal := JointReturn[4]);
    AryByteTo(In := Robot_CMDPayload[20], Size := UINT#4, Order := _LOW_HIGH, OutVal := JointReturn[5]);
END_IF;
END_FUNCTION_BLOCK

FUNCTION_BLOCK RC_WriteFrameData
VAR
    CMD : UINT;
    CMDLength : BYTE;
    CMDPayLoad : STRING[256];
    ReferenceFrame : BYTE;
END_VAR
VAR_INPUT
    Execute : BOOL;
    FrameNo : BYTE;
    FrameData : ARRAY[0..5] OF REAL;
END_VAR
VAR_OUTPUT
    Done : BOOL;
    Busy : BOOL;
    CommandBuffered : BOOL;
    CommandAborted : BOOL;
    CommandInterrupt : BOOL;
    Error : BOOL;
    ErrorID : UINT;
END_VAR
VAR_INPUT
    X : REAL;
    Y : REAL;
    Z : REAL;
    RX : REAL;
    RY : REAL;
    RZ : REAL;
END_VAR
VAR_EXTERNAL
    PLC_CMDHeader : ARRAY[0..9] OF BYTE;
    ECT_OUT : ARRAY[0..255] OF BYTE;
    PLC_CMDPayload : ARRAY[0..238] OF BYTE;
    RobotCMDState : BYTE;
    Robot_CMDPayload : ARRAY[0..119] OF BYTE;
END_VAR
VAR
    _e1 : R_TRIG;
END_VAR
(* ladder, written here as Structured Text *)

(* Rung 0 *)
IF Execute THEN
    CMD := UINT#16#2002;
    CMDLength := 26;
END_IF;
(* Rung 1: #PLC to Robot# / CMD Header *)
IF Execute THEN
    ToAryByte(In := CMD, Order := _LOW_HIGH, AryOut := PLC_CMDHeader[0]);
    ECT_OUT[6] := PLC_CMDHeader[0];
    ECT_OUT[7] := PLC_CMDHeader[1];
    PLC_CMDHeader[2] := CMDLength;
    ECT_OUT[8] := PLC_CMDHeader[2];
    ToAryByte(In := CMDPayLoad, Order := _LOW_HIGH, AryOut := PLC_CMDPayload[0]);
    ECT_OUT[16] := PLC_CMDPayload[0];
    ECT_OUT[17] := PLC_CMDPayload[1];
END_IF;

(* Rung 2: #PLC to Robot# / CMD PayLoad *)
IF Execute THEN
    ToAryByte(In := X, Order := _LOW_HIGH, AryOut := Robot_CMDPayload[0]);
    AryMove(In := Robot_CMDPayload[0], AryOut := ECT_OUT[16], Size := UINT#4);
    ToAryByte(In := Y, Order := _LOW_HIGH, AryOut := Robot_CMDPayload[4]);
    AryMove(In := Robot_CMDPayload[4], AryOut := ECT_OUT[20], Size := UINT#4);
    ToAryByte(In := Z, Order := _LOW_HIGH, AryOut := Robot_CMDPayload[8]);
    AryMove(In := Robot_CMDPayload[8], AryOut := ECT_OUT[24], Size := UINT#4);
    ToAryByte(In := RX, Order := _LOW_HIGH, AryOut := Robot_CMDPayload[12]);
    AryMove(In := Robot_CMDPayload[12], AryOut := ECT_OUT[28], Size := UINT#4);
    ToAryByte(In := RY, Order := _LOW_HIGH, AryOut := Robot_CMDPayload[16]);
    AryMove(In := Robot_CMDPayload[16], AryOut := ECT_OUT[32], Size := UINT#4);
    ToAryByte(In := RZ, Order := _LOW_HIGH, AryOut := Robot_CMDPayload[20]);
    AryMove(In := Robot_CMDPayload[20], AryOut := ECT_OUT[36], Size := UINT#4);
    Robot_CMDPayload[24] := FrameNo;
    ECT_OUT[40] := Robot_CMDPayload[24];
    Robot_CMDPayload[25] := ReferenceFrame;
    ECT_OUT[41] := Robot_CMDPayload[25];
END_IF;
(* Rung 3: #Robot to PLC# / CMD Header *)
_e1(CLK := Execute AND (RobotCMDState = BYTE#0));
Busy := _e1.Q;
Done := Execute AND (RobotCMDState = BYTE#0);
END_FUNCTION_BLOCK

FUNCTION_BLOCK RC_ReadFrameData
VAR
    CMD : UINT;
    CMDLength : BYTE;
END_VAR
VAR_INPUT
    Execute : BOOL;
    FrameNo : BYTE;
END_VAR
VAR_OUTPUT
    Done : BOOL;
    Busy : BOOL;
    CommandBuffered : BOOL;
    Error : BOOL;
    ErrorID : UINT;
    FrameNoReturn : BYTE;
    ToolData : STRING[256];
    X : REAL;
    Y : REAL;
    Z : REAL;
    RX : REAL;
    RY : REAL;
    RZ : REAL;
END_VAR
VAR_EXTERNAL
    PLC_CMDHeader : ARRAY[0..9] OF BYTE;
    ECT_OUT : ARRAY[0..255] OF BYTE;
    RobotCMDState : BYTE;
    PLC_CMDPayload : ARRAY[0..238] OF BYTE;
    ECT_IN : ARRAY[0..255] OF BYTE;
END_VAR
VAR
    _e1 : R_TRIG;
END_VAR
(* ladder, written here as Structured Text *)

(* Rung 0 *)
IF Execute THEN
    CMD := UINT#16#2003;
    CMDLength := 1;
END_IF;
(* Rung 1: #PLC to Robot# / CMD Header *)
IF Execute THEN
    ToAryByte(In := CMD, Order := _LOW_HIGH, AryOut := PLC_CMDHeader[0]);
    ECT_OUT[6] := PLC_CMDHeader[0];
    ECT_OUT[7] := PLC_CMDHeader[1];
    PLC_CMDHeader[2] := CMDLength;
    ECT_OUT[8] := PLC_CMDHeader[2];
END_IF;
(* Rung 2: #PLC to Robot# / CMD PayLoad *)
IF Execute THEN
    ToAryByte(In := FrameNo, Order := _LOW_HIGH, AryOut := PLC_CMDPayload[0]);
    ECT_OUT[16] := PLC_CMDPayload[0];
END_IF;
(* Rung 3: #Robot to PLC# / CMD Header *)
_e1(CLK := Execute AND (RobotCMDState = BYTE#0));
Busy := _e1.Q;
Done := Execute AND (RobotCMDState = BYTE#0);
(* Rung 4: #Robot to PLC# / CMD PayLoad *)
IF Execute THEN
    AryByteTo(In := ECT_IN[16], Size := UINT#4, Order := _LOW_HIGH, OutVal := X);
    AryByteTo(In := ECT_IN[20], Size := UINT#4, Order := _LOW_HIGH, OutVal := Y);
    AryByteTo(In := ECT_IN[24], Size := UINT#4, Order := _LOW_HIGH, OutVal := Z);
    AryByteTo(In := ECT_IN[28], Size := UINT#4, Order := _LOW_HIGH, OutVal := RX);
    AryByteTo(In := ECT_IN[32], Size := UINT#4, Order := _LOW_HIGH, OutVal := RY);
    AryByteTo(In := ECT_IN[36], Size := UINT#4, Order := _LOW_HIGH, OutVal := RZ);
    FrameNoReturn := ECT_IN[37];
END_IF;
END_FUNCTION_BLOCK

FUNCTION_BLOCK RC_WriteLoadData
VAR
    CMD : UINT;
    CMDLength : BYTE;
END_VAR
VAR_INPUT
    Execute : BOOL;
    LoadNo : BYTE;
    LoadData : ARRAY[0..3] OF REAL;
END_VAR
VAR_OUTPUT
    Done : BOOL;
    Busy : BOOL;
    CommandBuffered : BOOL;
    CommandAborted : BOOL;
    CommandInterrupt : BOOL;
    Error : BOOL;
    ErrorID : UINT;
END_VAR
VAR_INPUT
    mass : REAL;
    X_IN : REAL;
    Y_IN : REAL;
    Z_IN : REAL;
END_VAR
VAR_EXTERNAL
    PLC_CMDHeader : ARRAY[0..9] OF BYTE;
    ECT_OUT : ARRAY[0..255] OF BYTE;
    PLC_CMDPayload : ARRAY[0..238] OF BYTE;
    RobotCMDState : BYTE;
END_VAR
VAR
    _e1 : R_TRIG;
END_VAR
(* ladder, written here as Structured Text *)

(* Rung 0 *)
IF Execute THEN
    CMD := UINT#16#2004;
    CMDLength := 17;
END_IF;
(* Rung 1: #PLC to Robot# / CMD Header *)
IF Execute THEN
    ToAryByte(In := CMD, Order := _LOW_HIGH, AryOut := PLC_CMDHeader[0]);
    ECT_OUT[6] := PLC_CMDHeader[0];
    ECT_OUT[7] := PLC_CMDHeader[1];
    PLC_CMDHeader[2] := CMDLength;
    ECT_OUT[8] := PLC_CMDHeader[2];
END_IF;
(* Rung 2: #PLC to Robot# / CMD PayLoad *)
IF Execute THEN
    ToAryByte(In := mass, Order := _LOW_HIGH, AryOut := PLC_CMDPayload[0]);
    AryMove(In := PLC_CMDPayload[0], AryOut := ECT_OUT[16], Size := UINT#4);
    ToAryByte(In := X_IN, Order := _LOW_HIGH, AryOut := PLC_CMDPayload[4]);
    AryMove(In := PLC_CMDPayload[4], AryOut := ECT_OUT[20], Size := UINT#4);
    ToAryByte(In := Y_IN, Order := _LOW_HIGH, AryOut := PLC_CMDPayload[8]);
    AryMove(In := PLC_CMDPayload[8], AryOut := ECT_OUT[24], Size := UINT#4);
    ToAryByte(In := Z_IN, Order := _LOW_HIGH, AryOut := PLC_CMDPayload[12]);
    AryMove(In := PLC_CMDPayload[12], AryOut := ECT_OUT[28], Size := UINT#4);
    ToAryByte(In := LoadNo, Order := _LOW_HIGH, AryOut := PLC_CMDPayload[16]);
    ECT_OUT[32] := PLC_CMDPayload[16];
END_IF;
(* Rung 3: #Robot to PLC# / CMD Header *)
_e1(CLK := Execute AND (RobotCMDState = BYTE#0));
Busy := _e1.Q;
Done := Execute AND (RobotCMDState = BYTE#0);
END_FUNCTION_BLOCK

FUNCTION_BLOCK RC_ReadLoadData
VAR
    CMD : UINT;
    CMDLength : BYTE;
END_VAR
VAR_INPUT
    Execute : BOOL;
    LoadNo : BYTE;
END_VAR
VAR_OUTPUT
    Done : BOOL;
    Busy : BOOL;
    CommandBuffered : BOOL;
    Error : BOOL;
    ErrorID : UINT;
    LoadNoReturn : BYTE;
    LoadData : BYTE;
    mass_Return : REAL;
    X_Return : REAL;
    Y_Return : REAL;
    Z_Return : REAL;
END_VAR
VAR_EXTERNAL
    PLC_CMDHeader : ARRAY[0..9] OF BYTE;
    ECT_OUT : ARRAY[0..255] OF BYTE;
    PLC_CMDPayload : ARRAY[0..238] OF BYTE;
    RobotCMDState : BYTE;
    Robot_CMDPayload : ARRAY[0..119] OF BYTE;
END_VAR
VAR
    _e1 : R_TRIG;
END_VAR
(* ladder, written here as Structured Text *)

(* Rung 0 *)
IF Execute THEN
    CMD := UINT#16#2005;
    CMDLength := 1;
END_IF;
(* Rung 1: #PLC to Robot# / CMD Header *)
IF Execute THEN
    ToAryByte(In := CMD, Order := _LOW_HIGH, AryOut := PLC_CMDHeader[0]);
    ECT_OUT[6] := PLC_CMDHeader[0];
    ECT_OUT[7] := PLC_CMDHeader[1];
    PLC_CMDHeader[2] := CMDLength;
    ECT_OUT[8] := PLC_CMDHeader[2];
END_IF;
(* Rung 2: #PLC to Robot# / CMD PayLoad *)
IF Execute THEN
    ToAryByte(In := LoadNo, Order := _LOW_HIGH, AryOut := PLC_CMDPayload[0]);
    ECT_OUT[16] := PLC_CMDPayload[0];
END_IF;
(* Rung 3: #Robot to PLC# / CMD Header *)
_e1(CLK := Execute AND (RobotCMDState = BYTE#0));
Busy := _e1.Q;
Done := Execute AND (RobotCMDState = BYTE#0);
(* Rung 4: #Robot to PLC# / CMD PayLoad *)
IF Execute THEN
    AryByteTo(In := Robot_CMDPayload[0], Size := UINT#4, Order := _LOW_HIGH, OutVal := mass_Return);
    AryByteTo(In := Robot_CMDPayload[4], Size := UINT#4, Order := _LOW_HIGH, OutVal := X_Return);
    AryByteTo(In := Robot_CMDPayload[12], Size := UINT#4, Order := _LOW_HIGH, OutVal := Z_Return);
    AryByteTo(In := Robot_CMDPayload[8], Size := UINT#4, Order := _LOW_HIGH, OutVal := Y_Return);
    LoadNoReturn := Robot_CMDPayload[16];
END_IF;
END_FUNCTION_BLOCK

FUNCTION_BLOCK RC_WriteRobotReferenceDynamics
VAR
    CMD : UINT;
    CMDLength : BYTE;
END_VAR
VAR_INPUT
    Execute : BOOL;
    DynamicValues : ARRAY[0..1] OF REAL;
END_VAR
VAR_OUTPUT
    Done : BOOL;
    Busy : BOOL;
    CommandBuffered : BOOL;
    Error : BOOL;
    ErrorID : UINT;
    ReferenceDynamicValues : ARRAY[0..1] OF REAL;
END_VAR
VAR_INPUT
    max_cartvel : REAL;
    max_cartacc : REAL;
END_VAR
VAR_EXTERNAL
    PLC_CMDHeader : ARRAY[0..9] OF BYTE;
    ECT_OUT : ARRAY[0..255] OF BYTE;
    PLC_CMDPayload : ARRAY[0..238] OF BYTE;
    RobotCMDState : BYTE;
END_VAR
VAR
    _e1 : R_TRIG;
END_VAR
(* ladder, written here as Structured Text *)

(* Rung 0 *)
IF Execute THEN
    CMD := UINT#16#2006;
    CMDLength := 8;
END_IF;
(* Rung 1: #PLC to Robot# / CMD Header *)
IF Execute THEN
    ToAryByte(In := CMD, Order := _LOW_HIGH, AryOut := PLC_CMDHeader[0]);
    ECT_OUT[6] := PLC_CMDHeader[0];
    ECT_OUT[7] := PLC_CMDHeader[1];
    PLC_CMDHeader[2] := CMDLength;
    ECT_OUT[8] := PLC_CMDHeader[2];
END_IF;
(* Rung 2: #PLC to Robot# / CMD PayLoad *)
IF Execute THEN
    ToAryByte(In := max_cartvel, Order := _LOW_HIGH, AryOut := PLC_CMDPayload[0]);
    AryMove(In := PLC_CMDPayload[0], AryOut := ECT_OUT[16], Size := UINT#4);
    ToAryByte(In := max_cartacc, Order := _LOW_HIGH, AryOut := PLC_CMDPayload[4]);
    AryMove(In := PLC_CMDPayload[4], AryOut := ECT_OUT[20], Size := UINT#4);
END_IF;
(* Rung 3: #Robot to PLC# / CMD Header *)
_e1(CLK := Execute AND (RobotCMDState = BYTE#0));
Busy := _e1.Q;
Done := Execute AND (RobotCMDState = BYTE#0);
END_FUNCTION_BLOCK

FUNCTION_BLOCK RC_ReadRobotReferenceDynamics
VAR
    CMD : UINT;
    CMDLength : BYTE;
    max_cartvelReturn : REAL;
    max_cartaccReturn : REAL;
END_VAR
VAR_INPUT
    Execute : BOOL;
END_VAR
VAR_OUTPUT
    Done : BOOL;
    Busy : BOOL;
    CommandBuffered : BOOL;
    Error : BOOL;
    ErrorID : UINT;
    DynamicValues : ARRAY[0..1] OF REAL;
END_VAR
VAR_EXTERNAL
    PLC_CMDHeader : ARRAY[0..9] OF BYTE;
    ECT_OUT : ARRAY[0..255] OF BYTE;
    RobotCMDState : BYTE;
    Robot_CMDPayload : ARRAY[0..119] OF BYTE;
    R1955 : REAL;
    R1957 : REAL;
END_VAR
VAR
    _e1 : R_TRIG;
END_VAR
(* ladder, written here as Structured Text *)

(* Rung 0 *)
IF Execute THEN
    CMD := UINT#16#2007;
    CMDLength := 0;
END_IF;
(* Rung 1: #PLC to Robot# / CMD Header *)
IF Execute THEN
    ToAryByte(In := CMD, Order := _LOW_HIGH, AryOut := PLC_CMDHeader[0]);
    ECT_OUT[6] := PLC_CMDHeader[0];
    ECT_OUT[7] := PLC_CMDHeader[1];
    PLC_CMDHeader[2] := CMDLength;
    ECT_OUT[8] := PLC_CMDHeader[2];
END_IF;
(* Rung 2: #Robot to PLC# / CMD Header *)
_e1(CLK := Execute AND (RobotCMDState = BYTE#0));
Busy := _e1.Q;
Done := Execute AND (RobotCMDState = BYTE#0);
(* Rung 3: #Robot to PLC# / CMD PayLoad *)
IF Execute THEN
    AryByteTo(In := Robot_CMDPayload[0], Size := UINT#4, Order := _LOW_HIGH, OutVal := max_cartvelReturn);
    R1955 := max_cartvelReturn;
    AryByteTo(In := Robot_CMDPayload[4], Size := UINT#4, Order := _LOW_HIGH, OutVal := max_cartaccReturn);
    R1957 := max_cartaccReturn;
END_IF;
END_FUNCTION_BLOCK

FUNCTION_BLOCK RC_WriteRobotDefaultDynamic
VAR
    CMD : UINT;
    CMDLength : BYTE;
END_VAR
VAR_INPUT
    Execute : BOOL;
    Def_cartval : REAL;
    Def_cartacc : REAL;
END_VAR
VAR_OUTPUT
    Done : BOOL;
    Busy : BOOL;
    CommandBuffered : BOOL;
    Error : BOOL;
    ErrorID : UINT;
END_VAR
VAR_EXTERNAL
    PLC_CMDHeader : ARRAY[0..9] OF BYTE;
    ECT_OUT : ARRAY[0..255] OF BYTE;
    RobotCMDState : BYTE;
    PLC_CMDPayload : ARRAY[0..238] OF BYTE;
END_VAR
VAR
    _e1 : R_TRIG;
END_VAR
(* ladder, written here as Structured Text *)

(* Rung 0 *)
IF Execute THEN
    CMD := UINT#16#2008;
    CMDLength := 8;
END_IF;
(* Rung 1: #PLC to Robot# / CMD Header *)
IF Execute THEN
    ToAryByte(In := CMD, Order := _LOW_HIGH, AryOut := PLC_CMDHeader[0]);
    ECT_OUT[6] := PLC_CMDHeader[0];
    ECT_OUT[7] := PLC_CMDHeader[1];
    PLC_CMDHeader[2] := CMDLength;
    ECT_OUT[8] := PLC_CMDHeader[2];
END_IF;
(* Rung 2: #PLC to Robot# / CMD PayLoad *)
IF Execute THEN
    ToAryByte(In := Def_cartval, Order := _LOW_HIGH, AryOut := PLC_CMDPayload[0]);
    AryMove(In := PLC_CMDPayload[0], AryOut := ECT_OUT[16], Size := UINT#4);
    ToAryByte(In := Def_cartacc, Order := _LOW_HIGH, AryOut := PLC_CMDPayload[4]);
    AryMove(In := PLC_CMDPayload[4], AryOut := ECT_OUT[20], Size := UINT#4);
END_IF;
(* Rung 3: #Robot to PLC# / CMD Header *)
_e1(CLK := Execute AND (RobotCMDState = BYTE#0));
Busy := _e1.Q;
Done := Execute AND (RobotCMDState = BYTE#0);
END_FUNCTION_BLOCK

FUNCTION_BLOCK RC_ReadRobotDefaultDynamic
VAR
    CMD : UINT;
    CMDLength : BYTE;
END_VAR
VAR_INPUT
    Execute : BOOL;
END_VAR
VAR_OUTPUT
    Done : BOOL;
    Busy : BOOL;
    CommandBuffered : BOOL;
    Error : BOOL;
    ErrorID : UINT;
    Def_cartvelReturn : REAL;
    Def_cartaccReturn : REAL;
END_VAR
VAR_EXTERNAL
    PLC_CMDHeader : ARRAY[0..9] OF BYTE;
    ECT_OUT : ARRAY[0..255] OF BYTE;
    RobotCMDState : BYTE;
    Robot_CMDPayload : ARRAY[0..119] OF BYTE;
END_VAR
VAR
    _e1 : R_TRIG;
END_VAR
(* ladder, written here as Structured Text *)

(* Rung 0 *)
IF Execute THEN
    CMD := UINT#16#2009;
    CMDLength := 0;
END_IF;
(* Rung 1: #PLC to Robot# / CMD Header *)
IF Execute THEN
    ToAryByte(In := CMD, Order := _LOW_HIGH, AryOut := PLC_CMDHeader[0]);
    ECT_OUT[6] := PLC_CMDHeader[0];
    ECT_OUT[7] := PLC_CMDHeader[1];
    PLC_CMDHeader[2] := CMDLength;
    ECT_OUT[8] := PLC_CMDHeader[2];
END_IF;
(* Rung 2: #Robot to PLC# / CMD Header *)
_e1(CLK := Execute AND (RobotCMDState = BYTE#0));
Busy := _e1.Q;
Done := Execute AND (RobotCMDState = BYTE#0);
(* Rung 3: #Robot to PLC# / CMD PayLoad *)
IF Execute THEN
    AryByteTo(In := Robot_CMDPayload[0], Size := UINT#4, Order := _LOW_HIGH, OutVal := Def_cartvelReturn);
    AryByteTo(In := Robot_CMDPayload[4], Size := UINT#4, Order := _LOW_HIGH, OutVal := Def_cartaccReturn);
END_IF;
END_FUNCTION_BLOCK

FUNCTION_BLOCK RC_WriteRobotSwLimits
VAR
    CMD : UINT;
    CMDLength : BYTE;
END_VAR
VAR_INPUT
    Execute : BOOL;
    LimitValues : ARRAY[0..1] OF REAL;
    ResetToFactoryDefaults : BOOL;
    J1_max : REAL;
    J2_max : REAL;
    J3_max : REAL;
    J4_max : REAL;
    J5_max : REAL;
    J6_max : REAL;
    J1_min : REAL;
    J2_min : REAL;
    J3_min : REAL;
    J4_min : REAL;
    J5_min : REAL;
    J6_min : REAL;
END_VAR
VAR_OUTPUT
    Done : BOOL;
    Busy : BOOL;
    CommandBuffered : BOOL;
    Error : BOOL;
    ErrorID : UINT;
    RestartRequested : BOOL;
END_VAR
VAR_EXTERNAL
    PLC_CMDHeader : ARRAY[0..9] OF BYTE;
    ECT_OUT : ARRAY[0..255] OF BYTE;
    RobotCMDState : BYTE;
    PLC_CMDPayload : ARRAY[0..238] OF BYTE;
END_VAR
VAR
    _e1 : R_TRIG;
END_VAR
(* ladder, written here as Structured Text *)

(* Rung 0 *)
IF Execute THEN
    CMD := UINT#16#2010;
    CMDLength := 48;
END_IF;
(* Rung 1: #PLC to Robot# / CMD Header *)
IF Execute THEN
    ToAryByte(In := CMD, Order := _LOW_HIGH, AryOut := PLC_CMDHeader[0]);
    ECT_OUT[6] := PLC_CMDHeader[0];
    ECT_OUT[7] := PLC_CMDHeader[1];
    PLC_CMDHeader[2] := CMDLength;
    ECT_OUT[8] := PLC_CMDHeader[2];
END_IF;

(* Rung 2: #PLC to Robot# / CMD PayLoad *)
IF Execute THEN
    ToAryByte(In := J1_max, Order := _LOW_HIGH, AryOut := PLC_CMDPayload[0]);
    AryMove(In := PLC_CMDPayload[0], AryOut := ECT_OUT[16], Size := UINT#4);
    ToAryByte(In := J2_max, Order := _LOW_HIGH, AryOut := PLC_CMDPayload[4]);
    AryMove(In := PLC_CMDPayload[4], AryOut := ECT_OUT[20], Size := UINT#4);
    ToAryByte(In := J3_max, Order := _LOW_HIGH, AryOut := PLC_CMDPayload[8]);
    AryMove(In := PLC_CMDPayload[8], AryOut := ECT_OUT[24], Size := UINT#4);
    ToAryByte(In := J4_max, Order := _LOW_HIGH, AryOut := PLC_CMDPayload[12]);
    AryMove(In := PLC_CMDPayload[12], AryOut := ECT_OUT[28], Size := UINT#4);
    ToAryByte(In := J5_max, Order := _LOW_HIGH, AryOut := PLC_CMDPayload[16]);
    AryMove(In := PLC_CMDPayload[16], AryOut := ECT_OUT[32], Size := UINT#4);
    ToAryByte(In := J6_max, Order := _LOW_HIGH, AryOut := PLC_CMDPayload[20]);
    AryMove(In := PLC_CMDPayload[20], AryOut := ECT_OUT[36], Size := UINT#4);
    ToAryByte(In := J1_min, Order := _LOW_HIGH, AryOut := PLC_CMDPayload[24]);
    AryMove(In := PLC_CMDPayload[24], AryOut := ECT_OUT[40], Size := UINT#4);
    ToAryByte(In := J2_min, Order := _LOW_HIGH, AryOut := PLC_CMDPayload[28]);
    AryMove(In := PLC_CMDPayload[28], AryOut := ECT_OUT[44], Size := UINT#4);
    ToAryByte(In := J3_min, Order := _LOW_HIGH, AryOut := PLC_CMDPayload[32]);
    AryMove(In := PLC_CMDPayload[32], AryOut := ECT_OUT[48], Size := UINT#4);
    ToAryByte(In := J4_min, Order := _LOW_HIGH, AryOut := PLC_CMDPayload[36]);
    AryMove(In := PLC_CMDPayload[36], AryOut := ECT_OUT[52], Size := UINT#4);
    ToAryByte(In := J5_min, Order := _LOW_HIGH, AryOut := PLC_CMDPayload[40]);
    AryMove(In := PLC_CMDPayload[40], AryOut := ECT_OUT[56], Size := UINT#4);
    ToAryByte(In := J6_min, Order := _LOW_HIGH, AryOut := PLC_CMDPayload[44]);
    AryMove(In := PLC_CMDPayload[44], AryOut := ECT_OUT[60], Size := UINT#4);
END_IF;

(* Rung 3: #Robot to PLC# / CMD Header *)
_e1(CLK := Execute AND (RobotCMDState = BYTE#0));
Busy := _e1.Q;
Done := Execute AND (RobotCMDState = BYTE#0);
END_FUNCTION_BLOCK

FUNCTION_BLOCK RC_ReadRobotSwLimits
VAR
    CMD : UINT;
    CMDLength : BYTE;
    jmax_Return : REAL;
    jmin_Return : REAL;
END_VAR
VAR_INPUT
    Execute : BOOL;
END_VAR
VAR_OUTPUT
    Done : BOOL;
    Busy : BOOL;
    CommandBuffered : BOOL;
    Error : BOOL;
    ErrorID : UINT;
    LimitValues : ARRAY[0..1] OF REAL;
    J1_max : REAL;
    J2_max : REAL;
    J3_max : REAL;
    J4_max : REAL;
    J5_max : REAL;
    J6_max : REAL;
    J1_min : REAL;
    J2_min : REAL;
    J3_min : REAL;
    J4_min : REAL;
    J5_min : REAL;
    J6_min : REAL;
END_VAR
VAR_EXTERNAL
    PLC_CMDHeader : ARRAY[0..9] OF BYTE;
    ECT_OUT : ARRAY[0..255] OF BYTE;
    RobotCMDState : BYTE;
    Robot_CMDPayload : ARRAY[0..119] OF BYTE;
END_VAR
VAR
    _e1 : R_TRIG;
END_VAR
(* ladder, written here as Structured Text *)

(* Rung 0 *)
IF Execute THEN
    CMD := UINT#16#2011;
    CMDLength := 0;
END_IF;
(* Rung 1: #PLC to Robot# / CMD Header *)
IF Execute THEN
    ToAryByte(In := CMD, Order := _LOW_HIGH, AryOut := PLC_CMDHeader[0]);
    ECT_OUT[6] := PLC_CMDHeader[0];
    ECT_OUT[7] := PLC_CMDHeader[1];
    PLC_CMDHeader[2] := CMDLength;
    ECT_OUT[8] := PLC_CMDHeader[2];
END_IF;
(* Rung 2: #Robot to PLC# / CMD Header *)
_e1(CLK := Execute AND (RobotCMDState = BYTE#0));
Busy := _e1.Q;
Done := Execute AND (RobotCMDState = BYTE#0);
(* Rung 3: #Robot to PLC# / CMD PayLoad *)
IF Execute THEN
    AryByteTo(In := Robot_CMDPayload[0], Size := UINT#4, Order := _LOW_HIGH, OutVal := J1_max);
    AryByteTo(In := Robot_CMDPayload[4], Size := UINT#4, Order := _LOW_HIGH, OutVal := J2_max);
    AryByteTo(In := Robot_CMDPayload[8], Size := UINT#4, Order := _LOW_HIGH, OutVal := J3_max);
    AryByteTo(In := Robot_CMDPayload[12], Size := UINT#4, Order := _LOW_HIGH, OutVal := J4_max);
    AryByteTo(In := Robot_CMDPayload[16], Size := UINT#4, Order := _LOW_HIGH, OutVal := J5_max);
    AryByteTo(In := Robot_CMDPayload[20], Size := UINT#4, Order := _LOW_HIGH, OutVal := J6_max);
    AryByteTo(In := Robot_CMDPayload[24], Size := UINT#4, Order := _LOW_HIGH, OutVal := J1_min);
    AryByteTo(In := Robot_CMDPayload[28], Size := UINT#4, Order := _LOW_HIGH, OutVal := J2_min);
    AryByteTo(In := Robot_CMDPayload[32], Size := UINT#4, Order := _LOW_HIGH, OutVal := J3_min);
    AryByteTo(In := Robot_CMDPayload[36], Size := UINT#4, Order := _LOW_HIGH, OutVal := J4_min);
    AryByteTo(In := Robot_CMDPayload[40], Size := UINT#4, Order := _LOW_HIGH, OutVal := J5_min);
    AryByteTo(In := Robot_CMDPayload[44], Size := UINT#4, Order := _LOW_HIGH, OutVal := J6_min);
END_IF;
END_FUNCTION_BLOCK

FUNCTION_BLOCK RC_GroupJog
VAR
    CMD : UINT;
    CMDLength : BYTE;
END_VAR
VAR_INPUT
    Enable : BOOL;
    Vel : REAL;
    Acc : REAL;
    MaxDistance : REAL;
    MotionCMD : BYTE;
    JointNum : BYTE;
    Direction : BYTE;
    Control : BOOL;
    ToolNo : BYTE;
    FrameNo : BYTE;
    IncrementalTranslation : BOOL;
    IncrementalRotation : BOOL;
END_VAR
VAR_OUTPUT
    DistanceReached : BOOL;
    Busy : BOOL;
    CommandBuffered : BOOL;
    Enabled : BOOL;
    Active : BOOL;
    CommandAborted : BOOL;
    ParameterAccepted : BOOL;
    Error : BOOL;
    ErrorID : UINT;
END_VAR
VAR_EXTERNAL
    PLC_CMDHeader : ARRAY[0..9] OF BYTE;
    ECT_OUT : ARRAY[0..255] OF BYTE;
    RobotCMDState : BYTE;
    Robot_CMDPayload : ARRAY[0..119] OF BYTE;
    PLC_CMDPayload : ARRAY[0..238] OF BYTE;
END_VAR
VAR
    _e1 : R_TRIG;
    _e2 : F_TRIG;
    _e3 : R_TRIG;
    _e4 : F_TRIG;
    _e5 : R_TRIG;
    _e6 : R_TRIG;
    _e7 : F_TRIG;
    _e8 : R_TRIG;
END_VAR
(* ladder, written here as Structured Text *)

(* Rung 0 *)
Enabled := Enable;
(* Rung 1 *)
_e1(CLK := Enabled);
IF _e1.Q THEN
    CMD := UINT#16#3003;
    CMDLength := 15;
END_IF;
(* Rung 2 *)
_e2(CLK := Enabled);
IF _e2.Q THEN
    CMD := UINT#16#3004;
    CMDLength := 0;
END_IF;
(* Rung 3: #PLC to Robot# / CMD Header *)
_e3(CLK := Enabled);
_e4(CLK := Enabled);
IF _e3.Q OR _e4.Q THEN
    ToAryByte(In := CMD, Order := _LOW_HIGH, AryOut := PLC_CMDHeader[0]);
    ECT_OUT[6] := PLC_CMDHeader[0];
    ECT_OUT[7] := PLC_CMDHeader[1];
    PLC_CMDHeader[2] := CMDLength;
    ECT_OUT[8] := PLC_CMDHeader[2];
END_IF;
(* Rung 4: #PLC to Robot# / CMD PayLoad *)
_e5(CLK := Enabled);
IF _e5.Q THEN
    ToAryByte(In := Vel, Order := _LOW_HIGH, AryOut := PLC_CMDPayload[0]);
    AryMove(In := PLC_CMDPayload[0], AryOut := ECT_OUT[16], Size := UINT#4);
    ToAryByte(In := Acc, Order := _LOW_HIGH, AryOut := PLC_CMDPayload[4]);
    AryMove(In := PLC_CMDPayload[4], AryOut := ECT_OUT[20], Size := UINT#4);
    ToAryByte(In := MaxDistance, Order := _LOW_HIGH, AryOut := PLC_CMDPayload[8]);
    AryMove(In := PLC_CMDPayload[8], AryOut := ECT_OUT[24], Size := UINT#4);
    PLC_CMDPayload[12] := MotionCMD;
    ECT_OUT[28] := PLC_CMDPayload[12];
    PLC_CMDPayload[13] := JointNum;
    ECT_OUT[29] := PLC_CMDPayload[13];
    PLC_CMDPayload[14] := Direction;
    ECT_OUT[30] := PLC_CMDPayload[14];
END_IF;

(* Rung 5: #Robot to PLC# / CMD Header *)
_e6(CLK := Enabled);
_e7(CLK := Enabled);
_e8(CLK := (_e6.Q OR _e7.Q) AND (RobotCMDState = BYTE#0));
Busy := _e8.Q;
END_FUNCTION_BLOCK

FUNCTION_BLOCK RC_ECTDataTransion
VAR_INPUT
    Execute : BOOL;
END_VAR
VAR_EXTERNAL
    ECT_OUT : ARRAY[0..255] OF BYTE;
    Out0 : BYTE;
    Out1 : BYTE;
    Out2 : BYTE;
    Out3 : BYTE;
    Out4 : BYTE;
    Out5 : BYTE;
    Out6 : BYTE;
    Out7 : BYTE;
    Out8 : BYTE;
    Out9 : BYTE;
    Out10 : BYTE;
    Out11 : BYTE;
    Out12 : BYTE;
    Out13 : BYTE;
    Out14 : BYTE;
    Out15 : BYTE;
    Out16 : BYTE;
    Out17 : BYTE;
    Out18 : BYTE;
    Out19 : BYTE;
    Out20 : BYTE;
    Out21 : BYTE;
    Out22 : BYTE;
    Out23 : BYTE;
    Out24 : BYTE;
    Out25 : BYTE;
    Out26 : BYTE;
    Out27 : BYTE;
    Out28 : BYTE;
    Out29 : BYTE;
    Out30 : BYTE;
    Out31 : BYTE;
    Out32 : BYTE;
    Out33 : BYTE;
    Out34 : BYTE;
    Out35 : BYTE;
    Out36 : BYTE;
    Out37 : BYTE;
    Out38 : BYTE;
    Out39 : BYTE;
    Out40 : BYTE;
    Out41 : BYTE;
    Out42 : BYTE;
    Out43 : BYTE;
    Out44 : BYTE;
    Out45 : BYTE;
    Out46 : BYTE;
    Out47 : BYTE;
    Out48 : BYTE;
    Out49 : BYTE;
    Out50 : BYTE;
    Out51 : BYTE;
    Out52 : BYTE;
    Out53 : BYTE;
    Out54 : BYTE;
    Out55 : BYTE;
    Out56 : BYTE;
    Out57 : BYTE;
    Out58 : BYTE;
    Out59 : BYTE;
    Out60 : BYTE;
    Out61 : BYTE;
    Out62 : BYTE;
    Out63 : BYTE;
    Out64 : BYTE;
    Out65 : BYTE;
    Out66 : BYTE;
    Out67 : BYTE;
    Out68 : BYTE;
    Out69 : BYTE;
    Out70 : BYTE;
    Out71 : BYTE;
    Out72 : BYTE;
    Out73 : BYTE;
    Out74 : BYTE;
    Out75 : BYTE;
    Out76 : BYTE;
    Out77 : BYTE;
    Out78 : BYTE;
    Out79 : BYTE;
    Out255 : BYTE;
    ECT_IN : ARRAY[0..255] OF BYTE;
    IN0 : BYTE;
    IN1 : BYTE;
    IN2 : BYTE;
    IN3 : BYTE;
    IN4 : BYTE;
    IN5 : BYTE;
    IN6 : BYTE;
    IN7 : BYTE;
    IN8 : BYTE;
    IN9 : BYTE;
    IN10 : BYTE;
    IN11 : BYTE;
    IN12 : BYTE;
    IN13 : BYTE;
    IN14 : BYTE;
    IN15 : BYTE;
    IN16 : BYTE;
    IN17 : BYTE;
    IN18 : BYTE;
    IN19 : BYTE;
    IN20 : BYTE;
    IN21 : BYTE;
    IN22 : BYTE;
    IN23 : BYTE;
    IN24 : BYTE;
    IN25 : BYTE;
    IN26 : BYTE;
    IN27 : BYTE;
    IN28 : BYTE;
    IN29 : BYTE;
    IN30 : BYTE;
    IN31 : BYTE;
    IN32 : BYTE;
    IN33 : BYTE;
    IN34 : BYTE;
    IN35 : BYTE;
    IN36 : BYTE;
    IN37 : BYTE;
    IN38 : BYTE;
    IN39 : BYTE;
    IN40 : BYTE;
    IN41 : BYTE;
    IN42 : BYTE;
    IN43 : BYTE;
    IN44 : BYTE;
    IN45 : BYTE;
    IN46 : BYTE;
    IN47 : BYTE;
    IN48 : BYTE;
    IN49 : BYTE;
    IN50 : BYTE;
    IN51 : BYTE;
    IN52 : BYTE;
    IN53 : BYTE;
    IN54 : BYTE;
    IN55 : BYTE;
    IN56 : BYTE;
    IN57 : BYTE;
    IN58 : BYTE;
    IN59 : BYTE;
    IN60 : BYTE;
    IN61 : BYTE;
    IN62 : BYTE;
    IN63 : BYTE;
    IN64 : BYTE;
    IN65 : BYTE;
    IN66 : BYTE;
    IN67 : BYTE;
    IN68 : BYTE;
    IN69 : BYTE;
    IN70 : BYTE;
    IN71 : BYTE;
    IN72 : BYTE;
    IN73 : BYTE;
    IN74 : BYTE;
    IN75 : BYTE;
    IN76 : BYTE;
    IN77 : BYTE;
    IN78 : BYTE;
    IN79 : BYTE;
    IN255 : BYTE;
    Out80 : BYTE;
    Out81 : BYTE;
    Out82 : BYTE;
    Out83 : BYTE;
    Out84 : BYTE;
    Out85 : BYTE;
    Out86 : BYTE;
    Out87 : BYTE;
    Out88 : BYTE;
    Out89 : BYTE;
    Out90 : BYTE;
    Out91 : BYTE;
    Out92 : BYTE;
    Out93 : BYTE;
    Out94 : BYTE;
    Out95 : BYTE;
    Out96 : BYTE;
    Out97 : BYTE;
    Out98 : BYTE;
    Out99 : BYTE;
    Out100 : BYTE;
    Out101 : BYTE;
    Out102 : BYTE;
    Out103 : BYTE;
    Out104 : BYTE;
    Out105 : BYTE;
    Out106 : BYTE;
    Out107 : BYTE;
    Out108 : BYTE;
    Out109 : BYTE;
    Out110 : BYTE;
    Out111 : BYTE;
    Out112 : BYTE;
    Out113 : BYTE;
    Out114 : BYTE;
    Out115 : BYTE;
    Out116 : BYTE;
    Out117 : BYTE;
    Out118 : BYTE;
    Out119 : BYTE;
    Out120 : BYTE;
    Out121 : BYTE;
    Out122 : BYTE;
    Out123 : BYTE;
    Out124 : BYTE;
    Out125 : BYTE;
    Out126 : BYTE;
    Out127 : BYTE;
    Out128 : BYTE;
    Out129 : BYTE;
    Out130 : BYTE;
    Out131 : BYTE;
    Out132 : BYTE;
    Out133 : BYTE;
    Out134 : BYTE;
    Out135 : BYTE;
    Out136 : BYTE;
    Out137 : BYTE;
    Out138 : BYTE;
    Out139 : BYTE;
    Out140 : BYTE;
    Out141 : BYTE;
    Out142 : BYTE;
    Out143 : BYTE;
    Out144 : BYTE;
    Out145 : BYTE;
    Out146 : BYTE;
    Out147 : BYTE;
    Out148 : BYTE;
    Out149 : BYTE;
    Out150 : BYTE;
    Out151 : BYTE;
    Out152 : BYTE;
    Out153 : BYTE;
    Out154 : BYTE;
    Out155 : BYTE;
    Out156 : BYTE;
    Out157 : BYTE;
    Out158 : BYTE;
    Out159 : BYTE;
    Out160 : BYTE;
    Out161 : BYTE;
    Out162 : BYTE;
    Out163 : BYTE;
    Out164 : BYTE;
    Out165 : BYTE;
    Out166 : BYTE;
    Out167 : BYTE;
    Out168 : BYTE;
    Out169 : BYTE;
    Out170 : BYTE;
    Out171 : BYTE;
    Out172 : BYTE;
    Out173 : BYTE;
    Out174 : BYTE;
    Out175 : BYTE;
    Out176 : BYTE;
    Out177 : BYTE;
    Out178 : BYTE;
    Out179 : BYTE;
    Out181 : BYTE;
    Out182 : BYTE;
    Out183 : BYTE;
    Out180 : BYTE;
    Out184 : BYTE;
    Out185 : BYTE;
    Out186 : BYTE;
    Out187 : BYTE;
    Out188 : BYTE;
    Out189 : BYTE;
    Out190 : BYTE;
    Out191 : BYTE;
    Out192 : BYTE;
    Out193 : BYTE;
    Out194 : BYTE;
    Out195 : BYTE;
    Out196 : BYTE;
    Out197 : BYTE;
    Out198 : BYTE;
    Out199 : BYTE;
    Out200 : BYTE;
    Out201 : BYTE;
    Out203 : BYTE;
    Out202 : BYTE;
    Out204 : BYTE;
    Out205 : BYTE;
    Out206 : BYTE;
    Out207 : BYTE;
    Out208 : BYTE;
    Out209 : BYTE;
    Out210 : BYTE;
    Out211 : BYTE;
    Out212 : BYTE;
    Out213 : BYTE;
    Out214 : BYTE;
    Out215 : BYTE;
    Out216 : BYTE;
    Out217 : BYTE;
    Out218 : BYTE;
    Out219 : BYTE;
    Out220 : BYTE;
    Out221 : BYTE;
    Out222 : BYTE;
    Out223 : BYTE;
    Out224 : BYTE;
    Out225 : BYTE;
    Out226 : BYTE;
    Out227 : BYTE;
    Out228 : BYTE;
    Out229 : BYTE;
    Out230 : BYTE;
    Out231 : BYTE;
    Out232 : BYTE;
    Out233 : BYTE;
    Out234 : BYTE;
    Out235 : BYTE;
    Out236 : BYTE;
    Out237 : BYTE;
    Out238 : BYTE;
    Out239 : BYTE;
    Out240 : BYTE;
    Out241 : BYTE;
    Out242 : BYTE;
    Out243 : BYTE;
    Out244 : BYTE;
    Out245 : BYTE;
    Out246 : BYTE;
    Out247 : BYTE;
    Out248 : BYTE;
    Out249 : BYTE;
    Out250 : BYTE;
    Out251 : BYTE;
    Out252 : BYTE;
    Out253 : BYTE;
    Out254 : BYTE;
    IN80 : BYTE;
    IN81 : BYTE;
    IN82 : BYTE;
    IN83 : BYTE;
    IN84 : BYTE;
    IN85 : BYTE;
    IN86 : BYTE;
    IN87 : BYTE;
    IN88 : BYTE;
    IN89 : BYTE;
    IN90 : BYTE;
    IN91 : BYTE;
    IN92 : BYTE;
    IN93 : BYTE;
    IN94 : BYTE;
    IN95 : BYTE;
    IN96 : BYTE;
    IN97 : BYTE;
    IN98 : BYTE;
    IN99 : BYTE;
    IN100 : BYTE;
    IN101 : BYTE;
    IN102 : BYTE;
    IN103 : BYTE;
    IN104 : BYTE;
    IN105 : BYTE;
    IN106 : BYTE;
    IN107 : BYTE;
    IN108 : BYTE;
    IN109 : BYTE;
    IN110 : BYTE;
    IN111 : BYTE;
    IN112 : BYTE;
    IN113 : BYTE;
    IN114 : BYTE;
    IN115 : BYTE;
    IN116 : BYTE;
    IN117 : BYTE;
    IN118 : BYTE;
    IN119 : BYTE;
    IN120 : BYTE;
    IN121 : BYTE;
    IN122 : BYTE;
    IN123 : BYTE;
    IN124 : BYTE;
    IN125 : BYTE;
    IN126 : BYTE;
    IN127 : BYTE;
    IN128 : BYTE;
    IN129 : BYTE;
    IN130 : BYTE;
    IN131 : BYTE;
    IN132 : BYTE;
    IN133 : BYTE;
    IN134 : BYTE;
    IN135 : BYTE;
    IN136 : BYTE;
    IN137 : BYTE;
    IN138 : BYTE;
    IN139 : BYTE;
    IN140 : BYTE;
    IN141 : BYTE;
    IN142 : BYTE;
    IN143 : BYTE;
    IN144 : BYTE;
    IN145 : BYTE;
    IN146 : BYTE;
    IN147 : BYTE;
    IN148 : BYTE;
    IN149 : BYTE;
    IN150 : BYTE;
    IN151 : BYTE;
    IN152 : BYTE;
    IN153 : BYTE;
    IN156 : BYTE;
    IN157 : BYTE;
    IN158 : BYTE;
    IN159 : BYTE;
    IN160 : BYTE;
    IN161 : BYTE;
    IN162 : BYTE;
    IN163 : BYTE;
    IN164 : BYTE;
    IN165 : BYTE;
    IN166 : BYTE;
    IN167 : BYTE;
    IN168 : BYTE;
    IN169 : BYTE;
    IN170 : BYTE;
    IN171 : BYTE;
    IN172 : BYTE;
    IN173 : BYTE;
    IN174 : BYTE;
    IN175 : BYTE;
    IN176 : BYTE;
    IN177 : BYTE;
    IN178 : BYTE;
    IN179 : BYTE;
    IN180 : BYTE;
    IN181 : BYTE;
    IN182 : BYTE;
    IN183 : BYTE;
    IN184 : BYTE;
    IN185 : BYTE;
    IN186 : BYTE;
    IN187 : BYTE;
    IN188 : BYTE;
    IN189 : BYTE;
    IN190 : BYTE;
    IN191 : BYTE;
    IN192 : BYTE;
    IN193 : BYTE;
    IN194 : BYTE;
    IN195 : BYTE;
    IN196 : BYTE;
    IN197 : BYTE;
    IN198 : BYTE;
    IN199 : BYTE;
    IN200 : BYTE;
    IN201 : BYTE;
    IN202 : BYTE;
    IN203 : BYTE;
    IN204 : BYTE;
    IN205 : BYTE;
    IN206 : BYTE;
    IN207 : BYTE;
    IN208 : BYTE;
    IN209 : BYTE;
    IN210 : BYTE;
    IN211 : BYTE;
    IN212 : BYTE;
    IN213 : BYTE;
    IN214 : BYTE;
    IN215 : BYTE;
    IN216 : BYTE;
    IN217 : BYTE;
    IN218 : BYTE;
    IN219 : BYTE;
    IN220 : BYTE;
    IN221 : BYTE;
    IN222 : BYTE;
    IN223 : BYTE;
    IN224 : BYTE;
    IN225 : BYTE;
    IN226 : BYTE;
    IN227 : BYTE;
    IN228 : BYTE;
    IN229 : BYTE;
    IN230 : BYTE;
    IN231 : BYTE;
    IN232 : BYTE;
    IN233 : BYTE;
    IN234 : BYTE;
    IN235 : BYTE;
    IN236 : BYTE;
    IN237 : BYTE;
    IN238 : BYTE;
    IN239 : BYTE;
    IN240 : BYTE;
    IN241 : BYTE;
    IN242 : BYTE;
    IN243 : BYTE;
    IN244 : BYTE;
    IN245 : BYTE;
    IN246 : BYTE;
    IN247 : BYTE;
    IN248 : BYTE;
    IN249 : BYTE;
    IN250 : BYTE;
    IN251 : BYTE;
    IN252 : BYTE;
    IN253 : BYTE;
    IN254 : BYTE;
    IN154 : BYTE;
    IN155 : BYTE;
END_VAR
(* ladder, written here as Structured Text *)




(* Rung 0: ----- ECT_OUT[0]-ECT_OUT[255]  TO  OUT0-OUT255 ------ / 当前只做到  ECT_OUT[0]-ECT_OUT[79] TO  OUT0-OUT79 *)
IF Execute THEN
    Out0 := ECT_OUT[0];
    Out1 := ECT_OUT[1];
    Out2 := ECT_OUT[2];
    Out3 := ECT_OUT[3];
    ECT_OUT[4] := ECT_OUT[4];
    Out5 := ECT_OUT[5];
    Out6 := ECT_OUT[6];
    Out7 := ECT_OUT[7];
    Out8 := ECT_OUT[8];
    Out9 := ECT_OUT[9];
    Out10 := ECT_OUT[10];
    Out11 := ECT_OUT[11];
    Out12 := ECT_OUT[12];
    Out13 := ECT_OUT[13];
    Out14 := ECT_OUT[14];
    Out15 := ECT_OUT[15];
    Out16 := ECT_OUT[16];
    Out17 := ECT_OUT[17];
    Out18 := ECT_OUT[18];
    Out19 := ECT_OUT[19];
    Out20 := ECT_OUT[20];
    Out21 := ECT_OUT[21];
    Out22 := ECT_OUT[22];
    Out23 := ECT_OUT[23];
    Out24 := ECT_OUT[24];
    Out25 := ECT_OUT[25];
    Out26 := ECT_OUT[26];
    Out27 := ECT_OUT[27];
    Out28 := ECT_OUT[28];
    Out29 := ECT_OUT[29];
    Out30 := ECT_OUT[30];
    Out31 := ECT_OUT[31];
    Out32 := ECT_OUT[32];
    Out33 := ECT_OUT[33];
    Out34 := ECT_OUT[34];
    Out35 := ECT_OUT[35];
    Out36 := ECT_OUT[36];
    Out37 := ECT_OUT[37];
    Out38 := ECT_OUT[38];
    Out39 := ECT_OUT[39];
    Out40 := ECT_OUT[40];
    Out41 := ECT_OUT[41];
    Out42 := ECT_OUT[42];
    Out43 := ECT_OUT[43];
    Out44 := ECT_OUT[44];
    Out45 := ECT_OUT[45];
    Out46 := ECT_OUT[46];
    Out47 := ECT_OUT[47];
    Out48 := ECT_OUT[48];
    Out49 := ECT_OUT[49];
    Out50 := ECT_OUT[50];
    Out51 := ECT_OUT[51];
    Out52 := ECT_OUT[52];
    Out53 := ECT_OUT[53];
    Out54 := ECT_OUT[54];
    Out55 := ECT_OUT[55];
    Out56 := ECT_OUT[56];
    Out57 := ECT_OUT[57];
    Out58 := ECT_OUT[58];
    Out59 := ECT_OUT[59];
    Out60 := ECT_OUT[60];
    Out61 := ECT_OUT[61];
    Out62 := ECT_OUT[62];
    Out63 := ECT_OUT[63];
    Out64 := ECT_OUT[64];
    Out65 := ECT_OUT[65];
    Out66 := ECT_OUT[66];
    Out67 := ECT_OUT[67];
    Out68 := ECT_OUT[68];
    Out69 := ECT_OUT[69];
    Out70 := ECT_OUT[70];
    Out71 := ECT_OUT[71];
    Out72 := ECT_OUT[72];
    Out73 := ECT_OUT[73];
    Out74 := ECT_OUT[74];
    Out75 := ECT_OUT[75];
    Out76 := ECT_OUT[76];
    Out77 := ECT_OUT[77];
    Out78 := ECT_OUT[78];
    Out79 := ECT_OUT[79];
    Out80 := ECT_OUT[80];
    Out81 := ECT_OUT[81];
    Out82 := ECT_OUT[82];
    Out83 := ECT_OUT[83];
    Out84 := ECT_OUT[84];
    Out85 := ECT_OUT[85];
    Out86 := ECT_OUT[86];
    Out87 := ECT_OUT[87];
    Out88 := ECT_OUT[88];
    Out89 := ECT_OUT[89];
    Out90 := ECT_OUT[90];
    Out91 := ECT_OUT[91];
    Out92 := ECT_OUT[92];
    Out93 := ECT_OUT[93];
    Out94 := ECT_OUT[94];
    Out95 := ECT_OUT[95];
    Out96 := ECT_OUT[96];
    Out97 := ECT_OUT[97];
    Out98 := ECT_OUT[98];
    Out99 := ECT_OUT[99];
    Out100 := ECT_OUT[100];
    Out101 := ECT_OUT[101];
    Out102 := ECT_OUT[102];
    Out103 := ECT_OUT[103];
    Out104 := ECT_OUT[104];
    Out105 := ECT_OUT[105];
    Out106 := ECT_OUT[106];
    Out107 := ECT_OUT[107];
    Out108 := ECT_OUT[108];
    Out109 := ECT_OUT[109];
    Out110 := ECT_OUT[110];
    Out111 := ECT_OUT[111];
    Out112 := ECT_OUT[112];
    Out113 := ECT_OUT[113];
    Out114 := ECT_OUT[114];
    Out115 := ECT_OUT[115];
    Out116 := ECT_OUT[116];
    Out117 := ECT_OUT[117];
    Out118 := ECT_OUT[118];
    Out119 := ECT_OUT[119];
    Out120 := ECT_OUT[120];
    Out121 := ECT_OUT[121];
    Out122 := ECT_OUT[122];
    Out123 := ECT_OUT[123];
    Out124 := ECT_OUT[124];
    Out125 := ECT_OUT[125];
    Out126 := ECT_OUT[126];
    Out127 := ECT_OUT[127];
    Out128 := ECT_OUT[128];
    Out129 := ECT_OUT[129];
    Out130 := ECT_OUT[130];
    Out131 := ECT_OUT[131];
    Out132 := ECT_OUT[132];
    Out133 := ECT_OUT[133];
    Out134 := ECT_OUT[134];
    Out135 := ECT_OUT[135];
    Out136 := ECT_OUT[136];
    Out137 := ECT_OUT[137];
    Out138 := ECT_OUT[138];
    Out139 := ECT_OUT[139];
    Out140 := ECT_OUT[140];
    Out141 := ECT_OUT[141];
    Out142 := ECT_OUT[142];
    Out143 := ECT_OUT[143];
    Out144 := ECT_OUT[144];
    Out145 := ECT_OUT[145];
    Out146 := ECT_OUT[146];
    Out147 := ECT_OUT[147];
    Out148 := ECT_OUT[148];
    Out149 := ECT_OUT[149];
    Out150 := ECT_OUT[150];
    Out151 := ECT_OUT[151];
    Out152 := ECT_OUT[152];
    Out153 := ECT_OUT[153];
    Out154 := ECT_OUT[154];
    Out155 := ECT_OUT[155];
    Out156 := ECT_OUT[156];
    Out157 := ECT_OUT[157];
    Out158 := ECT_OUT[158];
    Out159 := ECT_OUT[159];
    Out160 := ECT_OUT[160];
    Out161 := ECT_OUT[161];
    Out162 := ECT_OUT[162];
    Out163 := ECT_OUT[163];
    Out164 := ECT_OUT[164];
    Out165 := ECT_OUT[165];
    Out166 := ECT_OUT[166];
    Out167 := ECT_OUT[167];
    Out168 := ECT_OUT[168];
    Out169 := ECT_OUT[169];
    Out170 := ECT_OUT[170];
    Out171 := ECT_OUT[171];
    Out172 := ECT_OUT[172];
    Out173 := ECT_OUT[173];
    Out174 := ECT_OUT[174];
    Out175 := ECT_OUT[175];
    Out176 := ECT_OUT[176];
    Out177 := ECT_OUT[177];
    Out178 := ECT_OUT[178];
    Out179 := ECT_OUT[179];
    Out180 := ECT_OUT[180];
    Out181 := ECT_OUT[181];
    Out182 := ECT_OUT[182];
    Out183 := ECT_OUT[183];
    Out184 := ECT_OUT[184];
    Out185 := ECT_OUT[185];
    Out186 := ECT_OUT[186];
    Out187 := ECT_OUT[187];
    Out188 := ECT_OUT[188];
    Out189 := ECT_OUT[189];
    Out190 := ECT_OUT[190];
    Out191 := ECT_OUT[191];
    Out192 := ECT_OUT[192];
    Out193 := ECT_OUT[193];
    Out194 := ECT_OUT[194];
    Out195 := ECT_OUT[195];
    Out196 := ECT_OUT[196];
    Out197 := ECT_OUT[197];
    Out198 := ECT_OUT[198];
    Out199 := ECT_OUT[199];
    Out200 := ECT_OUT[200];
    Out201 := ECT_OUT[201];
    Out202 := ECT_OUT[202];
    Out203 := ECT_OUT[203];
    Out204 := ECT_OUT[204];
    Out205 := ECT_OUT[205];
    Out206 := ECT_OUT[206];
    Out207 := ECT_OUT[207];
    Out208 := ECT_OUT[208];
    Out209 := ECT_OUT[209];
    Out210 := ECT_OUT[210];
    Out211 := ECT_OUT[211];
    Out212 := ECT_OUT[212];
    Out213 := ECT_OUT[213];
    Out214 := ECT_OUT[214];
    Out215 := ECT_OUT[215];
    Out216 := ECT_OUT[216];
    Out217 := ECT_OUT[217];
    Out218 := ECT_OUT[218];
    Out219 := ECT_OUT[219];
    Out220 := ECT_OUT[220];
    Out221 := ECT_OUT[221];
    Out222 := ECT_OUT[222];
    Out223 := ECT_OUT[223];
    Out224 := ECT_OUT[224];
    Out225 := ECT_OUT[225];
    Out226 := ECT_OUT[226];
    Out227 := ECT_OUT[227];
    Out228 := ECT_OUT[228];
    Out229 := ECT_OUT[229];
    Out230 := ECT_OUT[230];
    Out231 := ECT_OUT[231];
    Out232 := ECT_OUT[232];
    Out233 := ECT_OUT[233];
    Out234 := ECT_OUT[234];
    Out235 := ECT_OUT[235];
    Out236 := ECT_OUT[236];
    Out237 := ECT_OUT[237];
    Out238 := ECT_OUT[238];
    Out239 := ECT_OUT[239];
    Out240 := ECT_OUT[240];
    Out241 := ECT_OUT[241];
    Out242 := ECT_OUT[242];
    Out243 := ECT_OUT[243];
    Out244 := ECT_OUT[244];
    Out245 := ECT_OUT[245];
    Out246 := ECT_OUT[246];
    Out247 := ECT_OUT[247];
    Out248 := ECT_OUT[248];
    Out249 := ECT_OUT[249];
    Out250 := ECT_OUT[250];
    Out251 := ECT_OUT[251];
    Out252 := ECT_OUT[252];
    Out253 := ECT_OUT[253];
    Out254 := ECT_OUT[254];
    Out255 := ECT_OUT[255];
END_IF;




(* Rung 1: -----IN0-IN255 TO  ECT_IN[0]-ECT_IN[255]------ / 当前只做到  IN0-IN79 TO  ECT_IN[0]-ECT_IN[79] *)
IF Execute THEN
    ECT_IN[0] := IN0;
    ECT_IN[1] := IN1;
    ECT_IN[2] := IN2;
    ECT_IN[3] := IN3;
    ECT_IN[4] := IN4;
    ECT_IN[5] := IN5;
    ECT_IN[6] := IN6;
    ECT_IN[7] := IN7;
    ECT_IN[8] := IN8;
    ECT_IN[9] := IN9;
    ECT_IN[10] := IN10;
    ECT_IN[11] := IN11;
    ECT_IN[12] := IN12;
    ECT_IN[13] := IN13;
    ECT_IN[14] := IN14;
    ECT_IN[15] := IN15;
    ECT_IN[16] := IN16;
    ECT_IN[17] := IN17;
    ECT_IN[18] := IN18;
    ECT_IN[19] := IN19;
    ECT_IN[20] := IN20;
    ECT_IN[21] := IN21;
    ECT_IN[22] := IN22;
    ECT_IN[23] := IN23;
    ECT_IN[24] := IN24;
    ECT_IN[25] := IN25;
    ECT_IN[26] := IN26;
    ECT_IN[27] := IN27;
    ECT_IN[28] := IN28;
    ECT_IN[29] := IN29;
    ECT_IN[30] := IN30;
    ECT_IN[31] := IN31;
    ECT_IN[32] := IN32;
    ECT_IN[33] := IN33;
    ECT_IN[34] := IN34;
    ECT_IN[35] := IN35;
    ECT_IN[36] := IN36;
    ECT_IN[37] := IN37;
    ECT_IN[38] := IN38;
    ECT_IN[39] := IN39;
    ECT_IN[40] := IN40;
    ECT_IN[41] := IN41;
    ECT_IN[42] := IN42;
    ECT_IN[43] := IN43;
    ECT_IN[44] := IN44;
    ECT_IN[45] := IN45;
    ECT_IN[46] := IN46;
    ECT_IN[47] := IN47;
    ECT_IN[48] := IN48;
    ECT_IN[49] := IN49;
    ECT_IN[50] := IN50;
    ECT_IN[51] := IN51;
    ECT_IN[52] := IN52;
    ECT_IN[53] := IN53;
    ECT_IN[54] := IN54;
    ECT_IN[55] := IN55;
    ECT_IN[56] := IN56;
    ECT_IN[57] := IN57;
    ECT_IN[58] := IN58;
    ECT_IN[59] := IN59;
    ECT_IN[60] := IN60;
    ECT_IN[61] := IN61;
    ECT_IN[62] := IN62;
    ECT_IN[63] := IN63;
    ECT_IN[64] := IN64;
    ECT_IN[65] := IN65;
    ECT_IN[66] := IN66;
    ECT_IN[67] := IN67;
    ECT_IN[68] := IN68;
    ECT_IN[69] := IN69;
    ECT_IN[70] := IN70;
    ECT_IN[71] := IN71;
    ECT_IN[72] := IN72;
    ECT_IN[73] := IN73;
    ECT_IN[74] := IN74;
    ECT_IN[75] := IN75;
    ECT_IN[76] := IN76;
    ECT_IN[77] := IN77;
    ECT_IN[78] := IN78;
    ECT_IN[79] := IN79;
    ECT_IN[80] := IN80;
    ECT_IN[81] := IN81;
    ECT_IN[82] := IN82;
    ECT_IN[83] := IN83;
    ECT_IN[84] := IN84;
    ECT_IN[85] := IN85;
    ECT_IN[86] := IN86;
    ECT_IN[87] := IN87;
    ECT_IN[88] := IN88;
    ECT_IN[89] := IN89;
    ECT_IN[90] := IN90;
    ECT_IN[91] := IN91;
    ECT_IN[92] := IN92;
    ECT_IN[93] := IN93;
    ECT_IN[94] := IN94;
    ECT_IN[95] := IN95;
    ECT_IN[96] := IN96;
    ECT_IN[97] := IN97;
    ECT_IN[98] := IN98;
    ECT_IN[99] := IN99;
    ECT_IN[100] := IN100;
    ECT_IN[101] := IN101;
    ECT_IN[102] := IN102;
    ECT_IN[103] := IN103;
    ECT_IN[104] := IN104;
    ECT_IN[105] := IN105;
    ECT_IN[106] := IN106;
    ECT_IN[107] := IN107;
    ECT_IN[108] := IN108;
    ECT_IN[109] := IN109;
    ECT_IN[110] := IN110;
    ECT_IN[111] := IN111;
    ECT_IN[112] := IN112;
    ECT_IN[113] := IN113;
    ECT_IN[114] := IN114;
    ECT_IN[115] := IN115;
    ECT_IN[116] := IN116;
    ECT_IN[117] := IN117;
    ECT_IN[118] := IN118;
    ECT_IN[119] := IN119;
    ECT_IN[120] := IN120;
    ECT_IN[121] := IN121;
    ECT_IN[122] := IN122;
    ECT_IN[123] := IN123;
    ECT_IN[124] := IN124;
    ECT_IN[125] := IN125;
    ECT_IN[126] := IN126;
    ECT_IN[127] := IN127;
    ECT_IN[128] := IN128;
    ECT_IN[129] := IN129;
    ECT_IN[130] := IN130;
    ECT_IN[131] := IN131;
    ECT_IN[132] := IN132;
    ECT_IN[133] := IN133;
    ECT_IN[134] := IN134;
    ECT_IN[135] := IN135;
    ECT_IN[136] := IN136;
    ECT_IN[137] := IN137;
    ECT_IN[138] := IN138;
    ECT_IN[139] := IN139;
    ECT_IN[140] := IN140;
    ECT_IN[141] := IN141;
    ECT_IN[142] := IN142;
    ECT_IN[143] := IN143;
    ECT_IN[144] := IN144;
    ECT_IN[145] := IN145;
    ECT_IN[146] := IN146;
    ECT_IN[147] := IN147;
    ECT_IN[148] := IN148;
    ECT_IN[149] := IN149;
    ECT_IN[150] := IN150;
    ECT_IN[151] := IN151;
    ECT_IN[152] := IN152;
    ECT_IN[153] := IN153;
    ECT_IN[154] := IN154;
    ECT_IN[155] := IN155;
    ECT_IN[156] := IN156;
    ECT_IN[157] := IN157;
    ECT_IN[158] := IN158;
    ECT_IN[159] := IN159;
    ECT_IN[160] := IN160;
    ECT_IN[161] := IN161;
    ECT_IN[162] := IN162;
    ECT_IN[163] := IN163;
    ECT_IN[164] := IN164;
    ECT_IN[165] := IN165;
    ECT_IN[166] := IN166;
    ECT_IN[167] := IN167;
    ECT_IN[168] := IN168;
    ECT_IN[169] := IN169;
    ECT_IN[170] := IN170;
    ECT_IN[171] := IN171;
    ECT_IN[172] := IN172;
    ECT_IN[173] := IN173;
    ECT_IN[174] := IN174;
    ECT_IN[175] := IN175;
    ECT_IN[176] := IN176;
    ECT_IN[177] := IN177;
    ECT_IN[178] := IN178;
    ECT_IN[179] := IN179;
    ECT_IN[180] := IN180;
    ECT_IN[181] := IN181;
    ECT_IN[182] := IN182;
    ECT_IN[183] := IN183;
    ECT_IN[184] := IN184;
    ECT_IN[185] := IN185;
    ECT_IN[186] := IN186;
    ECT_IN[187] := IN187;
    ECT_IN[188] := IN188;
    ECT_IN[189] := IN189;
    ECT_IN[190] := IN190;
    ECT_IN[191] := IN191;
    ECT_IN[192] := IN192;
    ECT_IN[193] := IN193;
    ECT_IN[194] := IN194;
    ECT_IN[195] := IN195;
    ECT_IN[196] := IN196;
    ECT_IN[197] := IN197;
    ECT_IN[198] := IN198;
    ECT_IN[199] := IN199;
    ECT_IN[200] := IN200;
    ECT_IN[201] := IN201;
    ECT_IN[202] := IN202;
    ECT_IN[203] := IN203;
    ECT_IN[204] := IN204;
    ECT_IN[205] := IN205;
    ECT_IN[206] := IN206;
    ECT_IN[207] := IN207;
    ECT_IN[208] := IN208;
    ECT_IN[209] := IN209;
    ECT_IN[210] := IN210;
    ECT_IN[211] := IN211;
    ECT_IN[212] := IN212;
    ECT_IN[213] := IN213;
    ECT_IN[214] := IN214;
    ECT_IN[215] := IN215;
    ECT_IN[216] := IN216;
    ECT_IN[217] := IN217;
    ECT_IN[218] := IN218;
    ECT_IN[219] := IN219;
    ECT_IN[220] := IN220;
    ECT_IN[221] := IN221;
    ECT_IN[222] := IN222;
    ECT_IN[223] := IN223;
    ECT_IN[224] := IN224;
    ECT_IN[225] := IN225;
    ECT_IN[226] := IN226;
    ECT_IN[227] := IN227;
    ECT_IN[228] := IN228;
    ECT_IN[229] := IN229;
    ECT_IN[230] := IN230;
    ECT_IN[231] := IN231;
    ECT_IN[232] := IN232;
    ECT_IN[233] := IN233;
    ECT_IN[234] := IN234;
    ECT_IN[235] := IN235;
    ECT_IN[236] := IN236;
    ECT_IN[237] := IN237;
    ECT_IN[238] := IN238;
    ECT_IN[239] := IN239;
    ECT_IN[240] := IN240;
    ECT_IN[241] := IN241;
    ECT_IN[242] := IN242;
    ECT_IN[243] := IN243;
    ECT_IN[244] := IN244;
    ECT_IN[245] := IN245;
    ECT_IN[246] := IN246;
    ECT_IN[247] := IN247;
    ECT_IN[248] := IN248;
    ECT_IN[249] := IN249;
    ECT_IN[250] := IN250;
    ECT_IN[251] := IN251;
    ECT_IN[252] := IN252;
    ECT_IN[253] := IN253;
    ECT_IN[254] := IN254;
    ECT_IN[255] := IN255;
END_IF;
END_FUNCTION_BLOCK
